VERSION 5.8 ;
BUSBITCHARS "[]" ;
DIVIDERCHAR "/" ;
UNITS
    DATABASE MICRONS 1000 ;
END UNITS

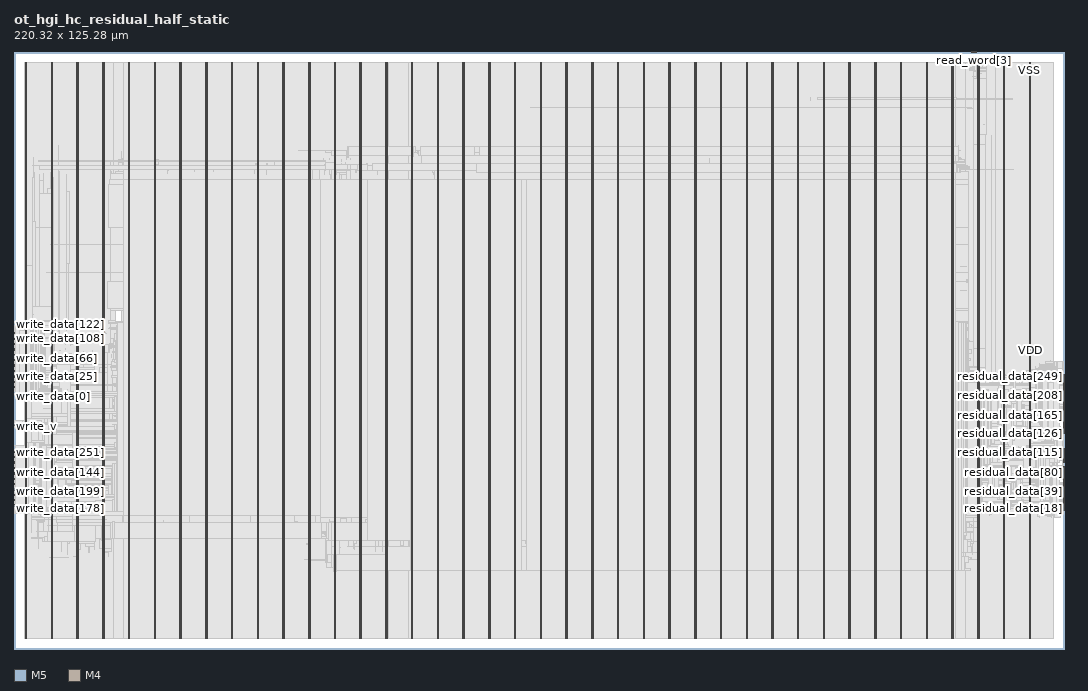
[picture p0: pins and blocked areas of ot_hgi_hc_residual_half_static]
MACRO ot_hgi_hc_residual_half_static
  FOREIGN ot_hgi_hc_residual_half_static 0 0 ;
  CLASS BLOCK ;
  SIZE 220.32 BY 125.28 ;
  PIN clk
    DIRECTION INPUT ;
    USE SIGNAL ;
    PORT
      LAYER M5 ;
        RECT  200.88 125.196 200.904 125.28 ;
    END
  END clk
  PIN fault
    DIRECTION OUTPUT ;
    USE SIGNAL ;
    PORT
      LAYER M4 ;
        RECT  220.236 29.136 220.32 29.16 ;
    END
  END fault
  PIN read_v
    DIRECTION INPUT ;
    USE SIGNAL ;
    PORT
      LAYER M5 ;
        RECT  200.976 125.196 201 125.28 ;
    END
  END read_v
  PIN read_valid
    DIRECTION OUTPUT ;
    USE SIGNAL ;
    PORT
      LAYER M4 ;
        RECT  220.236 29.232 220.32 29.256 ;
    END
  END read_valid
  PIN read_word[0]
    DIRECTION INPUT ;
    USE SIGNAL ;
    PORT
      LAYER M5 ;
        RECT  201.072 125.196 201.096 125.28 ;
    END
  END read_word[0]
  PIN read_word[1]
    DIRECTION INPUT ;
    USE SIGNAL ;
    PORT
      LAYER M5 ;
        RECT  201.168 125.196 201.192 125.28 ;
    END
  END read_word[1]
  PIN read_word[2]
    DIRECTION INPUT ;
    USE SIGNAL ;
    PORT
      LAYER M5 ;
        RECT  201.264 125.196 201.288 125.28 ;
    END
  END read_word[2]
  PIN read_word[3]
    DIRECTION INPUT ;
    USE SIGNAL ;
    PORT
      LAYER M5 ;
        RECT  201.36 125.196 201.384 125.28 ;
    END
  END read_word[3]
  PIN read_word[4]
    DIRECTION INPUT ;
    USE SIGNAL ;
    PORT
      LAYER M5 ;
        RECT  201.456 125.196 201.48 125.28 ;
    END
  END read_word[4]
  PIN read_word[5]
    DIRECTION INPUT ;
    USE SIGNAL ;
    PORT
      LAYER M5 ;
        RECT  201.552 125.196 201.576 125.28 ;
    END
  END read_word[5]
  PIN read_word[6]
    DIRECTION INPUT ;
    USE SIGNAL ;
    PORT
      LAYER M5 ;
        RECT  201.648 125.196 201.672 125.28 ;
    END
  END read_word[6]
  PIN read_word[7]
    DIRECTION INPUT ;
    USE SIGNAL ;
    PORT
      LAYER M5 ;
        RECT  201.744 125.196 201.768 125.28 ;
    END
  END read_word[7]
  PIN read_word[8]
    DIRECTION INPUT ;
    USE SIGNAL ;
    PORT
      LAYER M5 ;
        RECT  201.84 125.196 201.864 125.28 ;
    END
  END read_word[8]
  PIN read_word[9]
    DIRECTION INPUT ;
    USE SIGNAL ;
    PORT
      LAYER M5 ;
        RECT  201.936 125.196 201.96 125.28 ;
    END
  END read_word[9]
  PIN residual_data[0]
    DIRECTION OUTPUT ;
    USE SIGNAL ;
    PORT
      LAYER M4 ;
        RECT  220.236 29.328 220.32 29.352 ;
    END
  END residual_data[0]
  PIN residual_data[100]
    DIRECTION OUTPUT ;
    USE SIGNAL ;
    PORT
      LAYER M4 ;
        RECT  220.236 39.696 220.32 39.72 ;
    END
  END residual_data[100]
  PIN residual_data[101]
    DIRECTION OUTPUT ;
    USE SIGNAL ;
    PORT
      LAYER M4 ;
        RECT  220.236 39.792 220.32 39.816 ;
    END
  END residual_data[101]
  PIN residual_data[102]
    DIRECTION OUTPUT ;
    USE SIGNAL ;
    PORT
      LAYER M4 ;
        RECT  220.236 39.888 220.32 39.912 ;
    END
  END residual_data[102]
  PIN residual_data[103]
    DIRECTION OUTPUT ;
    USE SIGNAL ;
    PORT
      LAYER M4 ;
        RECT  220.236 39.984 220.32 40.008 ;
    END
  END residual_data[103]
  PIN residual_data[104]
    DIRECTION OUTPUT ;
    USE SIGNAL ;
    PORT
      LAYER M4 ;
        RECT  220.236 40.08 220.32 40.104 ;
    END
  END residual_data[104]
  PIN residual_data[105]
    DIRECTION OUTPUT ;
    USE SIGNAL ;
    PORT
      LAYER M4 ;
        RECT  220.236 40.176 220.32 40.2 ;
    END
  END residual_data[105]
  PIN residual_data[106]
    DIRECTION OUTPUT ;
    USE SIGNAL ;
    PORT
      LAYER M4 ;
        RECT  220.236 40.272 220.32 40.296 ;
    END
  END residual_data[106]
  PIN residual_data[107]
    DIRECTION OUTPUT ;
    USE SIGNAL ;
    PORT
      LAYER M4 ;
        RECT  220.236 40.368 220.32 40.392 ;
    END
  END residual_data[107]
  PIN residual_data[108]
    DIRECTION OUTPUT ;
    USE SIGNAL ;
    PORT
      LAYER M4 ;
        RECT  220.236 40.464 220.32 40.488 ;
    END
  END residual_data[108]
  PIN residual_data[109]
    DIRECTION OUTPUT ;
    USE SIGNAL ;
    PORT
      LAYER M4 ;
        RECT  220.236 40.56 220.32 40.584 ;
    END
  END residual_data[109]
  PIN residual_data[10]
    DIRECTION OUTPUT ;
    USE SIGNAL ;
    PORT
      LAYER M4 ;
        RECT  220.236 30.288 220.32 30.312 ;
    END
  END residual_data[10]
  PIN residual_data[110]
    DIRECTION OUTPUT ;
    USE SIGNAL ;
    PORT
      LAYER M4 ;
        RECT  220.236 40.656 220.32 40.68 ;
    END
  END residual_data[110]
  PIN residual_data[111]
    DIRECTION OUTPUT ;
    USE SIGNAL ;
    PORT
      LAYER M4 ;
        RECT  220.236 40.752 220.32 40.776 ;
    END
  END residual_data[111]
  PIN residual_data[112]
    DIRECTION OUTPUT ;
    USE SIGNAL ;
    PORT
      LAYER M4 ;
        RECT  220.236 40.848 220.32 40.872 ;
    END
  END residual_data[112]
  PIN residual_data[113]
    DIRECTION OUTPUT ;
    USE SIGNAL ;
    PORT
      LAYER M4 ;
        RECT  220.236 40.944 220.32 40.968 ;
    END
  END residual_data[113]
  PIN residual_data[114]
    DIRECTION OUTPUT ;
    USE SIGNAL ;
    PORT
      LAYER M4 ;
        RECT  220.236 41.04 220.32 41.064 ;
    END
  END residual_data[114]
  PIN residual_data[115]
    DIRECTION OUTPUT ;
    USE SIGNAL ;
    PORT
      LAYER M4 ;
        RECT  220.236 41.136 220.32 41.16 ;
    END
  END residual_data[115]
  PIN residual_data[116]
    DIRECTION OUTPUT ;
    USE SIGNAL ;
    PORT
      LAYER M4 ;
        RECT  220.236 41.232 220.32 41.256 ;
    END
  END residual_data[116]
  PIN residual_data[117]
    DIRECTION OUTPUT ;
    USE SIGNAL ;
    PORT
      LAYER M4 ;
        RECT  220.236 41.328 220.32 41.352 ;
    END
  END residual_data[117]
  PIN residual_data[118]
    DIRECTION OUTPUT ;
    USE SIGNAL ;
    PORT
      LAYER M4 ;
        RECT  220.236 41.424 220.32 41.448 ;
    END
  END residual_data[118]
  PIN residual_data[119]
    DIRECTION OUTPUT ;
    USE SIGNAL ;
    PORT
      LAYER M4 ;
        RECT  220.236 41.52 220.32 41.544 ;
    END
  END residual_data[119]
  PIN residual_data[11]
    DIRECTION OUTPUT ;
    USE SIGNAL ;
    PORT
      LAYER M4 ;
        RECT  220.236 30.384 220.32 30.408 ;
    END
  END residual_data[11]
  PIN residual_data[120]
    DIRECTION OUTPUT ;
    USE SIGNAL ;
    PORT
      LAYER M4 ;
        RECT  220.236 41.616 220.32 41.64 ;
    END
  END residual_data[120]
  PIN residual_data[121]
    DIRECTION OUTPUT ;
    USE SIGNAL ;
    PORT
      LAYER M4 ;
        RECT  220.236 41.712 220.32 41.736 ;
    END
  END residual_data[121]
  PIN residual_data[122]
    DIRECTION OUTPUT ;
    USE SIGNAL ;
    PORT
      LAYER M4 ;
        RECT  220.236 41.808 220.32 41.832 ;
    END
  END residual_data[122]
  PIN residual_data[123]
    DIRECTION OUTPUT ;
    USE SIGNAL ;
    PORT
      LAYER M4 ;
        RECT  220.236 41.904 220.32 41.928 ;
    END
  END residual_data[123]
  PIN residual_data[124]
    DIRECTION OUTPUT ;
    USE SIGNAL ;
    PORT
      LAYER M4 ;
        RECT  220.236 42 220.32 42.024 ;
    END
  END residual_data[124]
  PIN residual_data[125]
    DIRECTION OUTPUT ;
    USE SIGNAL ;
    PORT
      LAYER M4 ;
        RECT  220.236 42.096 220.32 42.12 ;
    END
  END residual_data[125]
  PIN residual_data[126]
    DIRECTION OUTPUT ;
    USE SIGNAL ;
    PORT
      LAYER M4 ;
        RECT  220.236 45.264 220.32 45.288 ;
    END
  END residual_data[126]
  PIN residual_data[127]
    DIRECTION OUTPUT ;
    USE SIGNAL ;
    PORT
      LAYER M4 ;
        RECT  220.236 45.36 220.32 45.384 ;
    END
  END residual_data[127]
  PIN residual_data[128]
    DIRECTION OUTPUT ;
    USE SIGNAL ;
    PORT
      LAYER M4 ;
        RECT  220.236 45.456 220.32 45.48 ;
    END
  END residual_data[128]
  PIN residual_data[129]
    DIRECTION OUTPUT ;
    USE SIGNAL ;
    PORT
      LAYER M4 ;
        RECT  220.236 45.552 220.32 45.576 ;
    END
  END residual_data[129]
  PIN residual_data[12]
    DIRECTION OUTPUT ;
    USE SIGNAL ;
    PORT
      LAYER M4 ;
        RECT  220.236 30.48 220.32 30.504 ;
    END
  END residual_data[12]
  PIN residual_data[130]
    DIRECTION OUTPUT ;
    USE SIGNAL ;
    PORT
      LAYER M4 ;
        RECT  220.236 45.648 220.32 45.672 ;
    END
  END residual_data[130]
  PIN residual_data[131]
    DIRECTION OUTPUT ;
    USE SIGNAL ;
    PORT
      LAYER M4 ;
        RECT  220.236 45.744 220.32 45.768 ;
    END
  END residual_data[131]
  PIN residual_data[132]
    DIRECTION OUTPUT ;
    USE SIGNAL ;
    PORT
      LAYER M4 ;
        RECT  220.236 45.84 220.32 45.864 ;
    END
  END residual_data[132]
  PIN residual_data[133]
    DIRECTION OUTPUT ;
    USE SIGNAL ;
    PORT
      LAYER M4 ;
        RECT  220.236 45.936 220.32 45.96 ;
    END
  END residual_data[133]
  PIN residual_data[134]
    DIRECTION OUTPUT ;
    USE SIGNAL ;
    PORT
      LAYER M4 ;
        RECT  220.236 46.032 220.32 46.056 ;
    END
  END residual_data[134]
  PIN residual_data[135]
    DIRECTION OUTPUT ;
    USE SIGNAL ;
    PORT
      LAYER M4 ;
        RECT  220.236 46.128 220.32 46.152 ;
    END
  END residual_data[135]
  PIN residual_data[136]
    DIRECTION OUTPUT ;
    USE SIGNAL ;
    PORT
      LAYER M4 ;
        RECT  220.236 46.224 220.32 46.248 ;
    END
  END residual_data[136]
  PIN residual_data[137]
    DIRECTION OUTPUT ;
    USE SIGNAL ;
    PORT
      LAYER M4 ;
        RECT  220.236 46.32 220.32 46.344 ;
    END
  END residual_data[137]
  PIN residual_data[138]
    DIRECTION OUTPUT ;
    USE SIGNAL ;
    PORT
      LAYER M4 ;
        RECT  220.236 46.416 220.32 46.44 ;
    END
  END residual_data[138]
  PIN residual_data[139]
    DIRECTION OUTPUT ;
    USE SIGNAL ;
    PORT
      LAYER M4 ;
        RECT  220.236 46.512 220.32 46.536 ;
    END
  END residual_data[139]
  PIN residual_data[13]
    DIRECTION OUTPUT ;
    USE SIGNAL ;
    PORT
      LAYER M4 ;
        RECT  220.236 30.576 220.32 30.6 ;
    END
  END residual_data[13]
  PIN residual_data[140]
    DIRECTION OUTPUT ;
    USE SIGNAL ;
    PORT
      LAYER M4 ;
        RECT  220.236 46.608 220.32 46.632 ;
    END
  END residual_data[140]
  PIN residual_data[141]
    DIRECTION OUTPUT ;
    USE SIGNAL ;
    PORT
      LAYER M4 ;
        RECT  220.236 46.704 220.32 46.728 ;
    END
  END residual_data[141]
  PIN residual_data[142]
    DIRECTION OUTPUT ;
    USE SIGNAL ;
    PORT
      LAYER M4 ;
        RECT  220.236 46.8 220.32 46.824 ;
    END
  END residual_data[142]
  PIN residual_data[143]
    DIRECTION OUTPUT ;
    USE SIGNAL ;
    PORT
      LAYER M4 ;
        RECT  220.236 46.896 220.32 46.92 ;
    END
  END residual_data[143]
  PIN residual_data[144]
    DIRECTION OUTPUT ;
    USE SIGNAL ;
    PORT
      LAYER M4 ;
        RECT  220.236 46.992 220.32 47.016 ;
    END
  END residual_data[144]
  PIN residual_data[145]
    DIRECTION OUTPUT ;
    USE SIGNAL ;
    PORT
      LAYER M4 ;
        RECT  220.236 47.088 220.32 47.112 ;
    END
  END residual_data[145]
  PIN residual_data[146]
    DIRECTION OUTPUT ;
    USE SIGNAL ;
    PORT
      LAYER M4 ;
        RECT  220.236 47.184 220.32 47.208 ;
    END
  END residual_data[146]
  PIN residual_data[147]
    DIRECTION OUTPUT ;
    USE SIGNAL ;
    PORT
      LAYER M4 ;
        RECT  220.236 47.28 220.32 47.304 ;
    END
  END residual_data[147]
  PIN residual_data[148]
    DIRECTION OUTPUT ;
    USE SIGNAL ;
    PORT
      LAYER M4 ;
        RECT  220.236 47.376 220.32 47.4 ;
    END
  END residual_data[148]
  PIN residual_data[149]
    DIRECTION OUTPUT ;
    USE SIGNAL ;
    PORT
      LAYER M4 ;
        RECT  220.236 47.472 220.32 47.496 ;
    END
  END residual_data[149]
  PIN residual_data[14]
    DIRECTION OUTPUT ;
    USE SIGNAL ;
    PORT
      LAYER M4 ;
        RECT  220.236 30.672 220.32 30.696 ;
    END
  END residual_data[14]
  PIN residual_data[150]
    DIRECTION OUTPUT ;
    USE SIGNAL ;
    PORT
      LAYER M4 ;
        RECT  220.236 47.568 220.32 47.592 ;
    END
  END residual_data[150]
  PIN residual_data[151]
    DIRECTION OUTPUT ;
    USE SIGNAL ;
    PORT
      LAYER M4 ;
        RECT  220.236 47.664 220.32 47.688 ;
    END
  END residual_data[151]
  PIN residual_data[152]
    DIRECTION OUTPUT ;
    USE SIGNAL ;
    PORT
      LAYER M4 ;
        RECT  220.236 47.76 220.32 47.784 ;
    END
  END residual_data[152]
  PIN residual_data[153]
    DIRECTION OUTPUT ;
    USE SIGNAL ;
    PORT
      LAYER M4 ;
        RECT  220.236 47.856 220.32 47.88 ;
    END
  END residual_data[153]
  PIN residual_data[154]
    DIRECTION OUTPUT ;
    USE SIGNAL ;
    PORT
      LAYER M4 ;
        RECT  220.236 47.952 220.32 47.976 ;
    END
  END residual_data[154]
  PIN residual_data[155]
    DIRECTION OUTPUT ;
    USE SIGNAL ;
    PORT
      LAYER M4 ;
        RECT  220.236 48.048 220.32 48.072 ;
    END
  END residual_data[155]
  PIN residual_data[156]
    DIRECTION OUTPUT ;
    USE SIGNAL ;
    PORT
      LAYER M4 ;
        RECT  220.236 48.144 220.32 48.168 ;
    END
  END residual_data[156]
  PIN residual_data[157]
    DIRECTION OUTPUT ;
    USE SIGNAL ;
    PORT
      LAYER M4 ;
        RECT  220.236 48.24 220.32 48.264 ;
    END
  END residual_data[157]
  PIN residual_data[158]
    DIRECTION OUTPUT ;
    USE SIGNAL ;
    PORT
      LAYER M4 ;
        RECT  220.236 48.336 220.32 48.36 ;
    END
  END residual_data[158]
  PIN residual_data[159]
    DIRECTION OUTPUT ;
    USE SIGNAL ;
    PORT
      LAYER M4 ;
        RECT  220.236 48.432 220.32 48.456 ;
    END
  END residual_data[159]
  PIN residual_data[15]
    DIRECTION OUTPUT ;
    USE SIGNAL ;
    PORT
      LAYER M4 ;
        RECT  220.236 30.768 220.32 30.792 ;
    END
  END residual_data[15]
  PIN residual_data[160]
    DIRECTION OUTPUT ;
    USE SIGNAL ;
    PORT
      LAYER M4 ;
        RECT  220.236 48.528 220.32 48.552 ;
    END
  END residual_data[160]
  PIN residual_data[161]
    DIRECTION OUTPUT ;
    USE SIGNAL ;
    PORT
      LAYER M4 ;
        RECT  220.236 48.624 220.32 48.648 ;
    END
  END residual_data[161]
  PIN residual_data[162]
    DIRECTION OUTPUT ;
    USE SIGNAL ;
    PORT
      LAYER M4 ;
        RECT  220.236 48.72 220.32 48.744 ;
    END
  END residual_data[162]
  PIN residual_data[163]
    DIRECTION OUTPUT ;
    USE SIGNAL ;
    PORT
      LAYER M4 ;
        RECT  220.236 48.816 220.32 48.84 ;
    END
  END residual_data[163]
  PIN residual_data[164]
    DIRECTION OUTPUT ;
    USE SIGNAL ;
    PORT
      LAYER M4 ;
        RECT  220.236 48.912 220.32 48.936 ;
    END
  END residual_data[164]
  PIN residual_data[165]
    DIRECTION OUTPUT ;
    USE SIGNAL ;
    PORT
      LAYER M4 ;
        RECT  220.236 49.008 220.32 49.032 ;
    END
  END residual_data[165]
  PIN residual_data[166]
    DIRECTION OUTPUT ;
    USE SIGNAL ;
    PORT
      LAYER M4 ;
        RECT  220.236 49.104 220.32 49.128 ;
    END
  END residual_data[166]
  PIN residual_data[167]
    DIRECTION OUTPUT ;
    USE SIGNAL ;
    PORT
      LAYER M4 ;
        RECT  220.236 49.2 220.32 49.224 ;
    END
  END residual_data[167]
  PIN residual_data[168]
    DIRECTION OUTPUT ;
    USE SIGNAL ;
    PORT
      LAYER M4 ;
        RECT  220.236 49.296 220.32 49.32 ;
    END
  END residual_data[168]
  PIN residual_data[169]
    DIRECTION OUTPUT ;
    USE SIGNAL ;
    PORT
      LAYER M4 ;
        RECT  220.236 49.392 220.32 49.416 ;
    END
  END residual_data[169]
  PIN residual_data[16]
    DIRECTION OUTPUT ;
    USE SIGNAL ;
    PORT
      LAYER M4 ;
        RECT  220.236 30.864 220.32 30.888 ;
    END
  END residual_data[16]
  PIN residual_data[170]
    DIRECTION OUTPUT ;
    USE SIGNAL ;
    PORT
      LAYER M4 ;
        RECT  220.236 49.488 220.32 49.512 ;
    END
  END residual_data[170]
  PIN residual_data[171]
    DIRECTION OUTPUT ;
    USE SIGNAL ;
    PORT
      LAYER M4 ;
        RECT  220.236 49.584 220.32 49.608 ;
    END
  END residual_data[171]
  PIN residual_data[172]
    DIRECTION OUTPUT ;
    USE SIGNAL ;
    PORT
      LAYER M4 ;
        RECT  220.236 49.68 220.32 49.704 ;
    END
  END residual_data[172]
  PIN residual_data[173]
    DIRECTION OUTPUT ;
    USE SIGNAL ;
    PORT
      LAYER M4 ;
        RECT  220.236 49.776 220.32 49.8 ;
    END
  END residual_data[173]
  PIN residual_data[174]
    DIRECTION OUTPUT ;
    USE SIGNAL ;
    PORT
      LAYER M4 ;
        RECT  220.236 49.872 220.32 49.896 ;
    END
  END residual_data[174]
  PIN residual_data[175]
    DIRECTION OUTPUT ;
    USE SIGNAL ;
    PORT
      LAYER M4 ;
        RECT  220.236 49.968 220.32 49.992 ;
    END
  END residual_data[175]
  PIN residual_data[176]
    DIRECTION OUTPUT ;
    USE SIGNAL ;
    PORT
      LAYER M4 ;
        RECT  220.236 50.064 220.32 50.088 ;
    END
  END residual_data[176]
  PIN residual_data[177]
    DIRECTION OUTPUT ;
    USE SIGNAL ;
    PORT
      LAYER M4 ;
        RECT  220.236 50.16 220.32 50.184 ;
    END
  END residual_data[177]
  PIN residual_data[178]
    DIRECTION OUTPUT ;
    USE SIGNAL ;
    PORT
      LAYER M4 ;
        RECT  220.236 50.256 220.32 50.28 ;
    END
  END residual_data[178]
  PIN residual_data[179]
    DIRECTION OUTPUT ;
    USE SIGNAL ;
    PORT
      LAYER M4 ;
        RECT  220.236 50.352 220.32 50.376 ;
    END
  END residual_data[179]
  PIN residual_data[17]
    DIRECTION OUTPUT ;
    USE SIGNAL ;
    PORT
      LAYER M4 ;
        RECT  220.236 30.96 220.32 30.984 ;
    END
  END residual_data[17]
  PIN residual_data[180]
    DIRECTION OUTPUT ;
    USE SIGNAL ;
    PORT
      LAYER M4 ;
        RECT  220.236 50.448 220.32 50.472 ;
    END
  END residual_data[180]
  PIN residual_data[181]
    DIRECTION OUTPUT ;
    USE SIGNAL ;
    PORT
      LAYER M4 ;
        RECT  220.236 50.544 220.32 50.568 ;
    END
  END residual_data[181]
  PIN residual_data[182]
    DIRECTION OUTPUT ;
    USE SIGNAL ;
    PORT
      LAYER M4 ;
        RECT  220.236 50.64 220.32 50.664 ;
    END
  END residual_data[182]
  PIN residual_data[183]
    DIRECTION OUTPUT ;
    USE SIGNAL ;
    PORT
      LAYER M4 ;
        RECT  220.236 50.736 220.32 50.76 ;
    END
  END residual_data[183]
  PIN residual_data[184]
    DIRECTION OUTPUT ;
    USE SIGNAL ;
    PORT
      LAYER M4 ;
        RECT  220.236 50.832 220.32 50.856 ;
    END
  END residual_data[184]
  PIN residual_data[185]
    DIRECTION OUTPUT ;
    USE SIGNAL ;
    PORT
      LAYER M4 ;
        RECT  220.236 50.928 220.32 50.952 ;
    END
  END residual_data[185]
  PIN residual_data[186]
    DIRECTION OUTPUT ;
    USE SIGNAL ;
    PORT
      LAYER M4 ;
        RECT  220.236 51.024 220.32 51.048 ;
    END
  END residual_data[186]
  PIN residual_data[187]
    DIRECTION OUTPUT ;
    USE SIGNAL ;
    PORT
      LAYER M4 ;
        RECT  220.236 51.12 220.32 51.144 ;
    END
  END residual_data[187]
  PIN residual_data[188]
    DIRECTION OUTPUT ;
    USE SIGNAL ;
    PORT
      LAYER M4 ;
        RECT  220.236 51.216 220.32 51.24 ;
    END
  END residual_data[188]
  PIN residual_data[189]
    DIRECTION OUTPUT ;
    USE SIGNAL ;
    PORT
      LAYER M4 ;
        RECT  220.236 51.312 220.32 51.336 ;
    END
  END residual_data[189]
  PIN residual_data[18]
    DIRECTION OUTPUT ;
    USE SIGNAL ;
    PORT
      LAYER M4 ;
        RECT  220.236 31.056 220.32 31.08 ;
    END
  END residual_data[18]
  PIN residual_data[190]
    DIRECTION OUTPUT ;
    USE SIGNAL ;
    PORT
      LAYER M4 ;
        RECT  220.236 51.408 220.32 51.432 ;
    END
  END residual_data[190]
  PIN residual_data[191]
    DIRECTION OUTPUT ;
    USE SIGNAL ;
    PORT
      LAYER M4 ;
        RECT  220.236 51.504 220.32 51.528 ;
    END
  END residual_data[191]
  PIN residual_data[192]
    DIRECTION OUTPUT ;
    USE SIGNAL ;
    PORT
      LAYER M4 ;
        RECT  220.236 51.6 220.32 51.624 ;
    END
  END residual_data[192]
  PIN residual_data[193]
    DIRECTION OUTPUT ;
    USE SIGNAL ;
    PORT
      LAYER M4 ;
        RECT  220.236 51.696 220.32 51.72 ;
    END
  END residual_data[193]
  PIN residual_data[194]
    DIRECTION OUTPUT ;
    USE SIGNAL ;
    PORT
      LAYER M4 ;
        RECT  220.236 51.792 220.32 51.816 ;
    END
  END residual_data[194]
  PIN residual_data[195]
    DIRECTION OUTPUT ;
    USE SIGNAL ;
    PORT
      LAYER M4 ;
        RECT  220.236 51.888 220.32 51.912 ;
    END
  END residual_data[195]
  PIN residual_data[196]
    DIRECTION OUTPUT ;
    USE SIGNAL ;
    PORT
      LAYER M4 ;
        RECT  220.236 51.984 220.32 52.008 ;
    END
  END residual_data[196]
  PIN residual_data[197]
    DIRECTION OUTPUT ;
    USE SIGNAL ;
    PORT
      LAYER M4 ;
        RECT  220.236 52.08 220.32 52.104 ;
    END
  END residual_data[197]
  PIN residual_data[198]
    DIRECTION OUTPUT ;
    USE SIGNAL ;
    PORT
      LAYER M4 ;
        RECT  220.236 52.176 220.32 52.2 ;
    END
  END residual_data[198]
  PIN residual_data[199]
    DIRECTION OUTPUT ;
    USE SIGNAL ;
    PORT
      LAYER M4 ;
        RECT  220.236 52.272 220.32 52.296 ;
    END
  END residual_data[199]
  PIN residual_data[19]
    DIRECTION OUTPUT ;
    USE SIGNAL ;
    PORT
      LAYER M4 ;
        RECT  220.236 31.152 220.32 31.176 ;
    END
  END residual_data[19]
  PIN residual_data[1]
    DIRECTION OUTPUT ;
    USE SIGNAL ;
    PORT
      LAYER M4 ;
        RECT  220.236 29.424 220.32 29.448 ;
    END
  END residual_data[1]
  PIN residual_data[200]
    DIRECTION OUTPUT ;
    USE SIGNAL ;
    PORT
      LAYER M4 ;
        RECT  220.236 52.368 220.32 52.392 ;
    END
  END residual_data[200]
  PIN residual_data[201]
    DIRECTION OUTPUT ;
    USE SIGNAL ;
    PORT
      LAYER M4 ;
        RECT  220.236 52.464 220.32 52.488 ;
    END
  END residual_data[201]
  PIN residual_data[202]
    DIRECTION OUTPUT ;
    USE SIGNAL ;
    PORT
      LAYER M4 ;
        RECT  220.236 52.56 220.32 52.584 ;
    END
  END residual_data[202]
  PIN residual_data[203]
    DIRECTION OUTPUT ;
    USE SIGNAL ;
    PORT
      LAYER M4 ;
        RECT  220.236 52.656 220.32 52.68 ;
    END
  END residual_data[203]
  PIN residual_data[204]
    DIRECTION OUTPUT ;
    USE SIGNAL ;
    PORT
      LAYER M4 ;
        RECT  220.236 52.752 220.32 52.776 ;
    END
  END residual_data[204]
  PIN residual_data[205]
    DIRECTION OUTPUT ;
    USE SIGNAL ;
    PORT
      LAYER M4 ;
        RECT  220.236 52.848 220.32 52.872 ;
    END
  END residual_data[205]
  PIN residual_data[206]
    DIRECTION OUTPUT ;
    USE SIGNAL ;
    PORT
      LAYER M4 ;
        RECT  220.236 52.944 220.32 52.968 ;
    END
  END residual_data[206]
  PIN residual_data[207]
    DIRECTION OUTPUT ;
    USE SIGNAL ;
    PORT
      LAYER M4 ;
        RECT  220.236 53.04 220.32 53.064 ;
    END
  END residual_data[207]
  PIN residual_data[208]
    DIRECTION OUTPUT ;
    USE SIGNAL ;
    PORT
      LAYER M4 ;
        RECT  220.236 53.136 220.32 53.16 ;
    END
  END residual_data[208]
  PIN residual_data[209]
    DIRECTION OUTPUT ;
    USE SIGNAL ;
    PORT
      LAYER M4 ;
        RECT  220.236 53.232 220.32 53.256 ;
    END
  END residual_data[209]
  PIN residual_data[20]
    DIRECTION OUTPUT ;
    USE SIGNAL ;
    PORT
      LAYER M4 ;
        RECT  220.236 31.248 220.32 31.272 ;
    END
  END residual_data[20]
  PIN residual_data[210]
    DIRECTION OUTPUT ;
    USE SIGNAL ;
    PORT
      LAYER M4 ;
        RECT  220.236 53.328 220.32 53.352 ;
    END
  END residual_data[210]
  PIN residual_data[211]
    DIRECTION OUTPUT ;
    USE SIGNAL ;
    PORT
      LAYER M4 ;
        RECT  220.236 53.424 220.32 53.448 ;
    END
  END residual_data[211]
  PIN residual_data[212]
    DIRECTION OUTPUT ;
    USE SIGNAL ;
    PORT
      LAYER M4 ;
        RECT  220.236 53.52 220.32 53.544 ;
    END
  END residual_data[212]
  PIN residual_data[213]
    DIRECTION OUTPUT ;
    USE SIGNAL ;
    PORT
      LAYER M4 ;
        RECT  220.236 53.616 220.32 53.64 ;
    END
  END residual_data[213]
  PIN residual_data[214]
    DIRECTION OUTPUT ;
    USE SIGNAL ;
    PORT
      LAYER M4 ;
        RECT  220.236 53.712 220.32 53.736 ;
    END
  END residual_data[214]
  PIN residual_data[215]
    DIRECTION OUTPUT ;
    USE SIGNAL ;
    PORT
      LAYER M4 ;
        RECT  220.236 53.808 220.32 53.832 ;
    END
  END residual_data[215]
  PIN residual_data[216]
    DIRECTION OUTPUT ;
    USE SIGNAL ;
    PORT
      LAYER M4 ;
        RECT  220.236 53.904 220.32 53.928 ;
    END
  END residual_data[216]
  PIN residual_data[217]
    DIRECTION OUTPUT ;
    USE SIGNAL ;
    PORT
      LAYER M4 ;
        RECT  220.236 54 220.32 54.024 ;
    END
  END residual_data[217]
  PIN residual_data[218]
    DIRECTION OUTPUT ;
    USE SIGNAL ;
    PORT
      LAYER M4 ;
        RECT  220.236 54.096 220.32 54.12 ;
    END
  END residual_data[218]
  PIN residual_data[219]
    DIRECTION OUTPUT ;
    USE SIGNAL ;
    PORT
      LAYER M4 ;
        RECT  220.236 54.192 220.32 54.216 ;
    END
  END residual_data[219]
  PIN residual_data[21]
    DIRECTION OUTPUT ;
    USE SIGNAL ;
    PORT
      LAYER M4 ;
        RECT  220.236 31.344 220.32 31.368 ;
    END
  END residual_data[21]
  PIN residual_data[220]
    DIRECTION OUTPUT ;
    USE SIGNAL ;
    PORT
      LAYER M4 ;
        RECT  220.236 54.288 220.32 54.312 ;
    END
  END residual_data[220]
  PIN residual_data[221]
    DIRECTION OUTPUT ;
    USE SIGNAL ;
    PORT
      LAYER M4 ;
        RECT  220.236 54.384 220.32 54.408 ;
    END
  END residual_data[221]
  PIN residual_data[222]
    DIRECTION OUTPUT ;
    USE SIGNAL ;
    PORT
      LAYER M4 ;
        RECT  220.236 54.48 220.32 54.504 ;
    END
  END residual_data[222]
  PIN residual_data[223]
    DIRECTION OUTPUT ;
    USE SIGNAL ;
    PORT
      LAYER M4 ;
        RECT  220.236 54.576 220.32 54.6 ;
    END
  END residual_data[223]
  PIN residual_data[224]
    DIRECTION OUTPUT ;
    USE SIGNAL ;
    PORT
      LAYER M4 ;
        RECT  220.236 54.672 220.32 54.696 ;
    END
  END residual_data[224]
  PIN residual_data[225]
    DIRECTION OUTPUT ;
    USE SIGNAL ;
    PORT
      LAYER M4 ;
        RECT  220.236 54.768 220.32 54.792 ;
    END
  END residual_data[225]
  PIN residual_data[226]
    DIRECTION OUTPUT ;
    USE SIGNAL ;
    PORT
      LAYER M4 ;
        RECT  220.236 54.864 220.32 54.888 ;
    END
  END residual_data[226]
  PIN residual_data[227]
    DIRECTION OUTPUT ;
    USE SIGNAL ;
    PORT
      LAYER M4 ;
        RECT  220.236 54.96 220.32 54.984 ;
    END
  END residual_data[227]
  PIN residual_data[228]
    DIRECTION OUTPUT ;
    USE SIGNAL ;
    PORT
      LAYER M4 ;
        RECT  220.236 55.056 220.32 55.08 ;
    END
  END residual_data[228]
  PIN residual_data[229]
    DIRECTION OUTPUT ;
    USE SIGNAL ;
    PORT
      LAYER M4 ;
        RECT  220.236 55.152 220.32 55.176 ;
    END
  END residual_data[229]
  PIN residual_data[22]
    DIRECTION OUTPUT ;
    USE SIGNAL ;
    PORT
      LAYER M4 ;
        RECT  220.236 31.44 220.32 31.464 ;
    END
  END residual_data[22]
  PIN residual_data[230]
    DIRECTION OUTPUT ;
    USE SIGNAL ;
    PORT
      LAYER M4 ;
        RECT  220.236 55.248 220.32 55.272 ;
    END
  END residual_data[230]
  PIN residual_data[231]
    DIRECTION OUTPUT ;
    USE SIGNAL ;
    PORT
      LAYER M4 ;
        RECT  220.236 55.344 220.32 55.368 ;
    END
  END residual_data[231]
  PIN residual_data[232]
    DIRECTION OUTPUT ;
    USE SIGNAL ;
    PORT
      LAYER M4 ;
        RECT  220.236 55.44 220.32 55.464 ;
    END
  END residual_data[232]
  PIN residual_data[233]
    DIRECTION OUTPUT ;
    USE SIGNAL ;
    PORT
      LAYER M4 ;
        RECT  220.236 55.536 220.32 55.56 ;
    END
  END residual_data[233]
  PIN residual_data[234]
    DIRECTION OUTPUT ;
    USE SIGNAL ;
    PORT
      LAYER M4 ;
        RECT  220.236 55.632 220.32 55.656 ;
    END
  END residual_data[234]
  PIN residual_data[235]
    DIRECTION OUTPUT ;
    USE SIGNAL ;
    PORT
      LAYER M4 ;
        RECT  220.236 55.728 220.32 55.752 ;
    END
  END residual_data[235]
  PIN residual_data[236]
    DIRECTION OUTPUT ;
    USE SIGNAL ;
    PORT
      LAYER M4 ;
        RECT  220.236 55.824 220.32 55.848 ;
    END
  END residual_data[236]
  PIN residual_data[237]
    DIRECTION OUTPUT ;
    USE SIGNAL ;
    PORT
      LAYER M4 ;
        RECT  220.236 55.92 220.32 55.944 ;
    END
  END residual_data[237]
  PIN residual_data[238]
    DIRECTION OUTPUT ;
    USE SIGNAL ;
    PORT
      LAYER M4 ;
        RECT  220.236 56.016 220.32 56.04 ;
    END
  END residual_data[238]
  PIN residual_data[239]
    DIRECTION OUTPUT ;
    USE SIGNAL ;
    PORT
      LAYER M4 ;
        RECT  220.236 56.112 220.32 56.136 ;
    END
  END residual_data[239]
  PIN residual_data[23]
    DIRECTION OUTPUT ;
    USE SIGNAL ;
    PORT
      LAYER M4 ;
        RECT  220.236 31.536 220.32 31.56 ;
    END
  END residual_data[23]
  PIN residual_data[240]
    DIRECTION OUTPUT ;
    USE SIGNAL ;
    PORT
      LAYER M4 ;
        RECT  220.236 56.208 220.32 56.232 ;
    END
  END residual_data[240]
  PIN residual_data[241]
    DIRECTION OUTPUT ;
    USE SIGNAL ;
    PORT
      LAYER M4 ;
        RECT  220.236 56.304 220.32 56.328 ;
    END
  END residual_data[241]
  PIN residual_data[242]
    DIRECTION OUTPUT ;
    USE SIGNAL ;
    PORT
      LAYER M4 ;
        RECT  220.236 56.4 220.32 56.424 ;
    END
  END residual_data[242]
  PIN residual_data[243]
    DIRECTION OUTPUT ;
    USE SIGNAL ;
    PORT
      LAYER M4 ;
        RECT  220.236 56.496 220.32 56.52 ;
    END
  END residual_data[243]
  PIN residual_data[244]
    DIRECTION OUTPUT ;
    USE SIGNAL ;
    PORT
      LAYER M4 ;
        RECT  220.236 56.592 220.32 56.616 ;
    END
  END residual_data[244]
  PIN residual_data[245]
    DIRECTION OUTPUT ;
    USE SIGNAL ;
    PORT
      LAYER M4 ;
        RECT  220.236 56.688 220.32 56.712 ;
    END
  END residual_data[245]
  PIN residual_data[246]
    DIRECTION OUTPUT ;
    USE SIGNAL ;
    PORT
      LAYER M4 ;
        RECT  220.236 56.784 220.32 56.808 ;
    END
  END residual_data[246]
  PIN residual_data[247]
    DIRECTION OUTPUT ;
    USE SIGNAL ;
    PORT
      LAYER M4 ;
        RECT  220.236 56.88 220.32 56.904 ;
    END
  END residual_data[247]
  PIN residual_data[248]
    DIRECTION OUTPUT ;
    USE SIGNAL ;
    PORT
      LAYER M4 ;
        RECT  220.236 56.976 220.32 57 ;
    END
  END residual_data[248]
  PIN residual_data[249]
    DIRECTION OUTPUT ;
    USE SIGNAL ;
    PORT
      LAYER M4 ;
        RECT  220.236 57.072 220.32 57.096 ;
    END
  END residual_data[249]
  PIN residual_data[24]
    DIRECTION OUTPUT ;
    USE SIGNAL ;
    PORT
      LAYER M4 ;
        RECT  220.236 31.632 220.32 31.656 ;
    END
  END residual_data[24]
  PIN residual_data[250]
    DIRECTION OUTPUT ;
    USE SIGNAL ;
    PORT
      LAYER M4 ;
        RECT  220.236 57.168 220.32 57.192 ;
    END
  END residual_data[250]
  PIN residual_data[251]
    DIRECTION OUTPUT ;
    USE SIGNAL ;
    PORT
      LAYER M4 ;
        RECT  220.236 57.264 220.32 57.288 ;
    END
  END residual_data[251]
  PIN residual_data[252]
    DIRECTION OUTPUT ;
    USE SIGNAL ;
    PORT
      LAYER M4 ;
        RECT  220.236 57.36 220.32 57.384 ;
    END
  END residual_data[252]
  PIN residual_data[253]
    DIRECTION OUTPUT ;
    USE SIGNAL ;
    PORT
      LAYER M4 ;
        RECT  220.236 57.456 220.32 57.48 ;
    END
  END residual_data[253]
  PIN residual_data[254]
    DIRECTION OUTPUT ;
    USE SIGNAL ;
    PORT
      LAYER M4 ;
        RECT  220.236 57.552 220.32 57.576 ;
    END
  END residual_data[254]
  PIN residual_data[255]
    DIRECTION OUTPUT ;
    USE SIGNAL ;
    PORT
      LAYER M4 ;
        RECT  220.236 57.648 220.32 57.672 ;
    END
  END residual_data[255]
  PIN residual_data[25]
    DIRECTION OUTPUT ;
    USE SIGNAL ;
    PORT
      LAYER M4 ;
        RECT  220.236 31.728 220.32 31.752 ;
    END
  END residual_data[25]
  PIN residual_data[26]
    DIRECTION OUTPUT ;
    USE SIGNAL ;
    PORT
      LAYER M4 ;
        RECT  220.236 31.824 220.32 31.848 ;
    END
  END residual_data[26]
  PIN residual_data[27]
    DIRECTION OUTPUT ;
    USE SIGNAL ;
    PORT
      LAYER M4 ;
        RECT  220.236 31.92 220.32 31.944 ;
    END
  END residual_data[27]
  PIN residual_data[28]
    DIRECTION OUTPUT ;
    USE SIGNAL ;
    PORT
      LAYER M4 ;
        RECT  220.236 32.016 220.32 32.04 ;
    END
  END residual_data[28]
  PIN residual_data[29]
    DIRECTION OUTPUT ;
    USE SIGNAL ;
    PORT
      LAYER M4 ;
        RECT  220.236 32.112 220.32 32.136 ;
    END
  END residual_data[29]
  PIN residual_data[2]
    DIRECTION OUTPUT ;
    USE SIGNAL ;
    PORT
      LAYER M4 ;
        RECT  220.236 29.52 220.32 29.544 ;
    END
  END residual_data[2]
  PIN residual_data[30]
    DIRECTION OUTPUT ;
    USE SIGNAL ;
    PORT
      LAYER M4 ;
        RECT  220.236 32.208 220.32 32.232 ;
    END
  END residual_data[30]
  PIN residual_data[31]
    DIRECTION OUTPUT ;
    USE SIGNAL ;
    PORT
      LAYER M4 ;
        RECT  220.236 32.304 220.32 32.328 ;
    END
  END residual_data[31]
  PIN residual_data[32]
    DIRECTION OUTPUT ;
    USE SIGNAL ;
    PORT
      LAYER M4 ;
        RECT  220.236 32.4 220.32 32.424 ;
    END
  END residual_data[32]
  PIN residual_data[33]
    DIRECTION OUTPUT ;
    USE SIGNAL ;
    PORT
      LAYER M4 ;
        RECT  220.236 32.496 220.32 32.52 ;
    END
  END residual_data[33]
  PIN residual_data[34]
    DIRECTION OUTPUT ;
    USE SIGNAL ;
    PORT
      LAYER M4 ;
        RECT  220.236 32.592 220.32 32.616 ;
    END
  END residual_data[34]
  PIN residual_data[35]
    DIRECTION OUTPUT ;
    USE SIGNAL ;
    PORT
      LAYER M4 ;
        RECT  220.236 32.688 220.32 32.712 ;
    END
  END residual_data[35]
  PIN residual_data[36]
    DIRECTION OUTPUT ;
    USE SIGNAL ;
    PORT
      LAYER M4 ;
        RECT  220.236 32.784 220.32 32.808 ;
    END
  END residual_data[36]
  PIN residual_data[37]
    DIRECTION OUTPUT ;
    USE SIGNAL ;
    PORT
      LAYER M4 ;
        RECT  220.236 32.88 220.32 32.904 ;
    END
  END residual_data[37]
  PIN residual_data[38]
    DIRECTION OUTPUT ;
    USE SIGNAL ;
    PORT
      LAYER M4 ;
        RECT  220.236 32.976 220.32 33 ;
    END
  END residual_data[38]
  PIN residual_data[39]
    DIRECTION OUTPUT ;
    USE SIGNAL ;
    PORT
      LAYER M4 ;
        RECT  220.236 33.072 220.32 33.096 ;
    END
  END residual_data[39]
  PIN residual_data[3]
    DIRECTION OUTPUT ;
    USE SIGNAL ;
    PORT
      LAYER M4 ;
        RECT  220.236 29.616 220.32 29.64 ;
    END
  END residual_data[3]
  PIN residual_data[40]
    DIRECTION OUTPUT ;
    USE SIGNAL ;
    PORT
      LAYER M4 ;
        RECT  220.236 33.168 220.32 33.192 ;
    END
  END residual_data[40]
  PIN residual_data[41]
    DIRECTION OUTPUT ;
    USE SIGNAL ;
    PORT
      LAYER M4 ;
        RECT  220.236 33.264 220.32 33.288 ;
    END
  END residual_data[41]
  PIN residual_data[42]
    DIRECTION OUTPUT ;
    USE SIGNAL ;
    PORT
      LAYER M4 ;
        RECT  220.236 33.36 220.32 33.384 ;
    END
  END residual_data[42]
  PIN residual_data[43]
    DIRECTION OUTPUT ;
    USE SIGNAL ;
    PORT
      LAYER M4 ;
        RECT  220.236 33.456 220.32 33.48 ;
    END
  END residual_data[43]
  PIN residual_data[44]
    DIRECTION OUTPUT ;
    USE SIGNAL ;
    PORT
      LAYER M4 ;
        RECT  220.236 33.552 220.32 33.576 ;
    END
  END residual_data[44]
  PIN residual_data[45]
    DIRECTION OUTPUT ;
    USE SIGNAL ;
    PORT
      LAYER M4 ;
        RECT  220.236 33.648 220.32 33.672 ;
    END
  END residual_data[45]
  PIN residual_data[46]
    DIRECTION OUTPUT ;
    USE SIGNAL ;
    PORT
      LAYER M4 ;
        RECT  220.236 33.744 220.32 33.768 ;
    END
  END residual_data[46]
  PIN residual_data[47]
    DIRECTION OUTPUT ;
    USE SIGNAL ;
    PORT
      LAYER M4 ;
        RECT  220.236 33.84 220.32 33.864 ;
    END
  END residual_data[47]
  PIN residual_data[48]
    DIRECTION OUTPUT ;
    USE SIGNAL ;
    PORT
      LAYER M4 ;
        RECT  220.236 33.936 220.32 33.96 ;
    END
  END residual_data[48]
  PIN residual_data[49]
    DIRECTION OUTPUT ;
    USE SIGNAL ;
    PORT
      LAYER M4 ;
        RECT  220.236 34.032 220.32 34.056 ;
    END
  END residual_data[49]
  PIN residual_data[4]
    DIRECTION OUTPUT ;
    USE SIGNAL ;
    PORT
      LAYER M4 ;
        RECT  220.236 29.712 220.32 29.736 ;
    END
  END residual_data[4]
  PIN residual_data[50]
    DIRECTION OUTPUT ;
    USE SIGNAL ;
    PORT
      LAYER M4 ;
        RECT  220.236 34.128 220.32 34.152 ;
    END
  END residual_data[50]
  PIN residual_data[51]
    DIRECTION OUTPUT ;
    USE SIGNAL ;
    PORT
      LAYER M4 ;
        RECT  220.236 34.224 220.32 34.248 ;
    END
  END residual_data[51]
  PIN residual_data[52]
    DIRECTION OUTPUT ;
    USE SIGNAL ;
    PORT
      LAYER M4 ;
        RECT  220.236 34.32 220.32 34.344 ;
    END
  END residual_data[52]
  PIN residual_data[53]
    DIRECTION OUTPUT ;
    USE SIGNAL ;
    PORT
      LAYER M4 ;
        RECT  220.236 34.416 220.32 34.44 ;
    END
  END residual_data[53]
  PIN residual_data[54]
    DIRECTION OUTPUT ;
    USE SIGNAL ;
    PORT
      LAYER M4 ;
        RECT  220.236 34.512 220.32 34.536 ;
    END
  END residual_data[54]
  PIN residual_data[55]
    DIRECTION OUTPUT ;
    USE SIGNAL ;
    PORT
      LAYER M4 ;
        RECT  220.236 34.608 220.32 34.632 ;
    END
  END residual_data[55]
  PIN residual_data[56]
    DIRECTION OUTPUT ;
    USE SIGNAL ;
    PORT
      LAYER M4 ;
        RECT  220.236 34.704 220.32 34.728 ;
    END
  END residual_data[56]
  PIN residual_data[57]
    DIRECTION OUTPUT ;
    USE SIGNAL ;
    PORT
      LAYER M4 ;
        RECT  220.236 34.8 220.32 34.824 ;
    END
  END residual_data[57]
  PIN residual_data[58]
    DIRECTION OUTPUT ;
    USE SIGNAL ;
    PORT
      LAYER M4 ;
        RECT  220.236 34.896 220.32 34.92 ;
    END
  END residual_data[58]
  PIN residual_data[59]
    DIRECTION OUTPUT ;
    USE SIGNAL ;
    PORT
      LAYER M4 ;
        RECT  220.236 34.992 220.32 35.016 ;
    END
  END residual_data[59]
  PIN residual_data[5]
    DIRECTION OUTPUT ;
    USE SIGNAL ;
    PORT
      LAYER M4 ;
        RECT  220.236 29.808 220.32 29.832 ;
    END
  END residual_data[5]
  PIN residual_data[60]
    DIRECTION OUTPUT ;
    USE SIGNAL ;
    PORT
      LAYER M4 ;
        RECT  220.236 35.088 220.32 35.112 ;
    END
  END residual_data[60]
  PIN residual_data[61]
    DIRECTION OUTPUT ;
    USE SIGNAL ;
    PORT
      LAYER M4 ;
        RECT  220.236 35.184 220.32 35.208 ;
    END
  END residual_data[61]
  PIN residual_data[62]
    DIRECTION OUTPUT ;
    USE SIGNAL ;
    PORT
      LAYER M4 ;
        RECT  220.236 35.28 220.32 35.304 ;
    END
  END residual_data[62]
  PIN residual_data[63]
    DIRECTION OUTPUT ;
    USE SIGNAL ;
    PORT
      LAYER M4 ;
        RECT  220.236 35.376 220.32 35.4 ;
    END
  END residual_data[63]
  PIN residual_data[64]
    DIRECTION OUTPUT ;
    USE SIGNAL ;
    PORT
      LAYER M4 ;
        RECT  220.236 35.472 220.32 35.496 ;
    END
  END residual_data[64]
  PIN residual_data[65]
    DIRECTION OUTPUT ;
    USE SIGNAL ;
    PORT
      LAYER M4 ;
        RECT  220.236 35.568 220.32 35.592 ;
    END
  END residual_data[65]
  PIN residual_data[66]
    DIRECTION OUTPUT ;
    USE SIGNAL ;
    PORT
      LAYER M4 ;
        RECT  220.236 35.664 220.32 35.688 ;
    END
  END residual_data[66]
  PIN residual_data[67]
    DIRECTION OUTPUT ;
    USE SIGNAL ;
    PORT
      LAYER M4 ;
        RECT  220.236 35.76 220.32 35.784 ;
    END
  END residual_data[67]
  PIN residual_data[68]
    DIRECTION OUTPUT ;
    USE SIGNAL ;
    PORT
      LAYER M4 ;
        RECT  220.236 35.856 220.32 35.88 ;
    END
  END residual_data[68]
  PIN residual_data[69]
    DIRECTION OUTPUT ;
    USE SIGNAL ;
    PORT
      LAYER M4 ;
        RECT  220.236 35.952 220.32 35.976 ;
    END
  END residual_data[69]
  PIN residual_data[6]
    DIRECTION OUTPUT ;
    USE SIGNAL ;
    PORT
      LAYER M4 ;
        RECT  220.236 29.904 220.32 29.928 ;
    END
  END residual_data[6]
  PIN residual_data[70]
    DIRECTION OUTPUT ;
    USE SIGNAL ;
    PORT
      LAYER M4 ;
        RECT  220.236 36.048 220.32 36.072 ;
    END
  END residual_data[70]
  PIN residual_data[71]
    DIRECTION OUTPUT ;
    USE SIGNAL ;
    PORT
      LAYER M4 ;
        RECT  220.236 36.144 220.32 36.168 ;
    END
  END residual_data[71]
  PIN residual_data[72]
    DIRECTION OUTPUT ;
    USE SIGNAL ;
    PORT
      LAYER M4 ;
        RECT  220.236 36.24 220.32 36.264 ;
    END
  END residual_data[72]
  PIN residual_data[73]
    DIRECTION OUTPUT ;
    USE SIGNAL ;
    PORT
      LAYER M4 ;
        RECT  220.236 36.336 220.32 36.36 ;
    END
  END residual_data[73]
  PIN residual_data[74]
    DIRECTION OUTPUT ;
    USE SIGNAL ;
    PORT
      LAYER M4 ;
        RECT  220.236 36.432 220.32 36.456 ;
    END
  END residual_data[74]
  PIN residual_data[75]
    DIRECTION OUTPUT ;
    USE SIGNAL ;
    PORT
      LAYER M4 ;
        RECT  220.236 36.528 220.32 36.552 ;
    END
  END residual_data[75]
  PIN residual_data[76]
    DIRECTION OUTPUT ;
    USE SIGNAL ;
    PORT
      LAYER M4 ;
        RECT  220.236 36.624 220.32 36.648 ;
    END
  END residual_data[76]
  PIN residual_data[77]
    DIRECTION OUTPUT ;
    USE SIGNAL ;
    PORT
      LAYER M4 ;
        RECT  220.236 36.72 220.32 36.744 ;
    END
  END residual_data[77]
  PIN residual_data[78]
    DIRECTION OUTPUT ;
    USE SIGNAL ;
    PORT
      LAYER M4 ;
        RECT  220.236 36.816 220.32 36.84 ;
    END
  END residual_data[78]
  PIN residual_data[79]
    DIRECTION OUTPUT ;
    USE SIGNAL ;
    PORT
      LAYER M4 ;
        RECT  220.236 36.912 220.32 36.936 ;
    END
  END residual_data[79]
  PIN residual_data[7]
    DIRECTION OUTPUT ;
    USE SIGNAL ;
    PORT
      LAYER M4 ;
        RECT  220.236 30 220.32 30.024 ;
    END
  END residual_data[7]
  PIN residual_data[80]
    DIRECTION OUTPUT ;
    USE SIGNAL ;
    PORT
      LAYER M4 ;
        RECT  220.236 37.008 220.32 37.032 ;
    END
  END residual_data[80]
  PIN residual_data[81]
    DIRECTION OUTPUT ;
    USE SIGNAL ;
    PORT
      LAYER M4 ;
        RECT  220.236 37.104 220.32 37.128 ;
    END
  END residual_data[81]
  PIN residual_data[82]
    DIRECTION OUTPUT ;
    USE SIGNAL ;
    PORT
      LAYER M4 ;
        RECT  220.236 37.2 220.32 37.224 ;
    END
  END residual_data[82]
  PIN residual_data[83]
    DIRECTION OUTPUT ;
    USE SIGNAL ;
    PORT
      LAYER M4 ;
        RECT  220.236 37.296 220.32 37.32 ;
    END
  END residual_data[83]
  PIN residual_data[84]
    DIRECTION OUTPUT ;
    USE SIGNAL ;
    PORT
      LAYER M4 ;
        RECT  220.236 37.392 220.32 37.416 ;
    END
  END residual_data[84]
  PIN residual_data[85]
    DIRECTION OUTPUT ;
    USE SIGNAL ;
    PORT
      LAYER M4 ;
        RECT  220.236 37.488 220.32 37.512 ;
    END
  END residual_data[85]
  PIN residual_data[86]
    DIRECTION OUTPUT ;
    USE SIGNAL ;
    PORT
      LAYER M4 ;
        RECT  220.236 37.584 220.32 37.608 ;
    END
  END residual_data[86]
  PIN residual_data[87]
    DIRECTION OUTPUT ;
    USE SIGNAL ;
    PORT
      LAYER M4 ;
        RECT  220.236 37.68 220.32 37.704 ;
    END
  END residual_data[87]
  PIN residual_data[88]
    DIRECTION OUTPUT ;
    USE SIGNAL ;
    PORT
      LAYER M4 ;
        RECT  220.236 37.776 220.32 37.8 ;
    END
  END residual_data[88]
  PIN residual_data[89]
    DIRECTION OUTPUT ;
    USE SIGNAL ;
    PORT
      LAYER M4 ;
        RECT  220.236 37.872 220.32 37.896 ;
    END
  END residual_data[89]
  PIN residual_data[8]
    DIRECTION OUTPUT ;
    USE SIGNAL ;
    PORT
      LAYER M4 ;
        RECT  220.236 30.096 220.32 30.12 ;
    END
  END residual_data[8]
  PIN residual_data[90]
    DIRECTION OUTPUT ;
    USE SIGNAL ;
    PORT
      LAYER M4 ;
        RECT  220.236 37.968 220.32 37.992 ;
    END
  END residual_data[90]
  PIN residual_data[91]
    DIRECTION OUTPUT ;
    USE SIGNAL ;
    PORT
      LAYER M4 ;
        RECT  220.236 38.064 220.32 38.088 ;
    END
  END residual_data[91]
  PIN residual_data[92]
    DIRECTION OUTPUT ;
    USE SIGNAL ;
    PORT
      LAYER M4 ;
        RECT  220.236 38.16 220.32 38.184 ;
    END
  END residual_data[92]
  PIN residual_data[93]
    DIRECTION OUTPUT ;
    USE SIGNAL ;
    PORT
      LAYER M4 ;
        RECT  220.236 38.256 220.32 38.28 ;
    END
  END residual_data[93]
  PIN residual_data[94]
    DIRECTION OUTPUT ;
    USE SIGNAL ;
    PORT
      LAYER M4 ;
        RECT  220.236 39.12 220.32 39.144 ;
    END
  END residual_data[94]
  PIN residual_data[95]
    DIRECTION OUTPUT ;
    USE SIGNAL ;
    PORT
      LAYER M4 ;
        RECT  220.236 39.216 220.32 39.24 ;
    END
  END residual_data[95]
  PIN residual_data[96]
    DIRECTION OUTPUT ;
    USE SIGNAL ;
    PORT
      LAYER M4 ;
        RECT  220.236 39.312 220.32 39.336 ;
    END
  END residual_data[96]
  PIN residual_data[97]
    DIRECTION OUTPUT ;
    USE SIGNAL ;
    PORT
      LAYER M4 ;
        RECT  220.236 39.408 220.32 39.432 ;
    END
  END residual_data[97]
  PIN residual_data[98]
    DIRECTION OUTPUT ;
    USE SIGNAL ;
    PORT
      LAYER M4 ;
        RECT  220.236 39.504 220.32 39.528 ;
    END
  END residual_data[98]
  PIN residual_data[99]
    DIRECTION OUTPUT ;
    USE SIGNAL ;
    PORT
      LAYER M4 ;
        RECT  220.236 39.6 220.32 39.624 ;
    END
  END residual_data[99]
  PIN residual_data[9]
    DIRECTION OUTPUT ;
    USE SIGNAL ;
    PORT
      LAYER M4 ;
        RECT  220.236 30.192 220.32 30.216 ;
    END
  END residual_data[9]
  PIN rst_n
    DIRECTION INPUT ;
    USE SIGNAL ;
    PORT
      LAYER M5 ;
        RECT  202.032 125.196 202.056 125.28 ;
    END
  END rst_n
  PIN write_data[0]
    DIRECTION INPUT ;
    USE SIGNAL ;
    PORT
      LAYER M4 ;
        RECT  0 54.672 0.084 54.696 ;
    END
  END write_data[0]
  PIN write_data[100]
    DIRECTION INPUT ;
    USE SIGNAL ;
    PORT
      LAYER M4 ;
        RECT  0 64.272 0.084 64.296 ;
    END
  END write_data[100]
  PIN write_data[101]
    DIRECTION INPUT ;
    USE SIGNAL ;
    PORT
      LAYER M4 ;
        RECT  0 64.368 0.084 64.392 ;
    END
  END write_data[101]
  PIN write_data[102]
    DIRECTION INPUT ;
    USE SIGNAL ;
    PORT
      LAYER M4 ;
        RECT  0 64.464 0.084 64.488 ;
    END
  END write_data[102]
  PIN write_data[103]
    DIRECTION INPUT ;
    USE SIGNAL ;
    PORT
      LAYER M4 ;
        RECT  0 64.56 0.084 64.584 ;
    END
  END write_data[103]
  PIN write_data[104]
    DIRECTION INPUT ;
    USE SIGNAL ;
    PORT
      LAYER M4 ;
        RECT  0 64.656 0.084 64.68 ;
    END
  END write_data[104]
  PIN write_data[105]
    DIRECTION INPUT ;
    USE SIGNAL ;
    PORT
      LAYER M4 ;
        RECT  0 64.752 0.084 64.776 ;
    END
  END write_data[105]
  PIN write_data[106]
    DIRECTION INPUT ;
    USE SIGNAL ;
    PORT
      LAYER M4 ;
        RECT  0 64.848 0.084 64.872 ;
    END
  END write_data[106]
  PIN write_data[107]
    DIRECTION INPUT ;
    USE SIGNAL ;
    PORT
      LAYER M4 ;
        RECT  0 64.944 0.084 64.968 ;
    END
  END write_data[107]
  PIN write_data[108]
    DIRECTION INPUT ;
    USE SIGNAL ;
    PORT
      LAYER M4 ;
        RECT  0 65.04 0.084 65.064 ;
    END
  END write_data[108]
  PIN write_data[109]
    DIRECTION INPUT ;
    USE SIGNAL ;
    PORT
      LAYER M4 ;
        RECT  0 65.136 0.084 65.16 ;
    END
  END write_data[109]
  PIN write_data[10]
    DIRECTION INPUT ;
    USE SIGNAL ;
    PORT
      LAYER M4 ;
        RECT  0 55.632 0.084 55.656 ;
    END
  END write_data[10]
  PIN write_data[110]
    DIRECTION INPUT ;
    USE SIGNAL ;
    PORT
      LAYER M4 ;
        RECT  0 65.232 0.084 65.256 ;
    END
  END write_data[110]
  PIN write_data[111]
    DIRECTION INPUT ;
    USE SIGNAL ;
    PORT
      LAYER M4 ;
        RECT  0 65.328 0.084 65.352 ;
    END
  END write_data[111]
  PIN write_data[112]
    DIRECTION INPUT ;
    USE SIGNAL ;
    PORT
      LAYER M4 ;
        RECT  0 65.424 0.084 65.448 ;
    END
  END write_data[112]
  PIN write_data[113]
    DIRECTION INPUT ;
    USE SIGNAL ;
    PORT
      LAYER M4 ;
        RECT  0 65.52 0.084 65.544 ;
    END
  END write_data[113]
  PIN write_data[114]
    DIRECTION INPUT ;
    USE SIGNAL ;
    PORT
      LAYER M4 ;
        RECT  0 65.616 0.084 65.64 ;
    END
  END write_data[114]
  PIN write_data[115]
    DIRECTION INPUT ;
    USE SIGNAL ;
    PORT
      LAYER M4 ;
        RECT  0 65.712 0.084 65.736 ;
    END
  END write_data[115]
  PIN write_data[116]
    DIRECTION INPUT ;
    USE SIGNAL ;
    PORT
      LAYER M4 ;
        RECT  0 65.808 0.084 65.832 ;
    END
  END write_data[116]
  PIN write_data[117]
    DIRECTION INPUT ;
    USE SIGNAL ;
    PORT
      LAYER M4 ;
        RECT  0 65.904 0.084 65.928 ;
    END
  END write_data[117]
  PIN write_data[118]
    DIRECTION INPUT ;
    USE SIGNAL ;
    PORT
      LAYER M4 ;
        RECT  0 66 0.084 66.024 ;
    END
  END write_data[118]
  PIN write_data[119]
    DIRECTION INPUT ;
    USE SIGNAL ;
    PORT
      LAYER M4 ;
        RECT  0 66.096 0.084 66.12 ;
    END
  END write_data[119]
  PIN write_data[11]
    DIRECTION INPUT ;
    USE SIGNAL ;
    PORT
      LAYER M4 ;
        RECT  0 55.728 0.084 55.752 ;
    END
  END write_data[11]
  PIN write_data[120]
    DIRECTION INPUT ;
    USE SIGNAL ;
    PORT
      LAYER M4 ;
        RECT  0 66.192 0.084 66.216 ;
    END
  END write_data[120]
  PIN write_data[121]
    DIRECTION INPUT ;
    USE SIGNAL ;
    PORT
      LAYER M4 ;
        RECT  0 66.288 0.084 66.312 ;
    END
  END write_data[121]
  PIN write_data[122]
    DIRECTION INPUT ;
    USE SIGNAL ;
    PORT
      LAYER M4 ;
        RECT  0 66.384 0.084 66.408 ;
    END
  END write_data[122]
  PIN write_data[123]
    DIRECTION INPUT ;
    USE SIGNAL ;
    PORT
      LAYER M4 ;
        RECT  0 66.48 0.084 66.504 ;
    END
  END write_data[123]
  PIN write_data[124]
    DIRECTION INPUT ;
    USE SIGNAL ;
    PORT
      LAYER M4 ;
        RECT  0 66.576 0.084 66.6 ;
    END
  END write_data[124]
  PIN write_data[125]
    DIRECTION INPUT ;
    USE SIGNAL ;
    PORT
      LAYER M4 ;
        RECT  0 66.672 0.084 66.696 ;
    END
  END write_data[125]
  PIN write_data[126]
    DIRECTION INPUT ;
    USE SIGNAL ;
    PORT
      LAYER M4 ;
        RECT  0 66.768 0.084 66.792 ;
    END
  END write_data[126]
  PIN write_data[127]
    DIRECTION INPUT ;
    USE SIGNAL ;
    PORT
      LAYER M4 ;
        RECT  0 66.864 0.084 66.888 ;
    END
  END write_data[127]
  PIN write_data[128]
    DIRECTION INPUT ;
    USE SIGNAL ;
    PORT
      LAYER M4 ;
        RECT  0 35.472 0.084 35.496 ;
    END
  END write_data[128]
  PIN write_data[129]
    DIRECTION INPUT ;
    USE SIGNAL ;
    PORT
      LAYER M4 ;
        RECT  0 35.568 0.084 35.592 ;
    END
  END write_data[129]
  PIN write_data[12]
    DIRECTION INPUT ;
    USE SIGNAL ;
    PORT
      LAYER M4 ;
        RECT  0 55.824 0.084 55.848 ;
    END
  END write_data[12]
  PIN write_data[130]
    DIRECTION INPUT ;
    USE SIGNAL ;
    PORT
      LAYER M4 ;
        RECT  0 35.664 0.084 35.688 ;
    END
  END write_data[130]
  PIN write_data[131]
    DIRECTION INPUT ;
    USE SIGNAL ;
    PORT
      LAYER M4 ;
        RECT  0 35.76 0.084 35.784 ;
    END
  END write_data[131]
  PIN write_data[132]
    DIRECTION INPUT ;
    USE SIGNAL ;
    PORT
      LAYER M4 ;
        RECT  0 35.856 0.084 35.88 ;
    END
  END write_data[132]
  PIN write_data[133]
    DIRECTION INPUT ;
    USE SIGNAL ;
    PORT
      LAYER M4 ;
        RECT  0 35.952 0.084 35.976 ;
    END
  END write_data[133]
  PIN write_data[134]
    DIRECTION INPUT ;
    USE SIGNAL ;
    PORT
      LAYER M4 ;
        RECT  0 36.048 0.084 36.072 ;
    END
  END write_data[134]
  PIN write_data[135]
    DIRECTION INPUT ;
    USE SIGNAL ;
    PORT
      LAYER M4 ;
        RECT  0 36.144 0.084 36.168 ;
    END
  END write_data[135]
  PIN write_data[136]
    DIRECTION INPUT ;
    USE SIGNAL ;
    PORT
      LAYER M4 ;
        RECT  0 36.24 0.084 36.264 ;
    END
  END write_data[136]
  PIN write_data[137]
    DIRECTION INPUT ;
    USE SIGNAL ;
    PORT
      LAYER M4 ;
        RECT  0 36.336 0.084 36.36 ;
    END
  END write_data[137]
  PIN write_data[138]
    DIRECTION INPUT ;
    USE SIGNAL ;
    PORT
      LAYER M4 ;
        RECT  0 36.432 0.084 36.456 ;
    END
  END write_data[138]
  PIN write_data[139]
    DIRECTION INPUT ;
    USE SIGNAL ;
    PORT
      LAYER M4 ;
        RECT  0 36.528 0.084 36.552 ;
    END
  END write_data[139]
  PIN write_data[13]
    DIRECTION INPUT ;
    USE SIGNAL ;
    PORT
      LAYER M4 ;
        RECT  0 55.92 0.084 55.944 ;
    END
  END write_data[13]
  PIN write_data[140]
    DIRECTION INPUT ;
    USE SIGNAL ;
    PORT
      LAYER M4 ;
        RECT  0 36.624 0.084 36.648 ;
    END
  END write_data[140]
  PIN write_data[141]
    DIRECTION INPUT ;
    USE SIGNAL ;
    PORT
      LAYER M4 ;
        RECT  0 36.72 0.084 36.744 ;
    END
  END write_data[141]
  PIN write_data[142]
    DIRECTION INPUT ;
    USE SIGNAL ;
    PORT
      LAYER M4 ;
        RECT  0 36.816 0.084 36.84 ;
    END
  END write_data[142]
  PIN write_data[143]
    DIRECTION INPUT ;
    USE SIGNAL ;
    PORT
      LAYER M4 ;
        RECT  0 36.912 0.084 36.936 ;
    END
  END write_data[143]
  PIN write_data[144]
    DIRECTION INPUT ;
    USE SIGNAL ;
    PORT
      LAYER M4 ;
        RECT  0 37.008 0.084 37.032 ;
    END
  END write_data[144]
  PIN write_data[145]
    DIRECTION INPUT ;
    USE SIGNAL ;
    PORT
      LAYER M4 ;
        RECT  0 37.104 0.084 37.128 ;
    END
  END write_data[145]
  PIN write_data[146]
    DIRECTION INPUT ;
    USE SIGNAL ;
    PORT
      LAYER M4 ;
        RECT  0 37.2 0.084 37.224 ;
    END
  END write_data[146]
  PIN write_data[147]
    DIRECTION INPUT ;
    USE SIGNAL ;
    PORT
      LAYER M4 ;
        RECT  0 37.296 0.084 37.32 ;
    END
  END write_data[147]
  PIN write_data[148]
    DIRECTION INPUT ;
    USE SIGNAL ;
    PORT
      LAYER M4 ;
        RECT  0 37.392 0.084 37.416 ;
    END
  END write_data[148]
  PIN write_data[149]
    DIRECTION INPUT ;
    USE SIGNAL ;
    PORT
      LAYER M4 ;
        RECT  0 37.488 0.084 37.512 ;
    END
  END write_data[149]
  PIN write_data[14]
    DIRECTION INPUT ;
    USE SIGNAL ;
    PORT
      LAYER M4 ;
        RECT  0 56.016 0.084 56.04 ;
    END
  END write_data[14]
  PIN write_data[150]
    DIRECTION INPUT ;
    USE SIGNAL ;
    PORT
      LAYER M4 ;
        RECT  0 37.584 0.084 37.608 ;
    END
  END write_data[150]
  PIN write_data[151]
    DIRECTION INPUT ;
    USE SIGNAL ;
    PORT
      LAYER M4 ;
        RECT  0 37.68 0.084 37.704 ;
    END
  END write_data[151]
  PIN write_data[152]
    DIRECTION INPUT ;
    USE SIGNAL ;
    PORT
      LAYER M4 ;
        RECT  0 37.776 0.084 37.8 ;
    END
  END write_data[152]
  PIN write_data[153]
    DIRECTION INPUT ;
    USE SIGNAL ;
    PORT
      LAYER M4 ;
        RECT  0 37.872 0.084 37.896 ;
    END
  END write_data[153]
  PIN write_data[154]
    DIRECTION INPUT ;
    USE SIGNAL ;
    PORT
      LAYER M4 ;
        RECT  0 37.968 0.084 37.992 ;
    END
  END write_data[154]
  PIN write_data[155]
    DIRECTION INPUT ;
    USE SIGNAL ;
    PORT
      LAYER M4 ;
        RECT  0 38.064 0.084 38.088 ;
    END
  END write_data[155]
  PIN write_data[156]
    DIRECTION INPUT ;
    USE SIGNAL ;
    PORT
      LAYER M4 ;
        RECT  0 38.16 0.084 38.184 ;
    END
  END write_data[156]
  PIN write_data[157]
    DIRECTION INPUT ;
    USE SIGNAL ;
    PORT
      LAYER M4 ;
        RECT  0 38.256 0.084 38.28 ;
    END
  END write_data[157]
  PIN write_data[158]
    DIRECTION INPUT ;
    USE SIGNAL ;
    PORT
      LAYER M4 ;
        RECT  0 38.352 0.084 38.376 ;
    END
  END write_data[158]
  PIN write_data[159]
    DIRECTION INPUT ;
    USE SIGNAL ;
    PORT
      LAYER M4 ;
        RECT  0 38.448 0.084 38.472 ;
    END
  END write_data[159]
  PIN write_data[15]
    DIRECTION INPUT ;
    USE SIGNAL ;
    PORT
      LAYER M4 ;
        RECT  0 56.112 0.084 56.136 ;
    END
  END write_data[15]
  PIN write_data[160]
    DIRECTION INPUT ;
    USE SIGNAL ;
    PORT
      LAYER M4 ;
        RECT  0 29.328 0.084 29.352 ;
    END
  END write_data[160]
  PIN write_data[161]
    DIRECTION INPUT ;
    USE SIGNAL ;
    PORT
      LAYER M4 ;
        RECT  0 29.424 0.084 29.448 ;
    END
  END write_data[161]
  PIN write_data[162]
    DIRECTION INPUT ;
    USE SIGNAL ;
    PORT
      LAYER M4 ;
        RECT  0 29.52 0.084 29.544 ;
    END
  END write_data[162]
  PIN write_data[163]
    DIRECTION INPUT ;
    USE SIGNAL ;
    PORT
      LAYER M4 ;
        RECT  0 29.616 0.084 29.64 ;
    END
  END write_data[163]
  PIN write_data[164]
    DIRECTION INPUT ;
    USE SIGNAL ;
    PORT
      LAYER M4 ;
        RECT  0 29.712 0.084 29.736 ;
    END
  END write_data[164]
  PIN write_data[165]
    DIRECTION INPUT ;
    USE SIGNAL ;
    PORT
      LAYER M4 ;
        RECT  0 29.808 0.084 29.832 ;
    END
  END write_data[165]
  PIN write_data[166]
    DIRECTION INPUT ;
    USE SIGNAL ;
    PORT
      LAYER M4 ;
        RECT  0 29.904 0.084 29.928 ;
    END
  END write_data[166]
  PIN write_data[167]
    DIRECTION INPUT ;
    USE SIGNAL ;
    PORT
      LAYER M4 ;
        RECT  0 30 0.084 30.024 ;
    END
  END write_data[167]
  PIN write_data[168]
    DIRECTION INPUT ;
    USE SIGNAL ;
    PORT
      LAYER M4 ;
        RECT  0 30.096 0.084 30.12 ;
    END
  END write_data[168]
  PIN write_data[169]
    DIRECTION INPUT ;
    USE SIGNAL ;
    PORT
      LAYER M4 ;
        RECT  0 30.192 0.084 30.216 ;
    END
  END write_data[169]
  PIN write_data[16]
    DIRECTION INPUT ;
    USE SIGNAL ;
    PORT
      LAYER M4 ;
        RECT  0 56.208 0.084 56.232 ;
    END
  END write_data[16]
  PIN write_data[170]
    DIRECTION INPUT ;
    USE SIGNAL ;
    PORT
      LAYER M4 ;
        RECT  0 30.288 0.084 30.312 ;
    END
  END write_data[170]
  PIN write_data[171]
    DIRECTION INPUT ;
    USE SIGNAL ;
    PORT
      LAYER M4 ;
        RECT  0 30.384 0.084 30.408 ;
    END
  END write_data[171]
  PIN write_data[172]
    DIRECTION INPUT ;
    USE SIGNAL ;
    PORT
      LAYER M4 ;
        RECT  0 30.48 0.084 30.504 ;
    END
  END write_data[172]
  PIN write_data[173]
    DIRECTION INPUT ;
    USE SIGNAL ;
    PORT
      LAYER M4 ;
        RECT  0 30.576 0.084 30.6 ;
    END
  END write_data[173]
  PIN write_data[174]
    DIRECTION INPUT ;
    USE SIGNAL ;
    PORT
      LAYER M4 ;
        RECT  0 30.672 0.084 30.696 ;
    END
  END write_data[174]
  PIN write_data[175]
    DIRECTION INPUT ;
    USE SIGNAL ;
    PORT
      LAYER M4 ;
        RECT  0 30.768 0.084 30.792 ;
    END
  END write_data[175]
  PIN write_data[176]
    DIRECTION INPUT ;
    USE SIGNAL ;
    PORT
      LAYER M4 ;
        RECT  0 30.864 0.084 30.888 ;
    END
  END write_data[176]
  PIN write_data[177]
    DIRECTION INPUT ;
    USE SIGNAL ;
    PORT
      LAYER M4 ;
        RECT  0 30.96 0.084 30.984 ;
    END
  END write_data[177]
  PIN write_data[178]
    DIRECTION INPUT ;
    USE SIGNAL ;
    PORT
      LAYER M4 ;
        RECT  0 31.056 0.084 31.08 ;
    END
  END write_data[178]
  PIN write_data[179]
    DIRECTION INPUT ;
    USE SIGNAL ;
    PORT
      LAYER M4 ;
        RECT  0 31.152 0.084 31.176 ;
    END
  END write_data[179]
  PIN write_data[17]
    DIRECTION INPUT ;
    USE SIGNAL ;
    PORT
      LAYER M4 ;
        RECT  0 56.304 0.084 56.328 ;
    END
  END write_data[17]
  PIN write_data[180]
    DIRECTION INPUT ;
    USE SIGNAL ;
    PORT
      LAYER M4 ;
        RECT  0 31.248 0.084 31.272 ;
    END
  END write_data[180]
  PIN write_data[181]
    DIRECTION INPUT ;
    USE SIGNAL ;
    PORT
      LAYER M4 ;
        RECT  0 31.344 0.084 31.368 ;
    END
  END write_data[181]
  PIN write_data[182]
    DIRECTION INPUT ;
    USE SIGNAL ;
    PORT
      LAYER M4 ;
        RECT  0 31.44 0.084 31.464 ;
    END
  END write_data[182]
  PIN write_data[183]
    DIRECTION INPUT ;
    USE SIGNAL ;
    PORT
      LAYER M4 ;
        RECT  0 31.536 0.084 31.56 ;
    END
  END write_data[183]
  PIN write_data[184]
    DIRECTION INPUT ;
    USE SIGNAL ;
    PORT
      LAYER M4 ;
        RECT  0 31.632 0.084 31.656 ;
    END
  END write_data[184]
  PIN write_data[185]
    DIRECTION INPUT ;
    USE SIGNAL ;
    PORT
      LAYER M4 ;
        RECT  0 31.728 0.084 31.752 ;
    END
  END write_data[185]
  PIN write_data[186]
    DIRECTION INPUT ;
    USE SIGNAL ;
    PORT
      LAYER M4 ;
        RECT  0 31.824 0.084 31.848 ;
    END
  END write_data[186]
  PIN write_data[187]
    DIRECTION INPUT ;
    USE SIGNAL ;
    PORT
      LAYER M4 ;
        RECT  0 31.92 0.084 31.944 ;
    END
  END write_data[187]
  PIN write_data[188]
    DIRECTION INPUT ;
    USE SIGNAL ;
    PORT
      LAYER M4 ;
        RECT  0 32.016 0.084 32.04 ;
    END
  END write_data[188]
  PIN write_data[189]
    DIRECTION INPUT ;
    USE SIGNAL ;
    PORT
      LAYER M4 ;
        RECT  0 32.112 0.084 32.136 ;
    END
  END write_data[189]
  PIN write_data[18]
    DIRECTION INPUT ;
    USE SIGNAL ;
    PORT
      LAYER M4 ;
        RECT  0 56.4 0.084 56.424 ;
    END
  END write_data[18]
  PIN write_data[190]
    DIRECTION INPUT ;
    USE SIGNAL ;
    PORT
      LAYER M4 ;
        RECT  0 32.208 0.084 32.232 ;
    END
  END write_data[190]
  PIN write_data[191]
    DIRECTION INPUT ;
    USE SIGNAL ;
    PORT
      LAYER M4 ;
        RECT  0 32.304 0.084 32.328 ;
    END
  END write_data[191]
  PIN write_data[192]
    DIRECTION INPUT ;
    USE SIGNAL ;
    PORT
      LAYER M4 ;
        RECT  0 32.4 0.084 32.424 ;
    END
  END write_data[192]
  PIN write_data[193]
    DIRECTION INPUT ;
    USE SIGNAL ;
    PORT
      LAYER M4 ;
        RECT  0 32.496 0.084 32.52 ;
    END
  END write_data[193]
  PIN write_data[194]
    DIRECTION INPUT ;
    USE SIGNAL ;
    PORT
      LAYER M4 ;
        RECT  0 32.592 0.084 32.616 ;
    END
  END write_data[194]
  PIN write_data[195]
    DIRECTION INPUT ;
    USE SIGNAL ;
    PORT
      LAYER M4 ;
        RECT  0 32.688 0.084 32.712 ;
    END
  END write_data[195]
  PIN write_data[196]
    DIRECTION INPUT ;
    USE SIGNAL ;
    PORT
      LAYER M4 ;
        RECT  0 32.784 0.084 32.808 ;
    END
  END write_data[196]
  PIN write_data[197]
    DIRECTION INPUT ;
    USE SIGNAL ;
    PORT
      LAYER M4 ;
        RECT  0 32.88 0.084 32.904 ;
    END
  END write_data[197]
  PIN write_data[198]
    DIRECTION INPUT ;
    USE SIGNAL ;
    PORT
      LAYER M4 ;
        RECT  0 32.976 0.084 33 ;
    END
  END write_data[198]
  PIN write_data[199]
    DIRECTION INPUT ;
    USE SIGNAL ;
    PORT
      LAYER M4 ;
        RECT  0 33.072 0.084 33.096 ;
    END
  END write_data[199]
  PIN write_data[19]
    DIRECTION INPUT ;
    USE SIGNAL ;
    PORT
      LAYER M4 ;
        RECT  0 56.496 0.084 56.52 ;
    END
  END write_data[19]
  PIN write_data[1]
    DIRECTION INPUT ;
    USE SIGNAL ;
    PORT
      LAYER M4 ;
        RECT  0 54.768 0.084 54.792 ;
    END
  END write_data[1]
  PIN write_data[200]
    DIRECTION INPUT ;
    USE SIGNAL ;
    PORT
      LAYER M4 ;
        RECT  0 33.168 0.084 33.192 ;
    END
  END write_data[200]
  PIN write_data[201]
    DIRECTION INPUT ;
    USE SIGNAL ;
    PORT
      LAYER M4 ;
        RECT  0 33.264 0.084 33.288 ;
    END
  END write_data[201]
  PIN write_data[202]
    DIRECTION INPUT ;
    USE SIGNAL ;
    PORT
      LAYER M4 ;
        RECT  0 33.36 0.084 33.384 ;
    END
  END write_data[202]
  PIN write_data[203]
    DIRECTION INPUT ;
    USE SIGNAL ;
    PORT
      LAYER M4 ;
        RECT  0 33.456 0.084 33.48 ;
    END
  END write_data[203]
  PIN write_data[204]
    DIRECTION INPUT ;
    USE SIGNAL ;
    PORT
      LAYER M4 ;
        RECT  0 33.552 0.084 33.576 ;
    END
  END write_data[204]
  PIN write_data[205]
    DIRECTION INPUT ;
    USE SIGNAL ;
    PORT
      LAYER M4 ;
        RECT  0 33.648 0.084 33.672 ;
    END
  END write_data[205]
  PIN write_data[206]
    DIRECTION INPUT ;
    USE SIGNAL ;
    PORT
      LAYER M4 ;
        RECT  0 33.744 0.084 33.768 ;
    END
  END write_data[206]
  PIN write_data[207]
    DIRECTION INPUT ;
    USE SIGNAL ;
    PORT
      LAYER M4 ;
        RECT  0 33.84 0.084 33.864 ;
    END
  END write_data[207]
  PIN write_data[208]
    DIRECTION INPUT ;
    USE SIGNAL ;
    PORT
      LAYER M4 ;
        RECT  0 33.936 0.084 33.96 ;
    END
  END write_data[208]
  PIN write_data[209]
    DIRECTION INPUT ;
    USE SIGNAL ;
    PORT
      LAYER M4 ;
        RECT  0 34.032 0.084 34.056 ;
    END
  END write_data[209]
  PIN write_data[20]
    DIRECTION INPUT ;
    USE SIGNAL ;
    PORT
      LAYER M4 ;
        RECT  0 56.592 0.084 56.616 ;
    END
  END write_data[20]
  PIN write_data[210]
    DIRECTION INPUT ;
    USE SIGNAL ;
    PORT
      LAYER M4 ;
        RECT  0 34.128 0.084 34.152 ;
    END
  END write_data[210]
  PIN write_data[211]
    DIRECTION INPUT ;
    USE SIGNAL ;
    PORT
      LAYER M4 ;
        RECT  0 34.224 0.084 34.248 ;
    END
  END write_data[211]
  PIN write_data[212]
    DIRECTION INPUT ;
    USE SIGNAL ;
    PORT
      LAYER M4 ;
        RECT  0 34.32 0.084 34.344 ;
    END
  END write_data[212]
  PIN write_data[213]
    DIRECTION INPUT ;
    USE SIGNAL ;
    PORT
      LAYER M4 ;
        RECT  0 34.416 0.084 34.44 ;
    END
  END write_data[213]
  PIN write_data[214]
    DIRECTION INPUT ;
    USE SIGNAL ;
    PORT
      LAYER M4 ;
        RECT  0 34.512 0.084 34.536 ;
    END
  END write_data[214]
  PIN write_data[215]
    DIRECTION INPUT ;
    USE SIGNAL ;
    PORT
      LAYER M4 ;
        RECT  0 34.608 0.084 34.632 ;
    END
  END write_data[215]
  PIN write_data[216]
    DIRECTION INPUT ;
    USE SIGNAL ;
    PORT
      LAYER M4 ;
        RECT  0 34.704 0.084 34.728 ;
    END
  END write_data[216]
  PIN write_data[217]
    DIRECTION INPUT ;
    USE SIGNAL ;
    PORT
      LAYER M4 ;
        RECT  0 34.8 0.084 34.824 ;
    END
  END write_data[217]
  PIN write_data[218]
    DIRECTION INPUT ;
    USE SIGNAL ;
    PORT
      LAYER M4 ;
        RECT  0 34.896 0.084 34.92 ;
    END
  END write_data[218]
  PIN write_data[219]
    DIRECTION INPUT ;
    USE SIGNAL ;
    PORT
      LAYER M4 ;
        RECT  0 34.992 0.084 35.016 ;
    END
  END write_data[219]
  PIN write_data[21]
    DIRECTION INPUT ;
    USE SIGNAL ;
    PORT
      LAYER M4 ;
        RECT  0 56.688 0.084 56.712 ;
    END
  END write_data[21]
  PIN write_data[220]
    DIRECTION INPUT ;
    USE SIGNAL ;
    PORT
      LAYER M4 ;
        RECT  0 35.088 0.084 35.112 ;
    END
  END write_data[220]
  PIN write_data[221]
    DIRECTION INPUT ;
    USE SIGNAL ;
    PORT
      LAYER M4 ;
        RECT  0 35.184 0.084 35.208 ;
    END
  END write_data[221]
  PIN write_data[222]
    DIRECTION INPUT ;
    USE SIGNAL ;
    PORT
      LAYER M4 ;
        RECT  0 35.28 0.084 35.304 ;
    END
  END write_data[222]
  PIN write_data[223]
    DIRECTION INPUT ;
    USE SIGNAL ;
    PORT
      LAYER M4 ;
        RECT  0 35.376 0.084 35.4 ;
    END
  END write_data[223]
  PIN write_data[224]
    DIRECTION INPUT ;
    USE SIGNAL ;
    PORT
      LAYER M4 ;
        RECT  0 38.544 0.084 38.568 ;
    END
  END write_data[224]
  PIN write_data[225]
    DIRECTION INPUT ;
    USE SIGNAL ;
    PORT
      LAYER M4 ;
        RECT  0 38.64 0.084 38.664 ;
    END
  END write_data[225]
  PIN write_data[226]
    DIRECTION INPUT ;
    USE SIGNAL ;
    PORT
      LAYER M4 ;
        RECT  0 38.736 0.084 38.76 ;
    END
  END write_data[226]
  PIN write_data[227]
    DIRECTION INPUT ;
    USE SIGNAL ;
    PORT
      LAYER M4 ;
        RECT  0 38.832 0.084 38.856 ;
    END
  END write_data[227]
  PIN write_data[228]
    DIRECTION INPUT ;
    USE SIGNAL ;
    PORT
      LAYER M4 ;
        RECT  0 38.928 0.084 38.952 ;
    END
  END write_data[228]
  PIN write_data[229]
    DIRECTION INPUT ;
    USE SIGNAL ;
    PORT
      LAYER M4 ;
        RECT  0 39.024 0.084 39.048 ;
    END
  END write_data[229]
  PIN write_data[22]
    DIRECTION INPUT ;
    USE SIGNAL ;
    PORT
      LAYER M4 ;
        RECT  0 56.784 0.084 56.808 ;
    END
  END write_data[22]
  PIN write_data[230]
    DIRECTION INPUT ;
    USE SIGNAL ;
    PORT
      LAYER M4 ;
        RECT  0 39.12 0.084 39.144 ;
    END
  END write_data[230]
  PIN write_data[231]
    DIRECTION INPUT ;
    USE SIGNAL ;
    PORT
      LAYER M4 ;
        RECT  0 39.216 0.084 39.24 ;
    END
  END write_data[231]
  PIN write_data[232]
    DIRECTION INPUT ;
    USE SIGNAL ;
    PORT
      LAYER M4 ;
        RECT  0 39.312 0.084 39.336 ;
    END
  END write_data[232]
  PIN write_data[233]
    DIRECTION INPUT ;
    USE SIGNAL ;
    PORT
      LAYER M4 ;
        RECT  0 39.408 0.084 39.432 ;
    END
  END write_data[233]
  PIN write_data[234]
    DIRECTION INPUT ;
    USE SIGNAL ;
    PORT
      LAYER M4 ;
        RECT  0 39.504 0.084 39.528 ;
    END
  END write_data[234]
  PIN write_data[235]
    DIRECTION INPUT ;
    USE SIGNAL ;
    PORT
      LAYER M4 ;
        RECT  0 39.6 0.084 39.624 ;
    END
  END write_data[235]
  PIN write_data[236]
    DIRECTION INPUT ;
    USE SIGNAL ;
    PORT
      LAYER M4 ;
        RECT  0 39.696 0.084 39.72 ;
    END
  END write_data[236]
  PIN write_data[237]
    DIRECTION INPUT ;
    USE SIGNAL ;
    PORT
      LAYER M4 ;
        RECT  0 39.792 0.084 39.816 ;
    END
  END write_data[237]
  PIN write_data[238]
    DIRECTION INPUT ;
    USE SIGNAL ;
    PORT
      LAYER M4 ;
        RECT  0 39.888 0.084 39.912 ;
    END
  END write_data[238]
  PIN write_data[239]
    DIRECTION INPUT ;
    USE SIGNAL ;
    PORT
      LAYER M4 ;
        RECT  0 39.984 0.084 40.008 ;
    END
  END write_data[239]
  PIN write_data[23]
    DIRECTION INPUT ;
    USE SIGNAL ;
    PORT
      LAYER M4 ;
        RECT  0 56.88 0.084 56.904 ;
    END
  END write_data[23]
  PIN write_data[240]
    DIRECTION INPUT ;
    USE SIGNAL ;
    PORT
      LAYER M4 ;
        RECT  0 40.08 0.084 40.104 ;
    END
  END write_data[240]
  PIN write_data[241]
    DIRECTION INPUT ;
    USE SIGNAL ;
    PORT
      LAYER M4 ;
        RECT  0 40.176 0.084 40.2 ;
    END
  END write_data[241]
  PIN write_data[242]
    DIRECTION INPUT ;
    USE SIGNAL ;
    PORT
      LAYER M4 ;
        RECT  0 40.272 0.084 40.296 ;
    END
  END write_data[242]
  PIN write_data[243]
    DIRECTION INPUT ;
    USE SIGNAL ;
    PORT
      LAYER M4 ;
        RECT  0 40.368 0.084 40.392 ;
    END
  END write_data[243]
  PIN write_data[244]
    DIRECTION INPUT ;
    USE SIGNAL ;
    PORT
      LAYER M4 ;
        RECT  0 40.464 0.084 40.488 ;
    END
  END write_data[244]
  PIN write_data[245]
    DIRECTION INPUT ;
    USE SIGNAL ;
    PORT
      LAYER M4 ;
        RECT  0 40.56 0.084 40.584 ;
    END
  END write_data[245]
  PIN write_data[246]
    DIRECTION INPUT ;
    USE SIGNAL ;
    PORT
      LAYER M4 ;
        RECT  0 40.656 0.084 40.68 ;
    END
  END write_data[246]
  PIN write_data[247]
    DIRECTION INPUT ;
    USE SIGNAL ;
    PORT
      LAYER M4 ;
        RECT  0 40.752 0.084 40.776 ;
    END
  END write_data[247]
  PIN write_data[248]
    DIRECTION INPUT ;
    USE SIGNAL ;
    PORT
      LAYER M4 ;
        RECT  0 40.848 0.084 40.872 ;
    END
  END write_data[248]
  PIN write_data[249]
    DIRECTION INPUT ;
    USE SIGNAL ;
    PORT
      LAYER M4 ;
        RECT  0 40.944 0.084 40.968 ;
    END
  END write_data[249]
  PIN write_data[24]
    DIRECTION INPUT ;
    USE SIGNAL ;
    PORT
      LAYER M4 ;
        RECT  0 56.976 0.084 57 ;
    END
  END write_data[24]
  PIN write_data[250]
    DIRECTION INPUT ;
    USE SIGNAL ;
    PORT
      LAYER M4 ;
        RECT  0 41.04 0.084 41.064 ;
    END
  END write_data[250]
  PIN write_data[251]
    DIRECTION INPUT ;
    USE SIGNAL ;
    PORT
      LAYER M4 ;
        RECT  0 41.136 0.084 41.16 ;
    END
  END write_data[251]
  PIN write_data[252]
    DIRECTION INPUT ;
    USE SIGNAL ;
    PORT
      LAYER M4 ;
        RECT  0 41.232 0.084 41.256 ;
    END
  END write_data[252]
  PIN write_data[253]
    DIRECTION INPUT ;
    USE SIGNAL ;
    PORT
      LAYER M4 ;
        RECT  0 41.328 0.084 41.352 ;
    END
  END write_data[253]
  PIN write_data[254]
    DIRECTION INPUT ;
    USE SIGNAL ;
    PORT
      LAYER M4 ;
        RECT  0 41.424 0.084 41.448 ;
    END
  END write_data[254]
  PIN write_data[255]
    DIRECTION INPUT ;
    USE SIGNAL ;
    PORT
      LAYER M4 ;
        RECT  0 41.52 0.084 41.544 ;
    END
  END write_data[255]
  PIN write_data[25]
    DIRECTION INPUT ;
    USE SIGNAL ;
    PORT
      LAYER M4 ;
        RECT  0 57.072 0.084 57.096 ;
    END
  END write_data[25]
  PIN write_data[26]
    DIRECTION INPUT ;
    USE SIGNAL ;
    PORT
      LAYER M4 ;
        RECT  0 57.168 0.084 57.192 ;
    END
  END write_data[26]
  PIN write_data[27]
    DIRECTION INPUT ;
    USE SIGNAL ;
    PORT
      LAYER M4 ;
        RECT  0 57.264 0.084 57.288 ;
    END
  END write_data[27]
  PIN write_data[28]
    DIRECTION INPUT ;
    USE SIGNAL ;
    PORT
      LAYER M4 ;
        RECT  0 57.36 0.084 57.384 ;
    END
  END write_data[28]
  PIN write_data[29]
    DIRECTION INPUT ;
    USE SIGNAL ;
    PORT
      LAYER M4 ;
        RECT  0 57.456 0.084 57.48 ;
    END
  END write_data[29]
  PIN write_data[2]
    DIRECTION INPUT ;
    USE SIGNAL ;
    PORT
      LAYER M4 ;
        RECT  0 54.864 0.084 54.888 ;
    END
  END write_data[2]
  PIN write_data[30]
    DIRECTION INPUT ;
    USE SIGNAL ;
    PORT
      LAYER M4 ;
        RECT  0 57.552 0.084 57.576 ;
    END
  END write_data[30]
  PIN write_data[31]
    DIRECTION INPUT ;
    USE SIGNAL ;
    PORT
      LAYER M4 ;
        RECT  0 57.648 0.084 57.672 ;
    END
  END write_data[31]
  PIN write_data[32]
    DIRECTION INPUT ;
    USE SIGNAL ;
    PORT
      LAYER M4 ;
        RECT  0 57.744 0.084 57.768 ;
    END
  END write_data[32]
  PIN write_data[33]
    DIRECTION INPUT ;
    USE SIGNAL ;
    PORT
      LAYER M4 ;
        RECT  0 57.84 0.084 57.864 ;
    END
  END write_data[33]
  PIN write_data[34]
    DIRECTION INPUT ;
    USE SIGNAL ;
    PORT
      LAYER M4 ;
        RECT  0 57.936 0.084 57.96 ;
    END
  END write_data[34]
  PIN write_data[35]
    DIRECTION INPUT ;
    USE SIGNAL ;
    PORT
      LAYER M4 ;
        RECT  0 58.032 0.084 58.056 ;
    END
  END write_data[35]
  PIN write_data[36]
    DIRECTION INPUT ;
    USE SIGNAL ;
    PORT
      LAYER M4 ;
        RECT  0 58.128 0.084 58.152 ;
    END
  END write_data[36]
  PIN write_data[37]
    DIRECTION INPUT ;
    USE SIGNAL ;
    PORT
      LAYER M4 ;
        RECT  0 58.224 0.084 58.248 ;
    END
  END write_data[37]
  PIN write_data[38]
    DIRECTION INPUT ;
    USE SIGNAL ;
    PORT
      LAYER M4 ;
        RECT  0 58.32 0.084 58.344 ;
    END
  END write_data[38]
  PIN write_data[39]
    DIRECTION INPUT ;
    USE SIGNAL ;
    PORT
      LAYER M4 ;
        RECT  0 58.416 0.084 58.44 ;
    END
  END write_data[39]
  PIN write_data[3]
    DIRECTION INPUT ;
    USE SIGNAL ;
    PORT
      LAYER M4 ;
        RECT  0 54.96 0.084 54.984 ;
    END
  END write_data[3]
  PIN write_data[40]
    DIRECTION INPUT ;
    USE SIGNAL ;
    PORT
      LAYER M4 ;
        RECT  0 58.512 0.084 58.536 ;
    END
  END write_data[40]
  PIN write_data[41]
    DIRECTION INPUT ;
    USE SIGNAL ;
    PORT
      LAYER M4 ;
        RECT  0 58.608 0.084 58.632 ;
    END
  END write_data[41]
  PIN write_data[42]
    DIRECTION INPUT ;
    USE SIGNAL ;
    PORT
      LAYER M4 ;
        RECT  0 58.704 0.084 58.728 ;
    END
  END write_data[42]
  PIN write_data[43]
    DIRECTION INPUT ;
    USE SIGNAL ;
    PORT
      LAYER M4 ;
        RECT  0 58.8 0.084 58.824 ;
    END
  END write_data[43]
  PIN write_data[44]
    DIRECTION INPUT ;
    USE SIGNAL ;
    PORT
      LAYER M4 ;
        RECT  0 58.896 0.084 58.92 ;
    END
  END write_data[44]
  PIN write_data[45]
    DIRECTION INPUT ;
    USE SIGNAL ;
    PORT
      LAYER M4 ;
        RECT  0 58.992 0.084 59.016 ;
    END
  END write_data[45]
  PIN write_data[46]
    DIRECTION INPUT ;
    USE SIGNAL ;
    PORT
      LAYER M4 ;
        RECT  0 59.088 0.084 59.112 ;
    END
  END write_data[46]
  PIN write_data[47]
    DIRECTION INPUT ;
    USE SIGNAL ;
    PORT
      LAYER M4 ;
        RECT  0 59.184 0.084 59.208 ;
    END
  END write_data[47]
  PIN write_data[48]
    DIRECTION INPUT ;
    USE SIGNAL ;
    PORT
      LAYER M4 ;
        RECT  0 59.28 0.084 59.304 ;
    END
  END write_data[48]
  PIN write_data[49]
    DIRECTION INPUT ;
    USE SIGNAL ;
    PORT
      LAYER M4 ;
        RECT  0 59.376 0.084 59.4 ;
    END
  END write_data[49]
  PIN write_data[4]
    DIRECTION INPUT ;
    USE SIGNAL ;
    PORT
      LAYER M4 ;
        RECT  0 55.056 0.084 55.08 ;
    END
  END write_data[4]
  PIN write_data[50]
    DIRECTION INPUT ;
    USE SIGNAL ;
    PORT
      LAYER M4 ;
        RECT  0 59.472 0.084 59.496 ;
    END
  END write_data[50]
  PIN write_data[51]
    DIRECTION INPUT ;
    USE SIGNAL ;
    PORT
      LAYER M4 ;
        RECT  0 59.568 0.084 59.592 ;
    END
  END write_data[51]
  PIN write_data[52]
    DIRECTION INPUT ;
    USE SIGNAL ;
    PORT
      LAYER M4 ;
        RECT  0 59.664 0.084 59.688 ;
    END
  END write_data[52]
  PIN write_data[53]
    DIRECTION INPUT ;
    USE SIGNAL ;
    PORT
      LAYER M4 ;
        RECT  0 59.76 0.084 59.784 ;
    END
  END write_data[53]
  PIN write_data[54]
    DIRECTION INPUT ;
    USE SIGNAL ;
    PORT
      LAYER M4 ;
        RECT  0 59.856 0.084 59.88 ;
    END
  END write_data[54]
  PIN write_data[55]
    DIRECTION INPUT ;
    USE SIGNAL ;
    PORT
      LAYER M4 ;
        RECT  0 59.952 0.084 59.976 ;
    END
  END write_data[55]
  PIN write_data[56]
    DIRECTION INPUT ;
    USE SIGNAL ;
    PORT
      LAYER M4 ;
        RECT  0 60.048 0.084 60.072 ;
    END
  END write_data[56]
  PIN write_data[57]
    DIRECTION INPUT ;
    USE SIGNAL ;
    PORT
      LAYER M4 ;
        RECT  0 60.144 0.084 60.168 ;
    END
  END write_data[57]
  PIN write_data[58]
    DIRECTION INPUT ;
    USE SIGNAL ;
    PORT
      LAYER M4 ;
        RECT  0 60.24 0.084 60.264 ;
    END
  END write_data[58]
  PIN write_data[59]
    DIRECTION INPUT ;
    USE SIGNAL ;
    PORT
      LAYER M4 ;
        RECT  0 60.336 0.084 60.36 ;
    END
  END write_data[59]
  PIN write_data[5]
    DIRECTION INPUT ;
    USE SIGNAL ;
    PORT
      LAYER M4 ;
        RECT  0 55.152 0.084 55.176 ;
    END
  END write_data[5]
  PIN write_data[60]
    DIRECTION INPUT ;
    USE SIGNAL ;
    PORT
      LAYER M4 ;
        RECT  0 60.432 0.084 60.456 ;
    END
  END write_data[60]
  PIN write_data[61]
    DIRECTION INPUT ;
    USE SIGNAL ;
    PORT
      LAYER M4 ;
        RECT  0 60.528 0.084 60.552 ;
    END
  END write_data[61]
  PIN write_data[62]
    DIRECTION INPUT ;
    USE SIGNAL ;
    PORT
      LAYER M4 ;
        RECT  0 60.624 0.084 60.648 ;
    END
  END write_data[62]
  PIN write_data[63]
    DIRECTION INPUT ;
    USE SIGNAL ;
    PORT
      LAYER M4 ;
        RECT  0 60.72 0.084 60.744 ;
    END
  END write_data[63]
  PIN write_data[64]
    DIRECTION INPUT ;
    USE SIGNAL ;
    PORT
      LAYER M4 ;
        RECT  0 60.816 0.084 60.84 ;
    END
  END write_data[64]
  PIN write_data[65]
    DIRECTION INPUT ;
    USE SIGNAL ;
    PORT
      LAYER M4 ;
        RECT  0 60.912 0.084 60.936 ;
    END
  END write_data[65]
  PIN write_data[66]
    DIRECTION INPUT ;
    USE SIGNAL ;
    PORT
      LAYER M4 ;
        RECT  0 61.008 0.084 61.032 ;
    END
  END write_data[66]
  PIN write_data[67]
    DIRECTION INPUT ;
    USE SIGNAL ;
    PORT
      LAYER M4 ;
        RECT  0 61.104 0.084 61.128 ;
    END
  END write_data[67]
  PIN write_data[68]
    DIRECTION INPUT ;
    USE SIGNAL ;
    PORT
      LAYER M4 ;
        RECT  0 61.2 0.084 61.224 ;
    END
  END write_data[68]
  PIN write_data[69]
    DIRECTION INPUT ;
    USE SIGNAL ;
    PORT
      LAYER M4 ;
        RECT  0 61.296 0.084 61.32 ;
    END
  END write_data[69]
  PIN write_data[6]
    DIRECTION INPUT ;
    USE SIGNAL ;
    PORT
      LAYER M4 ;
        RECT  0 55.248 0.084 55.272 ;
    END
  END write_data[6]
  PIN write_data[70]
    DIRECTION INPUT ;
    USE SIGNAL ;
    PORT
      LAYER M4 ;
        RECT  0 61.392 0.084 61.416 ;
    END
  END write_data[70]
  PIN write_data[71]
    DIRECTION INPUT ;
    USE SIGNAL ;
    PORT
      LAYER M4 ;
        RECT  0 61.488 0.084 61.512 ;
    END
  END write_data[71]
  PIN write_data[72]
    DIRECTION INPUT ;
    USE SIGNAL ;
    PORT
      LAYER M4 ;
        RECT  0 61.584 0.084 61.608 ;
    END
  END write_data[72]
  PIN write_data[73]
    DIRECTION INPUT ;
    USE SIGNAL ;
    PORT
      LAYER M4 ;
        RECT  0 61.68 0.084 61.704 ;
    END
  END write_data[73]
  PIN write_data[74]
    DIRECTION INPUT ;
    USE SIGNAL ;
    PORT
      LAYER M4 ;
        RECT  0 61.776 0.084 61.8 ;
    END
  END write_data[74]
  PIN write_data[75]
    DIRECTION INPUT ;
    USE SIGNAL ;
    PORT
      LAYER M4 ;
        RECT  0 61.872 0.084 61.896 ;
    END
  END write_data[75]
  PIN write_data[76]
    DIRECTION INPUT ;
    USE SIGNAL ;
    PORT
      LAYER M4 ;
        RECT  0 61.968 0.084 61.992 ;
    END
  END write_data[76]
  PIN write_data[77]
    DIRECTION INPUT ;
    USE SIGNAL ;
    PORT
      LAYER M4 ;
        RECT  0 62.064 0.084 62.088 ;
    END
  END write_data[77]
  PIN write_data[78]
    DIRECTION INPUT ;
    USE SIGNAL ;
    PORT
      LAYER M4 ;
        RECT  0 62.16 0.084 62.184 ;
    END
  END write_data[78]
  PIN write_data[79]
    DIRECTION INPUT ;
    USE SIGNAL ;
    PORT
      LAYER M4 ;
        RECT  0 62.256 0.084 62.28 ;
    END
  END write_data[79]
  PIN write_data[7]
    DIRECTION INPUT ;
    USE SIGNAL ;
    PORT
      LAYER M4 ;
        RECT  0 55.344 0.084 55.368 ;
    END
  END write_data[7]
  PIN write_data[80]
    DIRECTION INPUT ;
    USE SIGNAL ;
    PORT
      LAYER M4 ;
        RECT  0 62.352 0.084 62.376 ;
    END
  END write_data[80]
  PIN write_data[81]
    DIRECTION INPUT ;
    USE SIGNAL ;
    PORT
      LAYER M4 ;
        RECT  0 62.448 0.084 62.472 ;
    END
  END write_data[81]
  PIN write_data[82]
    DIRECTION INPUT ;
    USE SIGNAL ;
    PORT
      LAYER M4 ;
        RECT  0 62.544 0.084 62.568 ;
    END
  END write_data[82]
  PIN write_data[83]
    DIRECTION INPUT ;
    USE SIGNAL ;
    PORT
      LAYER M4 ;
        RECT  0 62.64 0.084 62.664 ;
    END
  END write_data[83]
  PIN write_data[84]
    DIRECTION INPUT ;
    USE SIGNAL ;
    PORT
      LAYER M4 ;
        RECT  0 62.736 0.084 62.76 ;
    END
  END write_data[84]
  PIN write_data[85]
    DIRECTION INPUT ;
    USE SIGNAL ;
    PORT
      LAYER M4 ;
        RECT  0 62.832 0.084 62.856 ;
    END
  END write_data[85]
  PIN write_data[86]
    DIRECTION INPUT ;
    USE SIGNAL ;
    PORT
      LAYER M4 ;
        RECT  0 62.928 0.084 62.952 ;
    END
  END write_data[86]
  PIN write_data[87]
    DIRECTION INPUT ;
    USE SIGNAL ;
    PORT
      LAYER M4 ;
        RECT  0 63.024 0.084 63.048 ;
    END
  END write_data[87]
  PIN write_data[88]
    DIRECTION INPUT ;
    USE SIGNAL ;
    PORT
      LAYER M4 ;
        RECT  0 63.12 0.084 63.144 ;
    END
  END write_data[88]
  PIN write_data[89]
    DIRECTION INPUT ;
    USE SIGNAL ;
    PORT
      LAYER M4 ;
        RECT  0 63.216 0.084 63.24 ;
    END
  END write_data[89]
  PIN write_data[8]
    DIRECTION INPUT ;
    USE SIGNAL ;
    PORT
      LAYER M4 ;
        RECT  0 55.44 0.084 55.464 ;
    END
  END write_data[8]
  PIN write_data[90]
    DIRECTION INPUT ;
    USE SIGNAL ;
    PORT
      LAYER M4 ;
        RECT  0 63.312 0.084 63.336 ;
    END
  END write_data[90]
  PIN write_data[91]
    DIRECTION INPUT ;
    USE SIGNAL ;
    PORT
      LAYER M4 ;
        RECT  0 63.408 0.084 63.432 ;
    END
  END write_data[91]
  PIN write_data[92]
    DIRECTION INPUT ;
    USE SIGNAL ;
    PORT
      LAYER M4 ;
        RECT  0 63.504 0.084 63.528 ;
    END
  END write_data[92]
  PIN write_data[93]
    DIRECTION INPUT ;
    USE SIGNAL ;
    PORT
      LAYER M4 ;
        RECT  0 63.6 0.084 63.624 ;
    END
  END write_data[93]
  PIN write_data[94]
    DIRECTION INPUT ;
    USE SIGNAL ;
    PORT
      LAYER M4 ;
        RECT  0 63.696 0.084 63.72 ;
    END
  END write_data[94]
  PIN write_data[95]
    DIRECTION INPUT ;
    USE SIGNAL ;
    PORT
      LAYER M4 ;
        RECT  0 63.792 0.084 63.816 ;
    END
  END write_data[95]
  PIN write_data[96]
    DIRECTION INPUT ;
    USE SIGNAL ;
    PORT
      LAYER M4 ;
        RECT  0 63.888 0.084 63.912 ;
    END
  END write_data[96]
  PIN write_data[97]
    DIRECTION INPUT ;
    USE SIGNAL ;
    PORT
      LAYER M4 ;
        RECT  0 63.984 0.084 64.008 ;
    END
  END write_data[97]
  PIN write_data[98]
    DIRECTION INPUT ;
    USE SIGNAL ;
    PORT
      LAYER M4 ;
        RECT  0 64.08 0.084 64.104 ;
    END
  END write_data[98]
  PIN write_data[99]
    DIRECTION INPUT ;
    USE SIGNAL ;
    PORT
      LAYER M4 ;
        RECT  0 64.176 0.084 64.2 ;
    END
  END write_data[99]
  PIN write_data[9]
    DIRECTION INPUT ;
    USE SIGNAL ;
    PORT
      LAYER M4 ;
        RECT  0 55.536 0.084 55.56 ;
    END
  END write_data[9]
  PIN write_v
    DIRECTION INPUT ;
    USE SIGNAL ;
    PORT
      LAYER M4 ;
        RECT  0 46.704 0.084 46.728 ;
    END
  END write_v
  PIN write_word[0]
    DIRECTION INPUT ;
    USE SIGNAL ;
    PORT
      LAYER M4 ;
        RECT  0 46.8 0.084 46.824 ;
    END
  END write_word[0]
  PIN write_word[1]
    DIRECTION INPUT ;
    USE SIGNAL ;
    PORT
      LAYER M4 ;
        RECT  0 46.896 0.084 46.92 ;
    END
  END write_word[1]
  PIN write_word[2]
    DIRECTION INPUT ;
    USE SIGNAL ;
    PORT
      LAYER M4 ;
        RECT  0 46.992 0.084 47.016 ;
    END
  END write_word[2]
  PIN write_word[3]
    DIRECTION INPUT ;
    USE SIGNAL ;
    PORT
      LAYER M4 ;
        RECT  0 47.088 0.084 47.112 ;
    END
  END write_word[3]
  PIN write_word[4]
    DIRECTION INPUT ;
    USE SIGNAL ;
    PORT
      LAYER M4 ;
        RECT  0 47.184 0.084 47.208 ;
    END
  END write_word[4]
  PIN write_word[5]
    DIRECTION INPUT ;
    USE SIGNAL ;
    PORT
      LAYER M4 ;
        RECT  0 47.28 0.084 47.304 ;
    END
  END write_word[5]
  PIN write_word[6]
    DIRECTION INPUT ;
    USE SIGNAL ;
    PORT
      LAYER M4 ;
        RECT  0 47.376 0.084 47.4 ;
    END
  END write_word[6]
  PIN write_word[7]
    DIRECTION INPUT ;
    USE SIGNAL ;
    PORT
      LAYER M4 ;
        RECT  0 47.472 0.084 47.496 ;
    END
  END write_word[7]
  PIN write_word[8]
    DIRECTION INPUT ;
    USE SIGNAL ;
    PORT
      LAYER M4 ;
        RECT  0 47.568 0.084 47.592 ;
    END
  END write_word[8]
  PIN write_word[9]
    DIRECTION INPUT ;
    USE SIGNAL ;
    PORT
      LAYER M4 ;
        RECT  0 47.664 0.084 47.688 ;
    END
  END write_word[9]
  PIN VDD
    DIRECTION INOUT ;
    USE POWER ;
    PORT
      LAYER M5 ;
        RECT  213.192 2.151 213.312 123.129 ;
        RECT  207.792 2.151 207.912 123.129 ;
        RECT  202.392 2.151 202.512 123.129 ;
        RECT  196.992 2.151 197.112 123.129 ;
        RECT  191.592 2.151 191.712 123.129 ;
        RECT  186.192 2.151 186.312 123.129 ;
        RECT  180.792 2.151 180.912 123.129 ;
        RECT  175.392 2.151 175.512 123.129 ;
        RECT  169.992 2.151 170.112 123.129 ;
        RECT  164.592 2.151 164.712 123.129 ;
        RECT  159.192 2.151 159.312 123.129 ;
        RECT  153.792 2.151 153.912 123.129 ;
        RECT  148.392 2.151 148.512 123.129 ;
        RECT  142.992 2.151 143.112 123.129 ;
        RECT  137.592 2.151 137.712 123.129 ;
        RECT  132.192 2.151 132.312 123.129 ;
        RECT  126.792 2.151 126.912 123.129 ;
        RECT  121.392 2.151 121.512 123.129 ;
        RECT  115.992 2.151 116.112 123.129 ;
        RECT  110.592 2.151 110.712 123.129 ;
        RECT  105.192 2.151 105.312 123.129 ;
        RECT  99.792 2.151 99.912 123.129 ;
        RECT  94.392 2.151 94.512 123.129 ;
        RECT  88.992 2.151 89.112 123.129 ;
        RECT  83.592 2.151 83.712 123.129 ;
        RECT  78.192 2.151 78.312 123.129 ;
        RECT  72.792 2.151 72.912 123.129 ;
        RECT  67.392 2.151 67.512 123.129 ;
        RECT  61.992 2.151 62.112 123.129 ;
        RECT  56.592 2.151 56.712 123.129 ;
        RECT  51.192 2.151 51.312 123.129 ;
        RECT  45.792 2.151 45.912 123.129 ;
        RECT  40.392 2.151 40.512 123.129 ;
        RECT  34.992 2.151 35.112 123.129 ;
        RECT  29.592 2.151 29.712 123.129 ;
        RECT  24.192 2.151 24.312 123.129 ;
        RECT  18.792 2.151 18.912 123.129 ;
        RECT  13.392 2.151 13.512 123.129 ;
        RECT  7.992 2.151 8.112 123.129 ;
        RECT  2.592 2.151 2.712 123.129 ;
    END
  END VDD
  PIN VSS
    DIRECTION INOUT ;
    USE GROUND ;
    PORT
      LAYER M5 ;
        RECT  213 2.137 213.12 123.143 ;
        RECT  207.6 2.137 207.72 123.143 ;
        RECT  202.2 2.137 202.32 123.143 ;
        RECT  196.8 2.137 196.92 123.143 ;
        RECT  191.4 2.137 191.52 123.143 ;
        RECT  186 2.137 186.12 123.143 ;
        RECT  180.6 2.137 180.72 123.143 ;
        RECT  175.2 2.137 175.32 123.143 ;
        RECT  169.8 2.137 169.92 123.143 ;
        RECT  164.4 2.137 164.52 123.143 ;
        RECT  159 2.137 159.12 123.143 ;
        RECT  153.6 2.137 153.72 123.143 ;
        RECT  148.2 2.137 148.32 123.143 ;
        RECT  142.8 2.137 142.92 123.143 ;
        RECT  137.4 2.137 137.52 123.143 ;
        RECT  132 2.137 132.12 123.143 ;
        RECT  126.6 2.137 126.72 123.143 ;
        RECT  121.2 2.137 121.32 123.143 ;
        RECT  115.8 2.137 115.92 123.143 ;
        RECT  110.4 2.137 110.52 123.143 ;
        RECT  105 2.137 105.12 123.143 ;
        RECT  99.6 2.137 99.72 123.143 ;
        RECT  94.2 2.137 94.32 123.143 ;
        RECT  88.8 2.137 88.92 123.143 ;
        RECT  83.4 2.137 83.52 123.143 ;
        RECT  78 2.137 78.12 123.143 ;
        RECT  72.6 2.137 72.72 123.143 ;
        RECT  67.2 2.137 67.32 123.143 ;
        RECT  61.8 2.137 61.92 123.143 ;
        RECT  56.4 2.137 56.52 123.143 ;
        RECT  51 2.137 51.12 123.143 ;
        RECT  45.6 2.137 45.72 123.143 ;
        RECT  40.2 2.137 40.32 123.143 ;
        RECT  34.8 2.137 34.92 123.143 ;
        RECT  29.4 2.137 29.52 123.143 ;
        RECT  24 2.137 24.12 123.143 ;
        RECT  18.6 2.137 18.72 123.143 ;
        RECT  13.2 2.137 13.32 123.143 ;
        RECT  7.8 2.137 7.92 123.143 ;
        RECT  2.4 2.137 2.52 123.143 ;
    END
  END VSS
  # OT_OBS_CLOSED layer=M5 d_um=1.536 added=83
  OBS
    LAYER RVTN ;
     RECT  2.16 2.16 218.16 2.295 ;
     RECT  2.16 2.565 218.16 2.835 ;
     RECT  2.16 3.105 218.16 3.375 ;
     RECT  2.16 3.645 218.16 3.915 ;
     RECT  2.16 4.185 218.16 4.455 ;
     RECT  2.16 4.725 218.16 4.995 ;
     RECT  2.16 5.265 218.16 5.535 ;
     RECT  2.16 5.805 218.16 6.075 ;
     RECT  2.16 6.345 218.16 6.615 ;
     RECT  2.16 6.885 218.16 7.155 ;
     RECT  2.16 7.425 218.16 7.695 ;
     RECT  2.16 7.965 218.16 8.235 ;
     RECT  2.16 8.505 218.16 8.775 ;
     RECT  2.16 9.045 218.16 9.315 ;
     RECT  2.16 9.585 218.16 9.855 ;
     RECT  2.16 10.125 218.16 10.395 ;
     RECT  2.16 10.665 218.16 10.935 ;
     RECT  2.16 11.205 218.16 11.475 ;
     RECT  2.16 11.745 218.16 12.015 ;
     RECT  2.16 12.285 218.16 12.555 ;
     RECT  2.16 12.825 218.16 13.095 ;
     RECT  2.16 13.365 218.16 13.635 ;
     RECT  2.16 13.905 218.16 14.175 ;
     RECT  2.16 14.445 218.16 14.715 ;
     RECT  2.16 14.985 218.16 15.255 ;
     RECT  2.16 15.525 218.16 15.795 ;
     RECT  2.16 16.065 218.16 16.335 ;
     RECT  2.16 16.605 218.16 16.875 ;
     RECT  2.16 17.145 218.16 17.415 ;
     RECT  2.16 17.685 218.16 17.955 ;
     RECT  2.16 18.225 218.16 18.495 ;
     RECT  2.16 18.765 218.16 19.035 ;
     RECT  2.16 19.305 218.16 19.575 ;
     RECT  2.16 19.845 218.16 20.115 ;
     RECT  2.16 20.385 218.16 20.655 ;
     RECT  2.16 20.925 218.16 21.195 ;
     RECT  2.16 21.465 218.16 21.735 ;
     RECT  2.16 22.005 218.16 22.275 ;
     RECT  2.16 22.545 218.16 22.815 ;
     RECT  2.16 23.085 218.16 23.355 ;
     RECT  2.16 23.625 218.16 23.895 ;
     RECT  2.16 24.165 218.16 24.435 ;
     RECT  2.16 24.705 218.16 24.975 ;
     RECT  2.16 25.245 218.16 25.515 ;
     RECT  2.16 25.785 218.16 25.92 ;
     RECT  2.16 25.92 20.844 26.055 ;
     RECT  199.692 25.92 218.16 26.055 ;
     RECT  2.16 26.325 20.844 26.595 ;
     RECT  199.692 26.325 218.16 26.595 ;
     RECT  2.16 26.865 20.844 27.135 ;
     RECT  199.692 26.865 218.16 27.135 ;
     RECT  2.16 27.405 20.844 27.675 ;
     RECT  199.692 27.405 218.16 27.675 ;
     RECT  2.16 27.945 20.844 28.215 ;
     RECT  199.692 27.945 218.16 28.215 ;
     RECT  2.16 28.485 20.844 28.755 ;
     RECT  199.692 28.485 218.16 28.755 ;
     RECT  2.16 29.025 20.844 29.295 ;
     RECT  199.692 29.025 218.16 29.295 ;
     RECT  2.16 29.565 20.844 29.835 ;
     RECT  199.692 29.565 218.16 29.835 ;
     RECT  2.16 30.105 20.844 30.375 ;
     RECT  199.692 30.105 218.16 30.375 ;
     RECT  2.16 30.645 20.844 30.915 ;
     RECT  199.692 30.645 218.16 30.915 ;
     RECT  2.16 31.185 20.844 31.455 ;
     RECT  199.692 31.185 218.16 31.455 ;
     RECT  2.16 31.725 20.844 31.995 ;
     RECT  199.692 31.725 218.16 31.995 ;
     RECT  2.16 32.265 20.844 32.535 ;
     RECT  199.692 32.265 218.16 32.535 ;
     RECT  2.16 32.805 20.844 33.075 ;
     RECT  199.692 32.805 218.16 33.075 ;
     RECT  2.16 33.345 20.844 33.615 ;
     RECT  199.692 33.345 218.16 33.615 ;
     RECT  2.16 33.885 20.844 34.155 ;
     RECT  199.692 33.885 218.16 34.155 ;
     RECT  2.16 34.425 20.844 34.695 ;
     RECT  199.692 34.425 218.16 34.695 ;
     RECT  2.16 34.965 20.844 35.235 ;
     RECT  199.692 34.965 218.16 35.235 ;
     RECT  2.16 35.505 20.844 35.775 ;
     RECT  199.692 35.505 218.16 35.775 ;
     RECT  2.16 36.045 20.844 36.315 ;
     RECT  199.692 36.045 218.16 36.315 ;
     RECT  2.16 36.585 20.844 36.855 ;
     RECT  199.692 36.585 218.16 36.855 ;
     RECT  2.16 37.125 20.844 37.395 ;
     RECT  199.692 37.125 218.16 37.395 ;
     RECT  2.16 37.665 20.844 37.935 ;
     RECT  199.692 37.665 218.16 37.935 ;
     RECT  2.16 38.205 20.844 38.475 ;
     RECT  199.692 38.205 218.16 38.475 ;
     RECT  2.16 38.745 20.844 39.015 ;
     RECT  199.692 38.745 218.16 39.015 ;
     RECT  2.16 39.285 20.844 39.555 ;
     RECT  199.692 39.285 218.16 39.555 ;
     RECT  2.16 39.825 20.844 40.095 ;
     RECT  199.692 39.825 218.16 40.095 ;
     RECT  2.16 40.365 20.844 40.635 ;
     RECT  199.692 40.365 218.16 40.635 ;
     RECT  2.16 40.905 20.844 41.175 ;
     RECT  199.692 40.905 218.16 41.175 ;
     RECT  2.16 41.445 20.844 41.715 ;
     RECT  199.692 41.445 218.16 41.715 ;
     RECT  2.16 41.985 20.844 42.255 ;
     RECT  199.692 41.985 218.16 42.255 ;
     RECT  2.16 42.525 20.844 42.795 ;
     RECT  199.692 42.525 218.16 42.795 ;
     RECT  2.16 43.065 20.844 43.335 ;
     RECT  199.692 43.065 218.16 43.335 ;
     RECT  2.16 43.605 20.844 43.875 ;
     RECT  199.692 43.605 218.16 43.875 ;
     RECT  2.16 44.145 20.844 44.415 ;
     RECT  199.692 44.145 218.16 44.415 ;
     RECT  2.16 44.685 20.844 44.955 ;
     RECT  199.692 44.685 218.16 44.955 ;
     RECT  2.16 45.225 20.844 45.495 ;
     RECT  199.692 45.225 218.16 45.495 ;
     RECT  2.16 45.765 20.844 46.035 ;
     RECT  199.692 45.765 218.16 46.035 ;
     RECT  2.16 46.305 20.844 46.575 ;
     RECT  199.692 46.305 218.16 46.575 ;
     RECT  2.16 46.845 20.844 47.115 ;
     RECT  199.692 46.845 218.16 47.115 ;
     RECT  2.16 47.385 20.844 47.655 ;
     RECT  199.692 47.385 218.16 47.655 ;
     RECT  2.16 47.925 20.844 48.195 ;
     RECT  199.692 47.925 218.16 48.195 ;
     RECT  2.16 48.465 20.844 48.735 ;
     RECT  199.692 48.465 218.16 48.735 ;
     RECT  2.16 49.005 20.844 49.275 ;
     RECT  199.692 49.005 218.16 49.275 ;
     RECT  2.16 49.545 20.844 49.815 ;
     RECT  199.692 49.545 218.16 49.815 ;
     RECT  2.16 50.085 20.844 50.355 ;
     RECT  199.692 50.085 218.16 50.355 ;
     RECT  2.16 50.625 20.844 50.895 ;
     RECT  199.692 50.625 218.16 50.895 ;
     RECT  2.16 51.165 20.844 51.435 ;
     RECT  199.692 51.165 218.16 51.435 ;
     RECT  2.16 51.705 20.844 51.975 ;
     RECT  199.692 51.705 218.16 51.975 ;
     RECT  2.16 52.245 20.844 52.515 ;
     RECT  199.692 52.245 218.16 52.515 ;
     RECT  2.16 52.785 20.844 53.055 ;
     RECT  199.692 52.785 218.16 53.055 ;
     RECT  2.16 53.325 20.844 53.595 ;
     RECT  199.692 53.325 218.16 53.595 ;
     RECT  2.16 53.865 20.844 54.135 ;
     RECT  199.692 53.865 218.16 54.135 ;
     RECT  2.16 54.405 20.844 54.675 ;
     RECT  199.692 54.405 218.16 54.675 ;
     RECT  2.16 54.945 20.844 55.215 ;
     RECT  199.692 54.945 218.16 55.215 ;
     RECT  2.16 55.485 20.844 55.755 ;
     RECT  199.692 55.485 218.16 55.755 ;
     RECT  2.16 56.025 20.844 56.295 ;
     RECT  199.692 56.025 218.16 56.295 ;
     RECT  2.16 56.565 20.844 56.835 ;
     RECT  199.692 56.565 218.16 56.835 ;
     RECT  2.16 57.105 20.844 57.375 ;
     RECT  199.692 57.105 218.16 57.375 ;
     RECT  2.16 57.645 20.844 57.915 ;
     RECT  199.692 57.645 218.16 57.915 ;
     RECT  2.16 58.185 20.844 58.455 ;
     RECT  199.692 58.185 218.16 58.455 ;
     RECT  2.16 58.725 20.844 58.995 ;
     RECT  199.692 58.725 218.16 58.995 ;
     RECT  2.16 59.265 20.844 59.535 ;
     RECT  199.692 59.265 218.16 59.535 ;
     RECT  2.16 59.805 20.844 60.075 ;
     RECT  199.692 59.805 218.16 60.075 ;
     RECT  2.16 60.345 20.844 60.615 ;
     RECT  199.692 60.345 218.16 60.615 ;
     RECT  2.16 60.885 20.844 61.155 ;
     RECT  199.692 60.885 218.16 61.155 ;
     RECT  2.16 61.425 20.844 61.695 ;
     RECT  199.692 61.425 218.16 61.695 ;
     RECT  2.16 61.965 20.844 62.235 ;
     RECT  199.692 61.965 218.16 62.235 ;
     RECT  2.16 62.505 20.844 62.775 ;
     RECT  199.692 62.505 218.16 62.775 ;
     RECT  2.16 63.045 20.844 63.315 ;
     RECT  199.692 63.045 218.16 63.315 ;
     RECT  2.16 63.585 20.844 63.855 ;
     RECT  199.692 63.585 218.16 63.855 ;
     RECT  2.16 64.125 20.844 64.395 ;
     RECT  199.692 64.125 218.16 64.395 ;
     RECT  2.16 64.665 20.844 64.935 ;
     RECT  199.692 64.665 218.16 64.935 ;
     RECT  2.16 65.205 20.844 65.475 ;
     RECT  199.692 65.205 218.16 65.475 ;
     RECT  2.16 65.745 20.844 66.015 ;
     RECT  199.692 65.745 218.16 66.015 ;
     RECT  2.16 66.285 20.844 66.555 ;
     RECT  199.692 66.285 218.16 66.555 ;
     RECT  2.16 66.825 20.844 67.095 ;
     RECT  199.692 66.825 218.16 67.095 ;
     RECT  2.16 67.365 20.844 67.635 ;
     RECT  199.692 67.365 218.16 67.635 ;
     RECT  2.16 67.905 20.844 68.175 ;
     RECT  199.692 67.905 218.16 68.175 ;
     RECT  2.16 68.445 20.844 68.715 ;
     RECT  199.692 68.445 218.16 68.715 ;
     RECT  2.16 68.985 20.844 69.255 ;
     RECT  199.692 68.985 218.16 69.255 ;
     RECT  2.16 69.525 20.844 69.795 ;
     RECT  199.692 69.525 218.16 69.795 ;
     RECT  2.16 70.065 20.844 70.335 ;
     RECT  199.692 70.065 218.16 70.335 ;
     RECT  2.16 70.605 20.844 70.875 ;
     RECT  199.692 70.605 218.16 70.875 ;
     RECT  2.16 71.145 20.844 71.415 ;
     RECT  199.692 71.145 218.16 71.415 ;
     RECT  2.16 71.685 20.844 71.955 ;
     RECT  199.692 71.685 218.16 71.955 ;
     RECT  2.16 72.225 20.844 72.495 ;
     RECT  199.692 72.225 218.16 72.495 ;
     RECT  2.16 72.765 20.844 73.035 ;
     RECT  199.692 72.765 218.16 73.035 ;
     RECT  2.16 73.305 20.844 73.575 ;
     RECT  199.692 73.305 218.16 73.575 ;
     RECT  2.16 73.845 20.844 74.115 ;
     RECT  199.692 73.845 218.16 74.115 ;
     RECT  2.16 74.385 20.844 74.655 ;
     RECT  199.692 74.385 218.16 74.655 ;
     RECT  2.16 74.925 20.844 75.195 ;
     RECT  199.692 74.925 218.16 75.195 ;
     RECT  2.16 75.465 20.844 75.735 ;
     RECT  199.692 75.465 218.16 75.735 ;
     RECT  2.16 76.005 20.844 76.275 ;
     RECT  199.692 76.005 218.16 76.275 ;
     RECT  2.16 76.545 20.844 76.815 ;
     RECT  199.692 76.545 218.16 76.815 ;
     RECT  2.16 77.085 20.844 77.355 ;
     RECT  199.692 77.085 218.16 77.355 ;
     RECT  2.16 77.625 20.844 77.895 ;
     RECT  199.692 77.625 218.16 77.895 ;
     RECT  2.16 78.165 20.844 78.435 ;
     RECT  199.692 78.165 218.16 78.435 ;
     RECT  2.16 78.705 20.844 78.975 ;
     RECT  199.692 78.705 218.16 78.975 ;
     RECT  2.16 79.245 20.844 79.515 ;
     RECT  199.692 79.245 218.16 79.515 ;
     RECT  2.16 79.785 20.844 80.055 ;
     RECT  199.692 79.785 218.16 80.055 ;
     RECT  2.16 80.325 20.844 80.595 ;
     RECT  199.692 80.325 218.16 80.595 ;
     RECT  2.16 80.865 20.844 81.135 ;
     RECT  199.692 80.865 218.16 81.135 ;
     RECT  2.16 81.405 20.844 81.675 ;
     RECT  199.692 81.405 218.16 81.675 ;
     RECT  2.16 81.945 20.844 82.215 ;
     RECT  199.692 81.945 218.16 82.215 ;
     RECT  2.16 82.485 20.844 82.755 ;
     RECT  199.692 82.485 218.16 82.755 ;
     RECT  2.16 83.025 20.844 83.295 ;
     RECT  199.692 83.025 218.16 83.295 ;
     RECT  2.16 83.565 20.844 83.835 ;
     RECT  199.692 83.565 218.16 83.835 ;
     RECT  2.16 84.105 20.844 84.375 ;
     RECT  199.692 84.105 218.16 84.375 ;
     RECT  2.16 84.645 20.844 84.915 ;
     RECT  199.692 84.645 218.16 84.915 ;
     RECT  2.16 85.185 20.844 85.455 ;
     RECT  199.692 85.185 218.16 85.455 ;
     RECT  2.16 85.725 20.844 85.995 ;
     RECT  199.692 85.725 218.16 85.995 ;
     RECT  2.16 86.265 20.844 86.535 ;
     RECT  199.692 86.265 218.16 86.535 ;
     RECT  2.16 86.805 20.844 87.075 ;
     RECT  199.692 86.805 218.16 87.075 ;
     RECT  2.16 87.345 20.844 87.615 ;
     RECT  199.692 87.345 218.16 87.615 ;
     RECT  2.16 87.885 20.844 88.155 ;
     RECT  199.692 87.885 218.16 88.155 ;
     RECT  2.16 88.425 20.844 88.695 ;
     RECT  199.692 88.425 218.16 88.695 ;
     RECT  2.16 88.965 20.844 89.235 ;
     RECT  199.692 88.965 218.16 89.235 ;
     RECT  2.16 89.505 20.844 89.775 ;
     RECT  199.692 89.505 218.16 89.775 ;
     RECT  2.16 90.045 20.844 90.315 ;
     RECT  199.692 90.045 218.16 90.315 ;
     RECT  2.16 90.585 20.844 90.855 ;
     RECT  199.692 90.585 218.16 90.855 ;
     RECT  2.16 91.125 20.844 91.395 ;
     RECT  199.692 91.125 218.16 91.395 ;
     RECT  2.16 91.665 20.844 91.935 ;
     RECT  199.692 91.665 218.16 91.935 ;
     RECT  2.16 92.205 20.844 92.475 ;
     RECT  199.692 92.205 218.16 92.475 ;
     RECT  2.16 92.745 20.844 93.015 ;
     RECT  199.692 92.745 218.16 93.015 ;
     RECT  2.16 93.285 20.844 93.555 ;
     RECT  199.692 93.285 218.16 93.555 ;
     RECT  2.16 93.825 20.844 94.095 ;
     RECT  199.692 93.825 218.16 94.095 ;
     RECT  2.16 94.365 20.844 94.635 ;
     RECT  199.692 94.365 218.16 94.635 ;
     RECT  2.16 94.905 20.844 95.175 ;
     RECT  199.692 94.905 218.16 95.175 ;
     RECT  2.16 95.445 20.844 95.715 ;
     RECT  199.692 95.445 218.16 95.715 ;
     RECT  2.16 95.985 20.844 96.255 ;
     RECT  199.692 95.985 218.16 96.255 ;
     RECT  2.16 96.525 20.844 96.795 ;
     RECT  199.692 96.525 218.16 96.795 ;
     RECT  2.16 97.065 20.844 97.335 ;
     RECT  199.692 97.065 218.16 97.335 ;
     RECT  2.16 97.605 20.844 97.875 ;
     RECT  199.692 97.605 218.16 97.875 ;
     RECT  2.16 98.145 20.844 98.415 ;
     RECT  199.692 98.145 218.16 98.415 ;
     RECT  2.16 98.685 20.844 98.955 ;
     RECT  199.692 98.685 218.16 98.955 ;
     RECT  2.16 99.225 20.844 99.495 ;
     RECT  199.692 99.225 218.16 99.495 ;
     RECT  2.16 99.765 20.844 100.035 ;
     RECT  199.692 99.765 218.16 100.035 ;
     RECT  2.16 100.305 20.844 100.575 ;
     RECT  199.692 100.305 218.16 100.575 ;
     RECT  2.16 100.845 218.16 101.115 ;
     RECT  2.16 101.385 218.16 101.655 ;
     RECT  2.16 101.925 218.16 102.195 ;
     RECT  2.16 102.465 218.16 102.735 ;
     RECT  2.16 103.005 218.16 103.275 ;
     RECT  2.16 103.545 218.16 103.815 ;
     RECT  2.16 104.085 218.16 104.355 ;
     RECT  2.16 104.625 218.16 104.895 ;
     RECT  2.16 105.165 218.16 105.435 ;
     RECT  2.16 105.705 218.16 105.975 ;
     RECT  2.16 106.245 218.16 106.515 ;
     RECT  2.16 106.785 218.16 107.055 ;
     RECT  2.16 107.325 218.16 107.595 ;
     RECT  2.16 107.865 218.16 108.135 ;
     RECT  2.16 108.405 218.16 108.675 ;
     RECT  2.16 108.945 218.16 109.215 ;
     RECT  2.16 109.485 218.16 109.755 ;
     RECT  2.16 110.025 218.16 110.295 ;
     RECT  2.16 110.565 218.16 110.835 ;
     RECT  2.16 111.105 218.16 111.375 ;
     RECT  2.16 111.645 218.16 111.915 ;
     RECT  2.16 112.185 218.16 112.455 ;
     RECT  2.16 112.725 218.16 112.995 ;
     RECT  2.16 113.265 218.16 113.535 ;
     RECT  2.16 113.805 218.16 114.075 ;
     RECT  2.16 114.345 218.16 114.615 ;
     RECT  2.16 114.885 218.16 115.155 ;
     RECT  2.16 115.425 218.16 115.695 ;
     RECT  2.16 115.965 218.16 116.235 ;
     RECT  2.16 116.505 218.16 116.775 ;
     RECT  2.16 117.045 218.16 117.315 ;
     RECT  2.16 117.585 218.16 117.855 ;
     RECT  2.16 118.125 218.16 118.395 ;
     RECT  2.16 118.665 218.16 118.935 ;
     RECT  2.16 119.205 218.16 119.475 ;
     RECT  2.16 119.745 218.16 120.015 ;
     RECT  2.16 120.285 218.16 120.555 ;
     RECT  2.16 120.825 218.16 121.095 ;
     RECT  2.16 121.365 218.16 121.635 ;
     RECT  2.16 121.905 218.16 122.175 ;
     RECT  2.16 122.445 218.16 122.715 ;
     RECT  2.16 122.985 218.16 123.12 ;
    LAYER RVTP ;
     RECT  2.16 2.295 218.16 2.565 ;
     RECT  2.16 2.835 218.16 3.105 ;
     RECT  2.16 3.375 218.16 3.645 ;
     RECT  2.16 3.915 218.16 4.185 ;
     RECT  2.16 4.455 218.16 4.725 ;
     RECT  2.16 4.995 218.16 5.265 ;
     RECT  2.16 5.535 218.16 5.805 ;
     RECT  2.16 6.075 218.16 6.345 ;
     RECT  2.16 6.615 218.16 6.885 ;
     RECT  2.16 7.155 218.16 7.425 ;
     RECT  2.16 7.695 218.16 7.965 ;
     RECT  2.16 8.235 218.16 8.505 ;
     RECT  2.16 8.775 218.16 9.045 ;
     RECT  2.16 9.315 218.16 9.585 ;
     RECT  2.16 9.855 218.16 10.125 ;
     RECT  2.16 10.395 218.16 10.665 ;
     RECT  2.16 10.935 218.16 11.205 ;
     RECT  2.16 11.475 218.16 11.745 ;
     RECT  2.16 12.015 218.16 12.285 ;
     RECT  2.16 12.555 218.16 12.825 ;
     RECT  2.16 13.095 218.16 13.365 ;
     RECT  2.16 13.635 218.16 13.905 ;
     RECT  2.16 14.175 218.16 14.445 ;
     RECT  2.16 14.715 218.16 14.985 ;
     RECT  2.16 15.255 218.16 15.525 ;
     RECT  2.16 15.795 218.16 16.065 ;
     RECT  2.16 16.335 218.16 16.605 ;
     RECT  2.16 16.875 218.16 17.145 ;
     RECT  2.16 17.415 218.16 17.685 ;
     RECT  2.16 17.955 218.16 18.225 ;
     RECT  2.16 18.495 218.16 18.765 ;
     RECT  2.16 19.035 218.16 19.305 ;
     RECT  2.16 19.575 218.16 19.845 ;
     RECT  2.16 20.115 218.16 20.385 ;
     RECT  2.16 20.655 218.16 20.925 ;
     RECT  2.16 21.195 218.16 21.465 ;
     RECT  2.16 21.735 218.16 22.005 ;
     RECT  2.16 22.275 218.16 22.545 ;
     RECT  2.16 22.815 218.16 23.085 ;
     RECT  2.16 23.355 218.16 23.625 ;
     RECT  2.16 23.895 218.16 24.165 ;
     RECT  2.16 24.435 218.16 24.705 ;
     RECT  2.16 24.975 218.16 25.245 ;
     RECT  2.16 25.515 218.16 25.785 ;
     RECT  2.16 26.055 20.844 26.325 ;
     RECT  199.692 26.055 218.16 26.325 ;
     RECT  2.16 26.595 20.844 26.865 ;
     RECT  199.692 26.595 218.16 26.865 ;
     RECT  2.16 27.135 20.844 27.405 ;
     RECT  199.692 27.135 218.16 27.405 ;
     RECT  2.16 27.675 20.844 27.945 ;
     RECT  199.692 27.675 218.16 27.945 ;
     RECT  2.16 28.215 20.844 28.485 ;
     RECT  199.692 28.215 218.16 28.485 ;
     RECT  2.16 28.755 20.844 29.025 ;
     RECT  199.692 28.755 218.16 29.025 ;
     RECT  2.16 29.295 20.844 29.565 ;
     RECT  199.692 29.295 218.16 29.565 ;
     RECT  2.16 29.835 20.844 30.105 ;
     RECT  199.692 29.835 218.16 30.105 ;
     RECT  2.16 30.375 20.844 30.645 ;
     RECT  199.692 30.375 218.16 30.645 ;
     RECT  2.16 30.915 20.844 31.185 ;
     RECT  199.692 30.915 218.16 31.185 ;
     RECT  2.16 31.455 20.844 31.725 ;
     RECT  199.692 31.455 218.16 31.725 ;
     RECT  2.16 31.995 20.844 32.265 ;
     RECT  199.692 31.995 218.16 32.265 ;
     RECT  2.16 32.535 20.844 32.805 ;
     RECT  199.692 32.535 218.16 32.805 ;
     RECT  2.16 33.075 20.844 33.345 ;
     RECT  199.692 33.075 218.16 33.345 ;
     RECT  2.16 33.615 20.844 33.885 ;
     RECT  199.692 33.615 218.16 33.885 ;
     RECT  2.16 34.155 20.844 34.425 ;
     RECT  199.692 34.155 218.16 34.425 ;
     RECT  2.16 34.695 20.844 34.965 ;
     RECT  199.692 34.695 218.16 34.965 ;
     RECT  2.16 35.235 20.844 35.505 ;
     RECT  199.692 35.235 218.16 35.505 ;
     RECT  2.16 35.775 20.844 36.045 ;
     RECT  199.692 35.775 218.16 36.045 ;
     RECT  2.16 36.315 20.844 36.585 ;
     RECT  199.692 36.315 218.16 36.585 ;
     RECT  2.16 36.855 20.844 37.125 ;
     RECT  199.692 36.855 218.16 37.125 ;
     RECT  2.16 37.395 20.844 37.665 ;
     RECT  199.692 37.395 218.16 37.665 ;
     RECT  2.16 37.935 20.844 38.205 ;
     RECT  199.692 37.935 218.16 38.205 ;
     RECT  2.16 38.475 20.844 38.745 ;
     RECT  199.692 38.475 218.16 38.745 ;
     RECT  2.16 39.015 20.844 39.285 ;
     RECT  199.692 39.015 218.16 39.285 ;
     RECT  2.16 39.555 20.844 39.825 ;
     RECT  199.692 39.555 218.16 39.825 ;
     RECT  2.16 40.095 20.844 40.365 ;
     RECT  199.692 40.095 218.16 40.365 ;
     RECT  2.16 40.635 20.844 40.905 ;
     RECT  199.692 40.635 218.16 40.905 ;
     RECT  2.16 41.175 20.844 41.445 ;
     RECT  199.692 41.175 218.16 41.445 ;
     RECT  2.16 41.715 20.844 41.985 ;
     RECT  199.692 41.715 218.16 41.985 ;
     RECT  2.16 42.255 20.844 42.525 ;
     RECT  199.692 42.255 218.16 42.525 ;
     RECT  2.16 42.795 20.844 43.065 ;
     RECT  199.692 42.795 218.16 43.065 ;
     RECT  2.16 43.335 20.844 43.605 ;
     RECT  199.692 43.335 218.16 43.605 ;
     RECT  2.16 43.875 20.844 44.145 ;
     RECT  199.692 43.875 218.16 44.145 ;
     RECT  2.16 44.415 20.844 44.685 ;
     RECT  199.692 44.415 218.16 44.685 ;
     RECT  2.16 44.955 20.844 45.225 ;
     RECT  199.692 44.955 218.16 45.225 ;
     RECT  2.16 45.495 20.844 45.765 ;
     RECT  199.692 45.495 218.16 45.765 ;
     RECT  2.16 46.035 20.844 46.305 ;
     RECT  199.692 46.035 218.16 46.305 ;
     RECT  2.16 46.575 20.844 46.845 ;
     RECT  199.692 46.575 218.16 46.845 ;
     RECT  2.16 47.115 20.844 47.385 ;
     RECT  199.692 47.115 218.16 47.385 ;
     RECT  2.16 47.655 20.844 47.925 ;
     RECT  199.692 47.655 218.16 47.925 ;
     RECT  2.16 48.195 20.844 48.465 ;
     RECT  199.692 48.195 218.16 48.465 ;
     RECT  2.16 48.735 20.844 49.005 ;
     RECT  199.692 48.735 218.16 49.005 ;
     RECT  2.16 49.275 20.844 49.545 ;
     RECT  199.692 49.275 218.16 49.545 ;
     RECT  2.16 49.815 20.844 50.085 ;
     RECT  199.692 49.815 218.16 50.085 ;
     RECT  2.16 50.355 20.844 50.625 ;
     RECT  199.692 50.355 218.16 50.625 ;
     RECT  2.16 50.895 20.844 51.165 ;
     RECT  199.692 50.895 218.16 51.165 ;
     RECT  2.16 51.435 20.844 51.705 ;
     RECT  199.692 51.435 218.16 51.705 ;
     RECT  2.16 51.975 20.844 52.245 ;
     RECT  199.692 51.975 218.16 52.245 ;
     RECT  2.16 52.515 20.844 52.785 ;
     RECT  199.692 52.515 218.16 52.785 ;
     RECT  2.16 53.055 20.844 53.325 ;
     RECT  199.692 53.055 218.16 53.325 ;
     RECT  2.16 53.595 20.844 53.865 ;
     RECT  199.692 53.595 218.16 53.865 ;
     RECT  2.16 54.135 20.844 54.405 ;
     RECT  199.692 54.135 218.16 54.405 ;
     RECT  2.16 54.675 20.844 54.945 ;
     RECT  199.692 54.675 218.16 54.945 ;
     RECT  2.16 55.215 20.844 55.485 ;
     RECT  199.692 55.215 218.16 55.485 ;
     RECT  2.16 55.755 20.844 56.025 ;
     RECT  199.692 55.755 218.16 56.025 ;
     RECT  2.16 56.295 20.844 56.565 ;
     RECT  199.692 56.295 218.16 56.565 ;
     RECT  2.16 56.835 20.844 57.105 ;
     RECT  199.692 56.835 218.16 57.105 ;
     RECT  2.16 57.375 20.844 57.645 ;
     RECT  199.692 57.375 218.16 57.645 ;
     RECT  2.16 57.915 20.844 58.185 ;
     RECT  199.692 57.915 218.16 58.185 ;
     RECT  2.16 58.455 20.844 58.725 ;
     RECT  199.692 58.455 218.16 58.725 ;
     RECT  2.16 58.995 20.844 59.265 ;
     RECT  199.692 58.995 218.16 59.265 ;
     RECT  2.16 59.535 20.844 59.805 ;
     RECT  199.692 59.535 218.16 59.805 ;
     RECT  2.16 60.075 20.844 60.345 ;
     RECT  199.692 60.075 218.16 60.345 ;
     RECT  2.16 60.615 20.844 60.885 ;
     RECT  199.692 60.615 218.16 60.885 ;
     RECT  2.16 61.155 20.844 61.425 ;
     RECT  199.692 61.155 218.16 61.425 ;
     RECT  2.16 61.695 20.844 61.965 ;
     RECT  199.692 61.695 218.16 61.965 ;
     RECT  2.16 62.235 20.844 62.505 ;
     RECT  199.692 62.235 218.16 62.505 ;
     RECT  2.16 62.775 20.844 63.045 ;
     RECT  199.692 62.775 218.16 63.045 ;
     RECT  2.16 63.315 20.844 63.585 ;
     RECT  199.692 63.315 218.16 63.585 ;
     RECT  2.16 63.855 20.844 64.125 ;
     RECT  199.692 63.855 218.16 64.125 ;
     RECT  2.16 64.395 20.844 64.665 ;
     RECT  199.692 64.395 218.16 64.665 ;
     RECT  2.16 64.935 20.844 65.205 ;
     RECT  199.692 64.935 218.16 65.205 ;
     RECT  2.16 65.475 20.844 65.745 ;
     RECT  199.692 65.475 218.16 65.745 ;
     RECT  2.16 66.015 20.844 66.285 ;
     RECT  199.692 66.015 218.16 66.285 ;
     RECT  2.16 66.555 20.844 66.825 ;
     RECT  199.692 66.555 218.16 66.825 ;
     RECT  2.16 67.095 20.844 67.365 ;
     RECT  199.692 67.095 218.16 67.365 ;
     RECT  2.16 67.635 20.844 67.905 ;
     RECT  199.692 67.635 218.16 67.905 ;
     RECT  2.16 68.175 20.844 68.445 ;
     RECT  199.692 68.175 218.16 68.445 ;
     RECT  2.16 68.715 20.844 68.985 ;
     RECT  199.692 68.715 218.16 68.985 ;
     RECT  2.16 69.255 20.844 69.525 ;
     RECT  199.692 69.255 218.16 69.525 ;
     RECT  2.16 69.795 20.844 70.065 ;
     RECT  199.692 69.795 218.16 70.065 ;
     RECT  2.16 70.335 20.844 70.605 ;
     RECT  199.692 70.335 218.16 70.605 ;
     RECT  2.16 70.875 20.844 71.145 ;
     RECT  199.692 70.875 218.16 71.145 ;
     RECT  2.16 71.415 20.844 71.685 ;
     RECT  199.692 71.415 218.16 71.685 ;
     RECT  2.16 71.955 20.844 72.225 ;
     RECT  199.692 71.955 218.16 72.225 ;
     RECT  2.16 72.495 20.844 72.765 ;
     RECT  199.692 72.495 218.16 72.765 ;
     RECT  2.16 73.035 20.844 73.305 ;
     RECT  199.692 73.035 218.16 73.305 ;
     RECT  2.16 73.575 20.844 73.845 ;
     RECT  199.692 73.575 218.16 73.845 ;
     RECT  2.16 74.115 20.844 74.385 ;
     RECT  199.692 74.115 218.16 74.385 ;
     RECT  2.16 74.655 20.844 74.925 ;
     RECT  199.692 74.655 218.16 74.925 ;
     RECT  2.16 75.195 20.844 75.465 ;
     RECT  199.692 75.195 218.16 75.465 ;
     RECT  2.16 75.735 20.844 76.005 ;
     RECT  199.692 75.735 218.16 76.005 ;
     RECT  2.16 76.275 20.844 76.545 ;
     RECT  199.692 76.275 218.16 76.545 ;
     RECT  2.16 76.815 20.844 77.085 ;
     RECT  199.692 76.815 218.16 77.085 ;
     RECT  2.16 77.355 20.844 77.625 ;
     RECT  199.692 77.355 218.16 77.625 ;
     RECT  2.16 77.895 20.844 78.165 ;
     RECT  199.692 77.895 218.16 78.165 ;
     RECT  2.16 78.435 20.844 78.705 ;
     RECT  199.692 78.435 218.16 78.705 ;
     RECT  2.16 78.975 20.844 79.245 ;
     RECT  199.692 78.975 218.16 79.245 ;
     RECT  2.16 79.515 20.844 79.785 ;
     RECT  199.692 79.515 218.16 79.785 ;
     RECT  2.16 80.055 20.844 80.325 ;
     RECT  199.692 80.055 218.16 80.325 ;
     RECT  2.16 80.595 20.844 80.865 ;
     RECT  199.692 80.595 218.16 80.865 ;
     RECT  2.16 81.135 20.844 81.405 ;
     RECT  199.692 81.135 218.16 81.405 ;
     RECT  2.16 81.675 20.844 81.945 ;
     RECT  199.692 81.675 218.16 81.945 ;
     RECT  2.16 82.215 20.844 82.485 ;
     RECT  199.692 82.215 218.16 82.485 ;
     RECT  2.16 82.755 20.844 83.025 ;
     RECT  199.692 82.755 218.16 83.025 ;
     RECT  2.16 83.295 20.844 83.565 ;
     RECT  199.692 83.295 218.16 83.565 ;
     RECT  2.16 83.835 20.844 84.105 ;
     RECT  199.692 83.835 218.16 84.105 ;
     RECT  2.16 84.375 20.844 84.645 ;
     RECT  199.692 84.375 218.16 84.645 ;
     RECT  2.16 84.915 20.844 85.185 ;
     RECT  199.692 84.915 218.16 85.185 ;
     RECT  2.16 85.455 20.844 85.725 ;
     RECT  199.692 85.455 218.16 85.725 ;
     RECT  2.16 85.995 20.844 86.265 ;
     RECT  199.692 85.995 218.16 86.265 ;
     RECT  2.16 86.535 20.844 86.805 ;
     RECT  199.692 86.535 218.16 86.805 ;
     RECT  2.16 87.075 20.844 87.345 ;
     RECT  199.692 87.075 218.16 87.345 ;
     RECT  2.16 87.615 20.844 87.885 ;
     RECT  199.692 87.615 218.16 87.885 ;
     RECT  2.16 88.155 20.844 88.425 ;
     RECT  199.692 88.155 218.16 88.425 ;
     RECT  2.16 88.695 20.844 88.965 ;
     RECT  199.692 88.695 218.16 88.965 ;
     RECT  2.16 89.235 20.844 89.505 ;
     RECT  199.692 89.235 218.16 89.505 ;
     RECT  2.16 89.775 20.844 90.045 ;
     RECT  199.692 89.775 218.16 90.045 ;
     RECT  2.16 90.315 20.844 90.585 ;
     RECT  199.692 90.315 218.16 90.585 ;
     RECT  2.16 90.855 20.844 91.125 ;
     RECT  199.692 90.855 218.16 91.125 ;
     RECT  2.16 91.395 20.844 91.665 ;
     RECT  199.692 91.395 218.16 91.665 ;
     RECT  2.16 91.935 20.844 92.205 ;
     RECT  199.692 91.935 218.16 92.205 ;
     RECT  2.16 92.475 20.844 92.745 ;
     RECT  199.692 92.475 218.16 92.745 ;
     RECT  2.16 93.015 20.844 93.285 ;
     RECT  199.692 93.015 218.16 93.285 ;
     RECT  2.16 93.555 20.844 93.825 ;
     RECT  199.692 93.555 218.16 93.825 ;
     RECT  2.16 94.095 20.844 94.365 ;
     RECT  199.692 94.095 218.16 94.365 ;
     RECT  2.16 94.635 20.844 94.905 ;
     RECT  199.692 94.635 218.16 94.905 ;
     RECT  2.16 95.175 20.844 95.445 ;
     RECT  199.692 95.175 218.16 95.445 ;
     RECT  2.16 95.715 20.844 95.985 ;
     RECT  199.692 95.715 218.16 95.985 ;
     RECT  2.16 96.255 20.844 96.525 ;
     RECT  199.692 96.255 218.16 96.525 ;
     RECT  2.16 96.795 20.844 97.065 ;
     RECT  199.692 96.795 218.16 97.065 ;
     RECT  2.16 97.335 20.844 97.605 ;
     RECT  199.692 97.335 218.16 97.605 ;
     RECT  2.16 97.875 20.844 98.145 ;
     RECT  199.692 97.875 218.16 98.145 ;
     RECT  2.16 98.415 20.844 98.685 ;
     RECT  199.692 98.415 218.16 98.685 ;
     RECT  2.16 98.955 20.844 99.225 ;
     RECT  199.692 98.955 218.16 99.225 ;
     RECT  2.16 99.495 20.844 99.765 ;
     RECT  199.692 99.495 218.16 99.765 ;
     RECT  2.16 100.035 20.844 100.305 ;
     RECT  199.692 100.035 218.16 100.305 ;
     RECT  2.16 100.575 20.844 100.71 ;
     RECT  199.692 100.575 218.16 100.71 ;
     RECT  2.16 100.71 218.16 100.845 ;
     RECT  2.16 101.115 218.16 101.385 ;
     RECT  2.16 101.655 218.16 101.925 ;
     RECT  2.16 102.195 218.16 102.465 ;
     RECT  2.16 102.735 218.16 103.005 ;
     RECT  2.16 103.275 218.16 103.545 ;
     RECT  2.16 103.815 218.16 104.085 ;
     RECT  2.16 104.355 218.16 104.625 ;
     RECT  2.16 104.895 218.16 105.165 ;
     RECT  2.16 105.435 218.16 105.705 ;
     RECT  2.16 105.975 218.16 106.245 ;
     RECT  2.16 106.515 218.16 106.785 ;
     RECT  2.16 107.055 218.16 107.325 ;
     RECT  2.16 107.595 218.16 107.865 ;
     RECT  2.16 108.135 218.16 108.405 ;
     RECT  2.16 108.675 218.16 108.945 ;
     RECT  2.16 109.215 218.16 109.485 ;
     RECT  2.16 109.755 218.16 110.025 ;
     RECT  2.16 110.295 218.16 110.565 ;
     RECT  2.16 110.835 218.16 111.105 ;
     RECT  2.16 111.375 218.16 111.645 ;
     RECT  2.16 111.915 218.16 112.185 ;
     RECT  2.16 112.455 218.16 112.725 ;
     RECT  2.16 112.995 218.16 113.265 ;
     RECT  2.16 113.535 218.16 113.805 ;
     RECT  2.16 114.075 218.16 114.345 ;
     RECT  2.16 114.615 218.16 114.885 ;
     RECT  2.16 115.155 218.16 115.425 ;
     RECT  2.16 115.695 218.16 115.965 ;
     RECT  2.16 116.235 218.16 116.505 ;
     RECT  2.16 116.775 218.16 117.045 ;
     RECT  2.16 117.315 218.16 117.585 ;
     RECT  2.16 117.855 218.16 118.125 ;
     RECT  2.16 118.395 218.16 118.665 ;
     RECT  2.16 118.935 218.16 119.205 ;
     RECT  2.16 119.475 218.16 119.745 ;
     RECT  2.16 120.015 218.16 120.285 ;
     RECT  2.16 120.555 218.16 120.825 ;
     RECT  2.16 121.095 218.16 121.365 ;
     RECT  2.16 121.635 218.16 121.905 ;
     RECT  2.16 122.175 218.16 122.445 ;
     RECT  2.16 122.715 218.16 122.985 ;
    LAYER M1 ;
     RECT  2.16 2.151 218.16 25.929 ;
     RECT  22.896 28.08 197.64 98.55 ;
     RECT  2.16 25.929 20.844 100.701 ;
     RECT  199.692 25.929 218.16 100.701 ;
     RECT  2.16 100.701 218.16 123.129 ;
    LAYER M2 ;
     RECT  0.103 29.34 0.139 30.06 ;
     RECT  0.103 32.274 0.139 32.292 ;
     RECT  0.103 33.426 0.139 36.036 ;
     RECT  0.103 37.206 0.139 38.466 ;
     RECT  0.103 39.222 0.139 39.24 ;
     RECT  0.103 40.41 0.139 40.428 ;
     RECT  0.103 54.684 0.139 55.242 ;
     RECT  0.103 60.624 0.139 60.642 ;
     RECT  0.103 61.902 0.139 63.954 ;
     RECT  0.139 29.34 0.175 30.132 ;
     RECT  0.139 54.684 0.175 55.44 ;
     RECT  0.139 60.048 0.239 61.11 ;
     RECT  0.139 37.206 0.275 40.428 ;
     RECT  0.103 56.466 0.275 56.484 ;
     RECT  0.103 31.122 0.535 31.41 ;
     RECT  0.139 32.274 0.535 32.328 ;
     RECT  0.139 33.318 0.535 36.036 ;
     RECT  0.103 57.96 0.535 59.094 ;
     RECT  0.239 60.048 0.535 60.066 ;
     RECT  0.139 61.902 0.535 64.224 ;
     RECT  0.319 67.842 0.535 67.86 ;
     RECT  0.175 54.684 0.823 55.71 ;
     RECT  0.275 40.374 1.147 40.428 ;
     RECT  0.535 61.902 1.147 64.764 ;
     RECT  0.139 65.52 1.147 65.538 ;
     RECT  0.535 67.644 1.147 67.86 ;
     RECT  1.147 41.922 1.183 41.94 ;
     RECT  1.147 67.302 1.183 67.86 ;
     RECT  1.183 41.922 1.219 42.21 ;
     RECT  1.147 40.374 1.283 40.968 ;
     RECT  0.103 66.492 1.291 66.51 ;
     RECT  1.183 67.302 1.291 68.13 ;
     RECT  1.283 40.374 1.319 40.896 ;
     RECT  1.219 41.922 1.327 42.282 ;
     RECT  1.327 41.922 1.399 42.552 ;
     RECT  0.823 54.648 1.723 55.71 ;
     RECT  0.239 61.092 1.723 61.11 ;
     RECT  0.103 46.584 1.759 47.88 ;
     RECT  1.723 54.378 1.795 55.71 ;
     RECT  0.275 37.206 2.155 39.312 ;
     RECT  0.175 28.962 2.16 30.132 ;
     RECT  0.535 31.122 2.16 32.328 ;
     RECT  0.535 33.318 2.16 36.378 ;
     RECT  2.155 37.206 2.16 39.51 ;
     RECT  1.319 40.374 2.16 40.428 ;
     RECT  1.399 41.922 2.16 42.588 ;
     RECT  1.759 46.35 2.16 47.88 ;
     RECT  1.795 54.342 2.16 55.71 ;
     RECT  1.147 57.006 2.16 57.024 ;
     RECT  0.535 57.96 2.16 60.066 ;
     RECT  1.723 60.93 2.16 61.11 ;
     RECT  1.147 61.902 2.16 65.538 ;
     RECT  1.291 66.492 2.16 68.13 ;
     RECT  2.16 2.151 20.844 123.129 ;
     RECT  20.844 30.456 21.587 68.742 ;
     RECT  21.587 30.456 21.623 37.044 ;
     RECT  21.587 37.836 21.731 68.742 ;
     RECT  21.623 33.66 21.839 37.044 ;
     RECT  20.844 70.956 21.947 70.974 ;
     RECT  20.844 76.176 21.983 76.194 ;
     RECT  20.844 76.986 22.019 77.004 ;
     RECT  20.844 84.816 22.055 84.834 ;
     RECT  21.731 37.836 22.091 67.32 ;
     RECT  20.844 95.184 22.091 96.624 ;
     RECT  22.091 38.79 22.163 39.204 ;
     RECT  22.091 39.996 22.163 67.32 ;
     RECT  20.844 2.151 22.896 29.484 ;
     RECT  21.623 30.456 22.896 32.904 ;
     RECT  21.839 34.2 22.896 37.044 ;
     RECT  22.091 37.836 22.896 38.034 ;
     RECT  22.163 38.916 22.896 39.204 ;
     RECT  22.163 40.176 22.896 67.32 ;
     RECT  21.731 68.076 22.896 68.742 ;
     RECT  20.844 83.502 22.896 83.556 ;
     RECT  20.844 89.748 22.896 89.766 ;
     RECT  22.091 95.184 22.896 95.472 ;
     RECT  22.091 96.606 22.896 96.624 ;
     RECT  20.844 97.506 22.896 97.524 ;
     RECT  20.844 98.316 22.896 123.129 ;
     RECT  22.896 2.151 78.503 123.129 ;
     RECT  78.503 2.151 82.687 26.28 ;
     RECT  78.503 27.072 82.687 123.129 ;
     RECT  82.687 2.151 197.64 123.129 ;
     RECT  197.64 52.866 197.771 53.424 ;
     RECT  197.64 60.66 197.771 62.694 ;
     RECT  197.64 41.616 197.807 43.164 ;
     RECT  197.807 41.616 197.879 42.354 ;
     RECT  197.771 60.66 197.915 61.299 ;
     RECT  197.64 44.856 198.275 45.414 ;
     RECT  197.64 68.076 198.383 71.64 ;
     RECT  197.64 54.954 198.391 58.914 ;
     RECT  197.64 78.786 198.391 78.804 ;
     RECT  197.64 48.276 198.491 48.996 ;
     RECT  197.915 60.66 198.499 61.254 ;
     RECT  198.391 78.786 198.535 79.434 ;
     RECT  198.463 80.298 198.535 80.316 ;
     RECT  197.64 73.242 198.607 73.26 ;
     RECT  198.607 73.242 198.643 74.142 ;
     RECT  197.64 75.546 198.679 75.564 ;
     RECT  197.64 76.752 198.715 76.77 ;
     RECT  197.64 64.026 198.751 67.086 ;
     RECT  198.715 76.752 198.751 77.454 ;
     RECT  198.535 78.786 198.751 80.316 ;
     RECT  197.771 52.866 198.787 53.352 ;
     RECT  198.643 72.972 198.787 74.142 ;
     RECT  197.64 46.476 198.823 46.494 ;
     RECT  197.64 47.286 198.823 47.304 ;
     RECT  198.787 52.416 198.859 53.352 ;
     RECT  198.751 63.666 198.859 67.086 ;
     RECT  198.751 78.642 198.859 80.316 ;
     RECT  198.571 81.576 198.859 81.594 ;
     RECT  197.64 30.006 198.895 30.024 ;
     RECT  198.859 52.416 198.895 53.964 ;
     RECT  198.391 54.954 198.895 59.256 ;
     RECT  198.895 30.006 198.931 30.204 ;
     RECT  197.879 41.688 198.931 42.354 ;
     RECT  197.807 43.146 198.931 43.164 ;
     RECT  198.499 60.048 198.931 61.254 ;
     RECT  197.771 62.046 198.931 62.694 ;
     RECT  198.931 30.006 199.147 30.366 ;
     RECT  198.895 52.416 199.147 59.256 ;
     RECT  198.931 60.048 199.147 62.694 ;
     RECT  198.679 75.168 199.147 75.654 ;
     RECT  198.751 76.752 199.147 77.544 ;
     RECT  198.491 48.276 199.435 48.879 ;
     RECT  197.64 35.586 199.471 35.604 ;
     RECT  197.64 39.456 199.471 40.284 ;
     RECT  198.823 46.476 199.471 47.304 ;
     RECT  199.435 48.276 199.471 49.464 ;
     RECT  198.859 63.666 199.471 67.194 ;
     RECT  199.471 46.476 199.507 49.464 ;
     RECT  197.64 50.526 199.507 50.544 ;
     RECT  199.435 51.516 199.507 51.534 ;
     RECT  199.147 52.416 199.507 62.694 ;
     RECT  199.471 63.594 199.507 67.194 ;
     RECT  197.64 2.151 199.579 28.944 ;
     RECT  199.147 29.736 199.579 30.366 ;
     RECT  198.931 41.688 199.579 43.164 ;
     RECT  198.275 45.306 199.579 45.414 ;
     RECT  199.507 46.476 199.579 50.544 ;
     RECT  199.147 75.168 199.579 77.544 ;
     RECT  198.859 78.642 199.579 81.594 ;
     RECT  199.471 35.136 199.615 35.604 ;
     RECT  197.64 44.046 199.651 44.064 ;
     RECT  199.579 45.306 199.651 50.544 ;
     RECT  198.787 72.972 199.651 74.304 ;
     RECT  199.579 75.168 199.651 81.594 ;
     RECT  199.579 2.151 199.692 30.366 ;
     RECT  197.64 31.266 199.692 32.454 ;
     RECT  199.615 34.596 199.692 35.604 ;
     RECT  197.64 36.486 199.692 36.504 ;
     RECT  198.895 37.476 199.692 37.494 ;
     RECT  197.64 38.556 199.692 38.574 ;
     RECT  199.471 39.456 199.692 40.464 ;
     RECT  199.579 41.616 199.692 43.164 ;
     RECT  199.651 44.046 199.692 50.724 ;
     RECT  199.507 51.516 199.692 62.694 ;
     RECT  199.507 63.486 199.692 67.194 ;
     RECT  198.383 68.256 199.692 71.64 ;
     RECT  199.651 72.972 199.692 81.774 ;
     RECT  198.823 83.106 199.692 83.664 ;
     RECT  197.64 98.316 199.692 123.129 ;
     RECT  199.692 2.151 218.16 123.129 ;
     RECT  218.16 27.684 218.255 29.934 ;
     RECT  218.16 57.816 218.255 60.264 ;
     RECT  218.255 29.538 218.291 29.934 ;
     RECT  218.16 44.658 218.327 57.024 ;
     RECT  218.16 30.771 218.399 43.794 ;
     RECT  218.399 30.888 218.831 43.794 ;
     RECT  218.255 57.996 218.831 60.264 ;
     RECT  218.291 29.916 218.867 29.934 ;
     RECT  218.831 41.076 218.867 43.794 ;
     RECT  218.831 58.626 218.867 60.264 ;
     RECT  218.831 30.888 218.903 40.284 ;
     RECT  218.327 46.476 219.371 57.024 ;
     RECT  218.903 30.888 219.407 38.502 ;
     RECT  219.407 30.888 219.443 34.884 ;
     RECT  219.407 35.748 219.443 38.502 ;
     RECT  218.903 39.6 219.443 40.284 ;
     RECT  219.371 46.476 219.443 53.514 ;
     RECT  219.371 54.306 219.443 57.024 ;
     RECT  219.443 30.888 219.479 31.554 ;
     RECT  219.443 32.58 219.479 34.794 ;
     RECT  219.443 35.946 219.479 38.502 ;
     RECT  218.327 44.856 219.479 45.684 ;
     RECT  219.443 46.476 219.479 47.106 ;
     RECT  219.443 48.591 219.479 53.199 ;
     RECT  218.255 27.684 219.515 28.782 ;
     RECT  219.479 45.198 219.515 45.684 ;
     RECT  219.515 45.666 219.551 45.684 ;
     RECT  219.515 27.684 219.587 28.746 ;
     RECT  219.487 30.456 219.587 30.474 ;
     RECT  219.587 27.684 219.623 28.278 ;
     RECT  219.623 28.26 219.659 28.278 ;
     RECT  218.867 41.148 220.055 43.794 ;
     RECT  219.443 55.188 220.063 57.024 ;
     RECT  218.867 58.806 220.063 60.264 ;
     RECT  220.055 42.336 220.091 43.794 ;
     RECT  219.479 35.982 220.099 38.502 ;
     RECT  219.443 39.6 220.127 40.014 ;
     RECT  220.063 55.188 220.127 57.096 ;
     RECT  220.099 35.982 220.163 38.736 ;
     RECT  220.127 39.996 220.163 40.014 ;
     RECT  220.055 41.148 220.163 41.274 ;
     RECT  220.091 42.966 220.163 43.794 ;
     RECT  219.479 49.716 220.163 53.199 ;
     RECT  219.443 54.306 220.163 54.396 ;
     RECT  220.127 56.538 220.163 57.096 ;
     RECT  220.063 58.698 220.163 60.264 ;
     RECT  219.479 32.58 220.199 32.994 ;
     RECT  219.479 33.786 220.199 34.794 ;
     RECT  220.163 35.982 220.199 36.504 ;
     RECT  220.163 37.368 220.199 38.736 ;
     RECT  220.163 41.148 220.199 41.166 ;
     RECT  220.163 42.966 220.199 43.704 ;
     RECT  219.479 48.591 220.199 48.726 ;
     RECT  220.163 49.716 220.199 50.418 ;
     RECT  220.163 51.336 220.199 53.199 ;
     RECT  220.127 55.188 220.199 55.584 ;
     RECT  220.163 59.616 220.199 60.264 ;
     RECT  219.479 31.536 220.235 31.554 ;
     RECT  220.199 32.58 220.235 32.598 ;
     RECT  220.199 33.786 220.235 34.254 ;
     RECT  220.199 35.982 220.235 36.072 ;
     RECT  220.199 37.368 220.235 38.502 ;
     RECT  220.199 42.966 220.235 42.984 ;
     RECT  220.199 48.591 220.235 48.609 ;
     RECT  220.199 49.896 220.235 50.418 ;
     RECT  220.199 52.056 220.235 53.199 ;
     RECT  220.163 54.306 220.235 54.324 ;
     RECT  220.199 55.566 220.235 55.584 ;
     RECT  220.163 57.006 220.235 57.096 ;
     RECT  220.163 58.698 220.235 58.824 ;
     RECT  220.235 34.236 220.307 34.254 ;
     RECT  220.235 36.054 220.307 36.072 ;
     RECT  220.235 57.078 220.307 57.096 ;
     RECT  220.199 60.246 220.307 60.264 ;
    LAYER M3 ;
     RECT  2.415 2.143 2.505 2.413 ;
     RECT  7.815 2.143 7.905 2.413 ;
     RECT  13.215 2.143 13.305 2.413 ;
     RECT  18.615 2.143 18.705 2.413 ;
     RECT  24.015 2.143 24.105 2.413 ;
     RECT  29.415 2.143 29.505 2.413 ;
     RECT  34.815 2.143 34.905 2.413 ;
     RECT  40.215 2.143 40.305 2.413 ;
     RECT  45.615 2.143 45.705 2.413 ;
     RECT  51.015 2.143 51.105 2.413 ;
     RECT  56.415 2.143 56.505 2.413 ;
     RECT  61.815 2.143 61.905 2.413 ;
     RECT  67.215 2.143 67.305 2.413 ;
     RECT  72.615 2.143 72.705 2.413 ;
     RECT  78.015 2.143 78.105 2.413 ;
     RECT  83.415 2.143 83.505 2.413 ;
     RECT  88.815 2.143 88.905 2.413 ;
     RECT  94.215 2.143 94.305 2.413 ;
     RECT  99.615 2.143 99.705 2.413 ;
     RECT  105.015 2.143 105.105 2.413 ;
     RECT  110.415 2.143 110.505 2.413 ;
     RECT  115.815 2.143 115.905 2.413 ;
     RECT  121.215 2.143 121.305 2.413 ;
     RECT  126.615 2.143 126.705 2.413 ;
     RECT  132.015 2.143 132.105 2.413 ;
     RECT  137.415 2.143 137.505 2.413 ;
     RECT  142.815 2.143 142.905 2.413 ;
     RECT  148.215 2.143 148.305 2.413 ;
     RECT  153.615 2.143 153.705 2.413 ;
     RECT  159.015 2.143 159.105 2.413 ;
     RECT  164.415 2.143 164.505 2.413 ;
     RECT  169.815 2.143 169.905 2.413 ;
     RECT  175.215 2.143 175.305 2.413 ;
     RECT  180.615 2.143 180.705 2.413 ;
     RECT  186.015 2.143 186.105 2.413 ;
     RECT  191.415 2.143 191.505 2.413 ;
     RECT  196.815 2.143 196.905 2.413 ;
     RECT  202.215 2.143 202.305 2.413 ;
     RECT  207.615 2.143 207.705 2.413 ;
     RECT  213.015 2.143 213.105 2.413 ;
     RECT  67.215 2.413 67.497 16.363 ;
     RECT  88.815 2.413 89.097 16.771 ;
     RECT  88.452 16.771 89.097 16.829 ;
     RECT  87.336 16.795 87.354 16.835 ;
     RECT  88.815 16.829 89.097 16.843 ;
     RECT  90.036 16.771 90.054 16.877 ;
     RECT  66.96 16.363 67.59 17.117 ;
     RECT  78.015 2.413 78.297 17.311 ;
     RECT  99.615 2.413 99.897 17.311 ;
     RECT  110.415 2.413 110.697 17.311 ;
     RECT  121.215 2.413 121.497 17.311 ;
     RECT  132.015 2.413 132.297 17.311 ;
     RECT  142.815 2.413 143.097 17.311 ;
     RECT  153.615 2.413 153.897 17.311 ;
     RECT  164.415 2.413 164.697 17.311 ;
     RECT  175.215 2.413 175.497 17.311 ;
     RECT  186.015 2.413 186.297 17.311 ;
     RECT  94.215 2.413 94.497 17.323 ;
     RECT  77.904 17.311 78.297 17.357 ;
     RECT  99.504 17.311 99.897 17.357 ;
     RECT  110.304 17.311 110.697 17.357 ;
     RECT  121.104 17.311 121.497 17.357 ;
     RECT  131.904 17.311 132.297 17.357 ;
     RECT  142.704 17.311 143.097 17.357 ;
     RECT  153.504 17.311 153.897 17.357 ;
     RECT  164.304 17.311 164.697 17.357 ;
     RECT  175.104 17.311 175.497 17.357 ;
     RECT  185.904 17.311 186.297 17.357 ;
     RECT  88.815 16.843 89.298 17.419 ;
     RECT  86.652 17.323 86.67 17.453 ;
     RECT  94.215 17.323 94.626 17.453 ;
     RECT  194.364 16.939 194.382 17.453 ;
     RECT  90.9 17.419 90.918 17.456 ;
     RECT  88.815 17.419 89.802 17.519 ;
     RECT  66.96 17.117 67.497 17.995 ;
     RECT  85.572 18.121 85.59 18.173 ;
     RECT  86.688 18.139 86.706 18.185 ;
     RECT  65.484 17.083 65.502 18.187 ;
     RECT  61.815 2.413 62.097 18.667 ;
     RECT  178.128 18.661 178.434 18.701 ;
     RECT  85.14 18.661 85.158 18.749 ;
     RECT  86.256 18.715 86.274 18.761 ;
     RECT  61.815 18.667 62.19 18.797 ;
     RECT  178.128 18.701 178.146 18.797 ;
     RECT  83.415 2.413 83.697 18.955 ;
     RECT  85.212 18.931 85.23 18.989 ;
     RECT  83.415 18.955 84.114 18.995 ;
     RECT  83.415 18.995 83.697 19.237 ;
     RECT  11.412 19.237 11.43 19.277 ;
     RECT  82.224 19.201 82.242 19.277 ;
     RECT  13.215 2.413 13.497 19.336 ;
     RECT  65.448 18.187 65.502 19.339 ;
     RECT  12.6 19.336 13.497 19.373 ;
     RECT  199.224 19.345 199.242 19.471 ;
     RECT  83.34 19.237 83.697 19.741 ;
     RECT  75.024 17.611 75.042 19.769 ;
     RECT  95.976 19.345 95.994 19.769 ;
     RECT  19.836 19.507 19.854 19.777 ;
     RECT  78.015 17.357 78.297 19.777 ;
     RECT  83.196 19.741 83.697 19.777 ;
     RECT  80.388 19.741 80.406 19.805 ;
     RECT  81.504 19.768 81.522 19.805 ;
     RECT  83.196 19.777 84.402 19.853 ;
     RECT  70.74 19.777 70.758 19.877 ;
     RECT  75.096 19.777 75.114 19.877 ;
     RECT  78.015 19.777 78.678 19.877 ;
     RECT  83.415 19.853 84.402 19.877 ;
     RECT  107.136 20.281 107.154 20.333 ;
     RECT  81.396 20.299 81.414 20.345 ;
     RECT  106.02 20.299 106.038 20.345 ;
     RECT  18.615 2.413 18.897 20.353 ;
     RECT  19.764 19.777 19.854 20.353 ;
     RECT  18.615 20.353 19.854 20.425 ;
     RECT  201.204 19.921 201.222 20.425 ;
     RECT  78.015 19.877 78.498 20.621 ;
     RECT  106.56 20.551 106.65 20.621 ;
     RECT  107.748 20.587 107.766 20.624 ;
     RECT  83.415 19.877 83.697 20.821 ;
     RECT  83.268 20.821 83.697 20.827 ;
     RECT  84.456 19.921 84.474 20.827 ;
     RECT  106.56 20.621 106.578 20.861 ;
     RECT  13.215 19.373 13.497 20.929 ;
     RECT  80.244 20.821 80.262 20.957 ;
     RECT  194.364 20.827 194.382 20.957 ;
     RECT  83.268 20.827 84.474 20.965 ;
     RECT  71.46 20.929 71.478 21.001 ;
     RECT  18.615 20.425 20.394 21.163 ;
     RECT  68.328 19.291 68.346 21.199 ;
     RECT  94.215 17.453 94.497 21.199 ;
     RECT  86.112 21.235 86.13 21.271 ;
     RECT  68.328 21.199 68.49 21.299 ;
     RECT  106.236 21.397 106.254 21.437 ;
     RECT  15.732 20.317 15.75 21.469 ;
     RECT  16.812 20.965 16.83 21.469 ;
     RECT  75.888 20.461 75.906 21.469 ;
     RECT  70.092 21.451 70.11 21.499 ;
     RECT  11.124 19.813 11.142 21.505 ;
     RECT  94.215 21.199 95.202 21.505 ;
     RECT  15.732 21.469 16.83 21.541 ;
     RECT  66.708 17.995 67.497 21.541 ;
     RECT  81.72 20.965 81.738 21.631 ;
     RECT  70.092 21.499 70.182 21.659 ;
     RECT  9.936 20.389 9.954 21.937 ;
     RECT  199.224 19.471 199.314 21.973 ;
     RECT  61.815 18.797 62.097 22.009 ;
     RECT  94.176 21.505 95.202 22.009 ;
     RECT  11.124 21.505 11.178 22.045 ;
     RECT  199.224 21.973 199.386 22.045 ;
     RECT  13.215 20.929 13.95 22.081 ;
     RECT  15.084 21.541 16.83 22.081 ;
     RECT  93.564 22.009 95.202 22.081 ;
     RECT  88.815 17.519 89.097 22.171 ;
     RECT  198.108 21.541 198.126 22.171 ;
     RECT  61.308 22.009 62.097 22.199 ;
     RECT  71.136 21.001 71.478 22.207 ;
     RECT  200.664 20.425 201.222 22.207 ;
     RECT  13.215 22.081 16.83 22.459 ;
     RECT  107.424 22.045 107.442 22.459 ;
     RECT  106.524 22.441 106.542 22.493 ;
     RECT  13.215 22.459 17.118 22.505 ;
     RECT  107.424 22.459 107.658 22.505 ;
     RECT  9.936 21.937 9.99 22.513 ;
     RECT  86.112 21.271 86.634 22.541 ;
     RECT  83.016 20.965 84.474 22.577 ;
     RECT  9.576 22.513 9.99 22.585 ;
     RECT  86.364 22.541 86.418 22.613 ;
     RECT  198.108 22.171 198.162 22.711 ;
     RECT  66.564 21.541 67.497 22.747 ;
     RECT  68.328 21.299 68.346 22.747 ;
     RECT  65.448 19.339 65.646 22.843 ;
     RECT  66.528 22.747 68.346 22.843 ;
     RECT  17.964 21.163 20.394 22.981 ;
     RECT  51.015 2.413 51.297 23.125 ;
     RECT  5.112 21.127 5.13 23.161 ;
     RECT  56.415 2.413 56.697 23.161 ;
     RECT  65.448 22.843 68.346 23.251 ;
     RECT  7.815 2.413 8.097 23.287 ;
     RECT  9.072 22.585 9.99 23.323 ;
     RECT  11.124 22.045 11.682 23.323 ;
     RECT  80.316 22.783 80.334 23.323 ;
     RECT  86.4 22.613 86.418 23.323 ;
     RECT  85.572 23.251 85.59 23.357 ;
     RECT  86.4 23.323 86.706 23.36 ;
     RECT  61.815 22.199 62.097 23.431 ;
     RECT  61.815 23.431 62.73 23.521 ;
     RECT  198.108 22.711 198.198 23.521 ;
     RECT  199.224 22.045 199.53 23.521 ;
     RECT  21.528 23.629 21.546 23.665 ;
     RECT  83.376 22.577 84.474 23.665 ;
     RECT  65.448 23.251 68.382 23.791 ;
     RECT  77.256 20.425 77.274 23.791 ;
     RECT  78.015 20.621 78.39 23.791 ;
     RECT  80.316 23.323 80.442 23.791 ;
     RECT  81.18 21.631 81.738 23.791 ;
     RECT  88.815 22.171 89.73 23.791 ;
     RECT  99.615 17.357 99.897 23.791 ;
     RECT  109.656 20.389 109.674 23.791 ;
     RECT  110.415 17.357 110.697 23.791 ;
     RECT  121.215 17.357 121.497 23.791 ;
     RECT  132.015 17.357 132.297 23.791 ;
     RECT  142.815 17.357 143.097 23.791 ;
     RECT  153.615 17.357 153.897 23.791 ;
     RECT  164.415 17.357 164.697 23.791 ;
     RECT  175.215 17.357 175.497 23.791 ;
     RECT  186.015 17.357 186.297 23.791 ;
     RECT  194.364 23.659 194.382 23.803 ;
     RECT  21.528 23.665 22.014 23.827 ;
     RECT  83.376 23.665 84.618 23.855 ;
     RECT  198.108 23.521 199.53 23.863 ;
     RECT  80.316 23.791 81.738 23.933 ;
     RECT  194.364 23.803 194.49 23.933 ;
     RECT  65.448 23.791 69.03 23.947 ;
     RECT  65.448 23.947 69.138 23.971 ;
     RECT  70.164 21.659 70.182 23.971 ;
     RECT  44.28 23.701 44.298 23.999 ;
     RECT  202.215 2.413 202.497 24.061 ;
     RECT  65.448 23.971 70.182 24.089 ;
     RECT  21.528 23.827 22.662 24.097 ;
     RECT  65.448 24.089 68.958 24.097 ;
     RECT  72.615 2.413 72.897 24.097 ;
     RECT  85.464 24.061 85.482 24.173 ;
     RECT  9.072 23.323 11.682 24.205 ;
     RECT  64.008 23.287 64.026 24.205 ;
     RECT  65.16 24.097 68.958 24.205 ;
     RECT  99.504 23.791 99.897 24.205 ;
     RECT  81.18 23.933 81.738 24.241 ;
     RECT  34.815 2.413 35.097 24.325 ;
     RECT  13.215 22.505 16.83 24.331 ;
     RECT  24.015 2.413 24.297 24.331 ;
     RECT  45.615 2.413 45.897 24.331 ;
     RECT  81.18 24.241 82.386 24.331 ;
     RECT  109.008 23.791 110.697 24.359 ;
     RECT  21.528 24.097 22.842 24.367 ;
     RECT  102.24 22.045 102.258 24.367 ;
     RECT  198.108 23.863 199.926 24.367 ;
     RECT  200.664 22.207 201.294 24.367 ;
     RECT  13.104 24.331 16.83 24.368 ;
     RECT  64.008 24.205 68.958 24.368 ;
     RECT  77.256 23.791 78.39 24.368 ;
     RECT  88.704 23.791 89.73 24.368 ;
     RECT  121.104 23.791 121.497 24.368 ;
     RECT  131.904 23.791 132.297 24.368 ;
     RECT  142.704 23.791 143.097 24.368 ;
     RECT  153.504 23.791 153.897 24.368 ;
     RECT  164.304 23.791 164.697 24.368 ;
     RECT  175.104 23.791 175.497 24.368 ;
     RECT  185.904 23.791 186.297 24.368 ;
     RECT  102.24 24.367 102.51 24.395 ;
     RECT  109.656 24.359 110.697 24.413 ;
     RECT  194.364 23.933 194.382 24.461 ;
     RECT  61.815 23.521 62.802 24.467 ;
     RECT  106.596 24.367 106.614 24.467 ;
     RECT  102.492 24.395 102.51 24.539 ;
     RECT  64.008 24.368 64.026 24.601 ;
     RECT  81.18 24.331 82.458 24.619 ;
     RECT  65.088 24.368 68.958 24.629 ;
     RECT  98.964 24.205 99.897 24.629 ;
     RECT  109.656 24.413 109.674 24.665 ;
     RECT  63.828 24.601 64.026 24.673 ;
     RECT  196.815 2.413 197.097 24.673 ;
     RECT  198.108 24.367 201.294 24.673 ;
     RECT  117.54 24.637 117.558 24.701 ;
     RECT  81.18 24.619 82.494 24.709 ;
     RECT  83.376 23.855 84.474 24.709 ;
     RECT  63.648 24.673 64.026 24.745 ;
     RECT  90.9 22.747 90.918 24.745 ;
     RECT  92.088 22.711 92.106 24.745 ;
     RECT  58.716 24.673 58.734 24.773 ;
     RECT  90.9 24.745 92.106 24.781 ;
     RECT  23.904 24.331 24.297 24.809 ;
     RECT  34.704 24.325 35.097 24.809 ;
     RECT  45.504 24.331 45.897 24.809 ;
     RECT  80.316 23.933 80.406 24.809 ;
     RECT  40.215 2.413 40.497 24.871 ;
     RECT  69.768 24.089 70.182 24.871 ;
     RECT  81.18 24.709 84.474 24.871 ;
     RECT  66.528 24.629 68.022 24.899 ;
     RECT  90.648 24.781 92.106 24.899 ;
     RECT  107.424 22.505 107.442 24.899 ;
     RECT  88.815 24.368 89.73 24.943 ;
     RECT  106.092 24.907 106.11 24.944 ;
     RECT  75.888 21.469 76.41 24.979 ;
     RECT  40.176 24.871 40.497 25.007 ;
     RECT  21.42 24.367 22.842 25.015 ;
     RECT  50.796 23.125 51.297 25.015 ;
     RECT  71.136 22.207 71.802 25.141 ;
     RECT  75.24 24.979 76.41 25.141 ;
     RECT  81.18 24.871 84.582 25.141 ;
     RECT  65.088 24.629 65.646 25.169 ;
     RECT  34.815 24.809 35.097 25.177 ;
     RECT  35.928 24.745 35.946 25.177 ;
     RECT  74.7 25.141 76.41 25.177 ;
     RECT  86.4 23.36 86.418 25.177 ;
     RECT  99.216 24.629 99.897 25.177 ;
     RECT  13.215 24.368 16.83 25.213 ;
     RECT  17.928 22.981 20.394 25.213 ;
     RECT  65.088 25.169 65.466 25.249 ;
     RECT  86.4 25.177 86.562 25.249 ;
     RECT  99.216 25.177 100.494 25.277 ;
     RECT  78.015 24.368 78.39 25.285 ;
     RECT  80.316 24.809 80.334 25.285 ;
     RECT  61.815 24.467 62.097 25.321 ;
     RECT  63.288 24.745 64.026 25.321 ;
     RECT  74.124 25.177 76.41 25.321 ;
     RECT  71.136 25.141 71.874 25.349 ;
     RECT  92.952 22.081 95.202 25.411 ;
     RECT  65.016 25.249 65.466 25.439 ;
     RECT  80.208 25.285 80.334 25.439 ;
     RECT  81.18 25.141 84.906 25.439 ;
     RECT  87.876 21.901 87.894 25.439 ;
     RECT  92.952 25.411 95.274 25.439 ;
     RECT  108.036 25.147 108.054 25.439 ;
     RECT  81.18 25.439 83.697 25.469 ;
     RECT  66.528 24.899 67.878 25.475 ;
     RECT  73.944 25.321 76.41 25.483 ;
     RECT  77.256 24.368 77.274 25.483 ;
     RECT  105.015 2.413 105.297 25.483 ;
     RECT  106.56 25.411 106.578 25.517 ;
     RECT  109.152 25.519 109.17 25.565 ;
     RECT  94.215 25.439 95.274 25.583 ;
     RECT  66.528 25.475 67.554 25.591 ;
     RECT  88.815 24.943 89.802 25.591 ;
     RECT  66.276 25.591 67.554 25.619 ;
     RECT  68.976 24.871 70.182 25.619 ;
     RECT  24.015 24.809 24.297 25.667 ;
     RECT  29.415 2.413 29.697 25.667 ;
     RECT  34.815 25.177 35.946 25.667 ;
     RECT  45.615 24.809 45.897 25.667 ;
     RECT  55.8 23.161 56.697 25.667 ;
     RECT  61.815 25.321 64.026 25.667 ;
     RECT  66.276 25.619 67.497 25.667 ;
     RECT  82.62 25.469 83.697 25.667 ;
     RECT  110.415 24.413 110.697 25.667 ;
     RECT  115.815 2.413 116.097 25.667 ;
     RECT  121.215 24.368 121.497 25.667 ;
     RECT  126.615 2.413 126.897 25.667 ;
     RECT  132.015 24.368 132.297 25.667 ;
     RECT  137.415 2.413 137.697 25.667 ;
     RECT  142.815 24.368 143.097 25.667 ;
     RECT  148.215 2.413 148.497 25.667 ;
     RECT  153.615 24.368 153.897 25.667 ;
     RECT  159.015 2.413 159.297 25.667 ;
     RECT  164.415 24.368 164.697 25.667 ;
     RECT  175.215 24.368 175.497 25.667 ;
     RECT  180.615 2.413 180.897 25.667 ;
     RECT  186.015 24.368 186.297 25.667 ;
     RECT  191.415 2.413 191.697 25.667 ;
     RECT  72.615 24.097 72.99 25.672 ;
     RECT  50.796 25.015 51.93 25.681 ;
     RECT  71.136 25.349 71.154 25.681 ;
     RECT  32.148 25.435 32.166 25.709 ;
     RECT  58.788 25.555 58.806 25.709 ;
     RECT  62.712 25.667 64.026 25.709 ;
     RECT  70.596 25.681 71.154 25.709 ;
     RECT  84.456 25.439 84.906 25.709 ;
     RECT  88.308 25.591 89.802 25.709 ;
     RECT  90.9 24.899 92.106 25.709 ;
     RECT  101.844 25.291 101.862 25.709 ;
     RECT  34.815 25.667 34.905 25.717 ;
     RECT  40.215 25.007 40.497 25.717 ;
     RECT  60.948 25.675 60.966 25.717 ;
     RECT  61.815 25.667 61.905 25.717 ;
     RECT  90.9 25.709 91.566 25.717 ;
     RECT  97.488 25.591 97.506 25.717 ;
     RECT  50.796 25.681 52.038 25.745 ;
     RECT  55.8 25.667 56.505 25.745 ;
     RECT  60.948 25.717 61.905 25.745 ;
     RECT  89.784 25.709 89.802 25.745 ;
     RECT  73.944 25.483 77.274 25.753 ;
     RECT  97.488 25.717 98.01 25.753 ;
     RECT  99.216 25.277 100.422 25.753 ;
     RECT  194.364 25.681 194.382 25.753 ;
     RECT  119.808 25.717 119.826 25.757 ;
     RECT  81.18 25.469 81.486 25.771 ;
     RECT  70.596 25.709 70.83 25.781 ;
     RECT  37.116 25.717 37.134 25.789 ;
     RECT  86.4 25.249 86.634 25.789 ;
     RECT  80.964 25.771 81.486 25.817 ;
     RECT  90.684 25.717 91.566 25.817 ;
     RECT  105.015 25.483 105.822 25.819 ;
     RECT  31.968 25.717 31.986 25.825 ;
     RECT  35.676 25.667 35.946 25.825 ;
     RECT  37.044 25.789 37.134 25.825 ;
     RECT  59.76 25.717 59.778 25.825 ;
     RECT  78.015 25.285 79.038 25.825 ;
     RECT  80.208 25.439 80.226 25.825 ;
     RECT  26.784 25.717 26.802 25.853 ;
     RECT  31.356 25.825 31.986 25.853 ;
     RECT  34.776 25.717 34.905 25.853 ;
     RECT  35.676 25.825 37.134 25.853 ;
     RECT  38.772 25.717 38.79 25.853 ;
     RECT  40.215 25.717 40.698 25.853 ;
     RECT  46.764 25.681 46.782 25.853 ;
     RECT  51.015 25.745 52.038 25.853 ;
     RECT  56.052 25.745 56.505 25.853 ;
     RECT  73.8 25.753 77.274 25.853 ;
     RECT  49.608 25.825 49.626 25.861 ;
     RECT  68.976 25.619 69.858 25.861 ;
     RECT  72.612 25.672 72.99 25.861 ;
     RECT  73.8 25.853 75.87 25.861 ;
     RECT  76.716 25.853 77.274 25.861 ;
     RECT  78.015 25.825 80.226 25.861 ;
     RECT  86.4 25.789 86.706 25.861 ;
     RECT  35.676 25.853 37.062 25.889 ;
     RECT  58.932 25.825 59.778 25.889 ;
     RECT  104.688 25.819 105.822 25.889 ;
     RECT  24.015 25.667 24.105 25.937 ;
     RECT  29.415 25.667 29.505 25.937 ;
     RECT  34.815 25.853 34.905 25.937 ;
     RECT  40.215 25.853 40.626 25.937 ;
     RECT  45.615 25.667 45.705 25.937 ;
     RECT  51.015 25.853 51.93 25.937 ;
     RECT  56.415 25.853 56.505 25.937 ;
     RECT  61.272 25.745 61.905 25.937 ;
     RECT  76.716 25.861 80.226 25.937 ;
     RECT  82.62 25.667 83.505 25.937 ;
     RECT  94.215 25.583 94.698 25.937 ;
     RECT  105.015 25.889 105.822 25.937 ;
     RECT  115.815 25.667 115.905 25.937 ;
     RECT  126.615 25.667 126.705 25.937 ;
     RECT  137.415 25.667 137.505 25.937 ;
     RECT  148.215 25.667 148.305 25.937 ;
     RECT  159.015 25.667 159.105 25.937 ;
     RECT  169.815 2.413 170.097 25.937 ;
     RECT  180.615 25.667 180.705 25.937 ;
     RECT  191.415 25.667 191.505 25.937 ;
     RECT  196.815 24.673 201.294 25.937 ;
     RECT  13.215 25.213 20.394 25.951 ;
     RECT  21.42 25.015 22.914 25.951 ;
     RECT  110.415 25.667 110.682 25.951 ;
     RECT  118.008 25.717 118.026 25.951 ;
     RECT  121.215 25.667 121.482 25.951 ;
     RECT  132.015 25.667 132.282 25.951 ;
     RECT  142.815 25.667 143.082 25.951 ;
     RECT  153.615 25.667 153.882 25.951 ;
     RECT  164.415 25.667 164.682 25.951 ;
     RECT  175.215 25.667 175.482 25.951 ;
     RECT  186.015 25.667 186.282 25.951 ;
     RECT  35.676 25.889 36.81 25.979 ;
     RECT  49.608 25.861 49.878 25.979 ;
     RECT  94.68 25.937 94.698 25.979 ;
     RECT  88.308 25.709 89.01 25.997 ;
     RECT  110.304 25.951 110.682 25.997 ;
     RECT  121.104 25.951 121.482 25.997 ;
     RECT  131.904 25.951 132.282 25.997 ;
     RECT  142.704 25.951 143.082 25.997 ;
     RECT  153.504 25.951 153.882 25.997 ;
     RECT  164.304 25.951 164.682 25.997 ;
     RECT  175.104 25.951 175.482 25.997 ;
     RECT  185.904 25.951 186.282 25.997 ;
     RECT  36.252 25.979 36.81 26.015 ;
     RECT  51.48 25.937 51.93 26.015 ;
     RECT  97.488 25.753 100.422 26.015 ;
     RECT  81.468 25.817 81.486 26.045 ;
     RECT  40.356 25.937 40.626 26.051 ;
     RECT  54.792 25.861 54.81 26.051 ;
     RECT  61.272 25.937 61.29 26.051 ;
     RECT  86.04 25.861 86.778 26.051 ;
     RECT  98.676 26.015 100.422 26.051 ;
     RECT  106.596 25.861 107.73 26.051 ;
     RECT  110.664 25.997 110.682 26.051 ;
     RECT  118.008 25.951 118.602 26.051 ;
     RECT  121.464 25.997 121.482 26.051 ;
     RECT  130.536 25.951 130.554 26.051 ;
     RECT  132.264 25.997 132.282 26.051 ;
     RECT  138.528 25.951 138.546 26.051 ;
     RECT  143.064 25.997 143.082 26.051 ;
     RECT  150.48 25.951 150.498 26.051 ;
     RECT  153.864 25.997 153.882 26.051 ;
     RECT  162.468 25.951 162.486 26.051 ;
     RECT  164.664 25.997 164.682 26.051 ;
     RECT  170.424 25.951 170.442 26.051 ;
     RECT  175.464 25.997 175.482 26.051 ;
     RECT  182.412 25.951 182.43 26.051 ;
     RECT  186.264 25.997 186.282 26.051 ;
     RECT  76.716 25.937 77.454 26.093 ;
     RECT  78.192 25.937 80.226 26.093 ;
     RECT  106.992 26.051 107.73 26.093 ;
     RECT  30.348 25.861 30.366 26.123 ;
     RECT  51.876 26.015 51.93 26.123 ;
     RECT  97.488 26.015 97.938 26.123 ;
     RECT  194.364 25.753 194.454 26.123 ;
     RECT  105.804 25.937 105.822 26.141 ;
     RECT  36.468 26.015 36.81 26.159 ;
     RECT  86.04 26.051 86.058 26.159 ;
     RECT  194.364 26.123 194.382 26.189 ;
     RECT  62.712 25.709 63.594 26.204 ;
     RECT  70.668 25.781 70.83 26.204 ;
     RECT  76.716 26.093 77.418 26.204 ;
     RECT  82.62 25.937 83.286 26.204 ;
     RECT  51.876 26.123 51.894 26.249 ;
     RECT  82.692 26.204 83.286 26.249 ;
     RECT  90.972 25.817 91.566 26.285 ;
     RECT  40.356 26.051 40.374 26.429 ;
     RECT  13.215 25.951 22.914 26.474 ;
     RECT  58.932 25.889 59.706 26.477 ;
     RECT  9.072 24.205 12.366 26.491 ;
     RECT  73.728 25.861 75.87 26.519 ;
     RECT  82.692 26.249 83.214 26.519 ;
     RECT  78.48 26.093 80.226 26.525 ;
     RECT  4.968 23.161 5.13 26.527 ;
     RECT  6.264 24.781 6.282 26.527 ;
     RECT  63.252 26.204 63.594 26.555 ;
     RECT  82.98 26.519 83.214 26.555 ;
     RECT  78.48 26.525 79.218 26.591 ;
     RECT  99.216 26.051 99.234 26.591 ;
     RECT  100.404 26.051 100.422 26.627 ;
     RECT  76.716 26.204 77.202 26.663 ;
     RECT  58.932 26.477 59.454 26.744 ;
     RECT  66.276 25.667 67.374 26.789 ;
     RECT  4.968 26.527 6.282 26.797 ;
     RECT  197.244 25.937 201.294 26.797 ;
     RECT  202.104 24.061 202.497 26.797 ;
     RECT  197.244 26.797 202.497 26.825 ;
     RECT  31.356 25.853 31.374 27.059 ;
     RECT  4.968 26.797 6.426 27.067 ;
     RECT  72.54 25.861 72.99 27.095 ;
     RECT  79.02 26.591 79.218 27.095 ;
     RECT  73.728 26.519 75.222 27.101 ;
     RECT  73.728 27.101 74.646 27.131 ;
     RECT  84.888 25.709 84.906 27.131 ;
     RECT  3.672 24.475 3.69 27.139 ;
     RECT  4.644 27.067 6.426 27.139 ;
     RECT  80.208 26.525 80.226 27.149 ;
     RECT  66.276 26.789 66.294 27.167 ;
     RECT  88.308 25.997 88.326 27.167 ;
     RECT  82.98 26.555 82.998 27.203 ;
     RECT  97.488 26.123 97.506 27.203 ;
     RECT  73.944 27.131 74.646 27.239 ;
     RECT  118.008 26.051 118.026 27.239 ;
     RECT  70.812 26.204 70.83 27.284 ;
     RECT  68.436 25.861 69.858 27.329 ;
     RECT  3.672 27.139 6.426 27.643 ;
     RECT  7.2 23.287 8.097 27.643 ;
     RECT  197.244 26.825 201.402 27.643 ;
     RECT  202.14 26.825 202.497 27.643 ;
     RECT  217.62 27.679 217.638 27.715 ;
     RECT  215.136 27.571 215.154 27.751 ;
     RECT  217.188 27.715 217.638 27.751 ;
     RECT  216.756 27.751 217.674 27.841 ;
     RECT  3.672 27.643 8.097 27.877 ;
     RECT  8.964 26.491 12.366 27.877 ;
     RECT  216.756 27.841 217.746 27.913 ;
     RECT  216.756 27.913 218.286 28.021 ;
     RECT  13.215 26.474 22.842 28.08 ;
     RECT  36.792 26.159 36.81 28.08 ;
     RECT  49.608 25.979 49.626 28.08 ;
     RECT  58.932 26.744 58.95 28.08 ;
     RECT  63.252 26.555 63.306 28.08 ;
     RECT  64.368 25.861 64.386 28.08 ;
     RECT  67.356 26.789 67.374 28.08 ;
     RECT  68.436 27.329 69.534 28.08 ;
     RECT  72.972 27.095 72.99 28.08 ;
     RECT  74.628 27.239 74.646 28.08 ;
     RECT  76.968 26.663 77.202 28.08 ;
     RECT  79.2 27.095 79.218 28.08 ;
     RECT  91.548 26.285 91.566 28.08 ;
     RECT  96.3 25.591 96.318 28.08 ;
     RECT  197.244 27.643 202.497 28.08 ;
     RECT  219.6 27.679 219.618 28.111 ;
     RECT  216.216 28.021 218.286 28.147 ;
     RECT  204.696 28.021 204.714 28.183 ;
     RECT  219.528 28.111 219.618 28.183 ;
     RECT  2.415 2.413 2.697 28.219 ;
     RECT  219.456 28.183 219.618 28.255 ;
     RECT  2.415 28.219 2.862 28.381 ;
     RECT  3.672 27.877 12.366 28.381 ;
     RECT  216.216 28.147 218.322 28.417 ;
     RECT  2.415 28.381 12.366 28.453 ;
     RECT  214.776 27.751 215.154 28.453 ;
     RECT  216 28.417 218.322 28.453 ;
     RECT  214.776 28.453 218.322 28.687 ;
     RECT  219.456 28.255 219.654 28.687 ;
     RECT  2.34 28.453 12.366 28.795 ;
     RECT  203.904 28.831 203.922 28.921 ;
     RECT  204.696 28.183 205.074 28.921 ;
     RECT  203.544 28.921 205.074 28.993 ;
     RECT  213.015 2.413 213.297 29.029 ;
     RECT  213.015 29.029 213.39 29.065 ;
     RECT  214.776 28.687 219.654 29.065 ;
     RECT  2.304 28.795 12.366 29.069 ;
     RECT  203.544 28.993 205.254 29.101 ;
     RECT  2.34 29.069 12.366 29.191 ;
     RECT  13.215 28.08 202.497 29.191 ;
     RECT  0.18 28.957 0.198 29.263 ;
     RECT  206.568 29.101 206.586 29.299 ;
     RECT  207.615 2.413 207.897 29.299 ;
     RECT  211.932 29.101 212.238 29.299 ;
     RECT  0.18 29.263 0.558 29.323 ;
     RECT  210.816 29.065 210.834 29.335 ;
     RECT  211.896 29.299 212.238 29.335 ;
     RECT  213.015 29.065 219.654 29.335 ;
     RECT  2.34 29.191 202.497 29.371 ;
     RECT  203.544 29.101 205.614 29.371 ;
     RECT  206.568 29.299 207.897 29.371 ;
     RECT  210.816 29.335 210.978 29.371 ;
     RECT  211.86 29.335 219.654 29.371 ;
     RECT  208.98 29.371 208.998 29.419 ;
     RECT  0.108 29.323 0.558 29.453 ;
     RECT  2.34 29.371 205.614 29.461 ;
     RECT  209.88 29.335 209.898 29.533 ;
     RECT  210.816 29.371 219.654 29.533 ;
     RECT  208.872 29.419 209.034 29.731 ;
     RECT  2.34 29.461 205.83 29.803 ;
     RECT  208.872 29.731 209.142 29.803 ;
     RECT  209.88 29.533 219.654 29.803 ;
     RECT  208.872 29.803 219.654 29.837 ;
     RECT  206.568 29.371 208.026 29.839 ;
     RECT  208.872 29.837 218.034 29.839 ;
     RECT  2.304 29.803 205.83 29.911 ;
     RECT  206.568 29.839 218.034 29.911 ;
     RECT  218.844 29.837 219.654 29.933 ;
     RECT  2.304 29.911 218.034 29.939 ;
     RECT  218.844 29.933 219.582 29.939 ;
     RECT  0.108 29.453 0.198 30.065 ;
     RECT  2.304 29.939 211.41 30.065 ;
     RECT  2.304 30.065 210.906 30.181 ;
     RECT  2.268 30.181 210.906 30.317 ;
     RECT  0.144 30.065 0.198 30.379 ;
     RECT  0.144 30.379 0.378 30.509 ;
     RECT  212.184 29.939 218.034 30.76 ;
     RECT  219.456 29.939 219.582 30.763 ;
     RECT  2.304 30.317 210.906 30.811 ;
     RECT  212.184 30.76 218.394 30.811 ;
     RECT  219.456 30.763 220.158 30.859 ;
     RECT  0.144 30.509 0.342 30.893 ;
     RECT  2.304 30.811 218.394 30.947 ;
     RECT  0.144 30.893 0.162 30.955 ;
     RECT  219.456 30.859 220.23 30.989 ;
     RECT  219.456 30.989 219.474 31.085 ;
     RECT  219.42 31.147 219.438 31.153 ;
     RECT  1.152 31.387 1.17 31.487 ;
     RECT  0.108 30.955 0.162 31.723 ;
     RECT  2.304 30.947 217.89 31.792 ;
     RECT  2.304 31.792 217.926 31.801 ;
     RECT  218.844 31.153 219.438 31.801 ;
     RECT  2.304 31.801 219.438 31.919 ;
     RECT  2.304 31.919 12.366 32.035 ;
     RECT  0.108 31.723 0.594 32.045 ;
     RECT  0.108 32.045 0.558 32.141 ;
     RECT  220.212 30.989 220.23 32.203 ;
     RECT  0.108 32.141 0.342 32.297 ;
     RECT  0.144 32.297 0.342 32.333 ;
     RECT  13.104 31.919 219.438 32.525 ;
     RECT  218.844 32.525 219.438 32.611 ;
     RECT  220.176 32.203 220.23 32.611 ;
     RECT  0.216 32.333 0.342 32.717 ;
     RECT  13.104 32.525 217.962 32.729 ;
     RECT  2.268 32.035 12.366 32.809 ;
     RECT  13.104 32.729 217.926 32.809 ;
     RECT  2.268 32.809 217.926 32.909 ;
     RECT  0.108 33.067 0.162 33.341 ;
     RECT  2.304 32.909 217.926 33.655 ;
     RECT  218.844 32.611 220.23 33.655 ;
     RECT  2.304 33.655 220.23 33.965 ;
     RECT  2.304 33.965 217.998 34.205 ;
     RECT  218.88 33.965 220.23 34.231 ;
     RECT  0.108 33.341 0.126 34.315 ;
     RECT  0.108 34.315 0.558 34.457 ;
     RECT  2.304 34.205 210.834 34.457 ;
     RECT  2.304 34.457 206.514 34.685 ;
     RECT  218.88 34.231 220.302 34.799 ;
     RECT  218.88 34.799 219.474 34.829 ;
     RECT  211.68 34.205 217.998 34.933 ;
     RECT  218.88 34.829 219.438 34.933 ;
     RECT  207.468 34.457 210.834 35.131 ;
     RECT  211.68 34.933 219.438 35.131 ;
     RECT  207.468 35.131 219.438 35.275 ;
     RECT  0.108 34.457 0.126 35.371 ;
     RECT  205.956 34.685 206.514 35.401 ;
     RECT  207.288 35.275 219.438 35.401 ;
     RECT  2.304 34.685 205.218 35.437 ;
     RECT  205.956 35.401 219.438 35.437 ;
     RECT  2.304 35.437 219.438 35.465 ;
     RECT  220.212 34.799 220.302 35.563 ;
     RECT  214.02 35.465 219.438 35.659 ;
     RECT  220.176 35.563 220.302 35.659 ;
     RECT  2.304 35.465 213.297 35.803 ;
     RECT  2.232 35.803 213.297 35.843 ;
     RECT  0.108 35.371 0.162 36.041 ;
     RECT  1.152 34.795 1.17 36.043 ;
     RECT  214.02 35.659 220.302 36.077 ;
     RECT  214.02 36.077 220.23 36.149 ;
     RECT  0.54 36.043 1.17 36.239 ;
     RECT  2.304 35.843 213.297 36.247 ;
     RECT  214.02 36.149 217.962 36.247 ;
     RECT  0.54 36.239 0.558 36.383 ;
     RECT  2.304 36.247 217.962 37.003 ;
     RECT  2.196 37.003 217.962 37.157 ;
     RECT  0.108 37.099 0.126 37.195 ;
     RECT  2.268 37.157 217.962 37.387 ;
     RECT  218.844 36.149 220.23 37.387 ;
     RECT  0.108 37.195 0.342 37.421 ;
     RECT  2.268 37.387 220.23 37.805 ;
     RECT  0.108 37.421 0.234 37.853 ;
     RECT  2.304 37.805 220.23 37.931 ;
     RECT  13.215 37.931 220.23 38.309 ;
     RECT  13.215 38.309 218.898 38.507 ;
     RECT  220.068 38.309 220.23 38.507 ;
     RECT  218.808 38.507 218.898 38.669 ;
     RECT  220.068 38.507 220.194 38.741 ;
     RECT  0.108 37.853 0.162 39.019 ;
     RECT  2.304 37.931 12.366 39.211 ;
     RECT  0.108 39.019 0.558 39.245 ;
     RECT  0.144 39.245 0.558 39.317 ;
     RECT  2.16 39.211 12.366 39.515 ;
     RECT  218.844 38.669 218.898 39.595 ;
     RECT  13.215 38.507 217.854 39.631 ;
     RECT  2.304 39.515 12.366 39.793 ;
     RECT  13.215 39.631 218.034 39.793 ;
     RECT  220.068 38.741 220.122 39.883 ;
     RECT  0.144 39.317 0.27 39.979 ;
     RECT  220.032 39.883 220.122 39.979 ;
     RECT  218.808 39.595 218.898 40.075 ;
     RECT  220.032 39.979 220.158 40.075 ;
     RECT  2.304 39.793 218.034 40.171 ;
     RECT  218.808 40.075 220.158 40.171 ;
     RECT  2.304 40.171 220.158 40.325 ;
     RECT  2.304 40.325 208.494 40.363 ;
     RECT  0.108 39.979 0.27 40.433 ;
     RECT  0.144 40.433 0.27 40.459 ;
     RECT  209.484 40.325 220.158 40.459 ;
     RECT  0.144 40.459 0.306 40.555 ;
     RECT  1.152 40.123 1.17 40.555 ;
     RECT  1.152 40.555 1.386 40.685 ;
     RECT  0.144 40.555 0.378 40.973 ;
     RECT  2.268 40.363 208.494 41.021 ;
     RECT  2.304 41.021 208.494 41.135 ;
     RECT  206.028 41.135 208.494 41.171 ;
     RECT  2.304 41.135 205.218 41.369 ;
     RECT  206.28 41.171 208.494 41.449 ;
     RECT  209.484 40.459 220.194 41.449 ;
     RECT  0.144 40.973 0.342 41.453 ;
     RECT  1.152 40.685 1.35 41.515 ;
     RECT  0.144 41.453 0.162 41.597 ;
     RECT  206.28 41.449 220.194 41.639 ;
     RECT  2.304 41.369 12.366 41.648 ;
     RECT  210.348 41.639 220.194 41.819 ;
     RECT  13.215 41.369 205.218 41.881 ;
     RECT  210.384 41.819 220.194 41.909 ;
     RECT  1.152 41.515 1.422 41.945 ;
     RECT  212.292 41.909 218.862 41.945 ;
     RECT  13.215 41.881 205.398 41.989 ;
     RECT  206.28 41.639 209.61 41.989 ;
     RECT  220.068 41.909 220.194 41.995 ;
     RECT  210.708 41.909 211.482 42.179 ;
     RECT  1.188 41.945 1.422 42.215 ;
     RECT  212.292 41.945 218.826 42.215 ;
     RECT  1.224 42.215 1.422 42.287 ;
     RECT  220.068 41.995 220.23 42.359 ;
     RECT  13.215 41.989 209.61 42.449 ;
     RECT  211.464 42.179 211.482 42.449 ;
     RECT  212.4 42.215 218.826 42.449 ;
     RECT  209.556 42.449 209.61 42.521 ;
     RECT  1.332 42.287 1.422 42.557 ;
     RECT  210.708 42.179 210.726 42.557 ;
     RECT  1.404 42.557 1.422 42.593 ;
     RECT  212.4 42.449 218.286 42.755 ;
     RECT  2.34 41.648 12.366 42.763 ;
     RECT  2.304 42.763 12.366 42.989 ;
     RECT  13.215 42.449 208.602 42.989 ;
     RECT  220.14 42.359 220.23 42.989 ;
     RECT  2.304 42.989 6.39 43.025 ;
     RECT  213.015 42.755 218.286 43.097 ;
     RECT  2.415 43.025 6.39 43.169 ;
     RECT  3.636 43.169 6.39 43.259 ;
     RECT  214.02 43.097 218.286 43.259 ;
     RECT  3.636 43.259 6.354 43.295 ;
     RECT  215.64 43.259 218.286 43.529 ;
     RECT  209.556 42.521 209.574 43.681 ;
     RECT  220.14 42.989 220.194 43.709 ;
     RECT  3.672 43.295 6.354 43.799 ;
     RECT  220.14 43.709 220.158 43.799 ;
     RECT  216.216 43.529 217.746 43.835 ;
     RECT  216.54 43.835 217.746 44.069 ;
     RECT  209.556 43.681 209.898 44.113 ;
     RECT  13.215 42.989 208.386 44.185 ;
     RECT  13.215 44.185 208.818 44.221 ;
     RECT  209.556 44.113 210.33 44.221 ;
     RECT  211.392 44.221 211.41 44.311 ;
     RECT  13.215 44.221 210.33 44.383 ;
     RECT  211.392 44.311 211.554 44.383 ;
     RECT  216.936 44.069 217.746 44.653 ;
     RECT  216.072 44.761 216.09 44.851 ;
     RECT  216.936 44.653 218.322 44.923 ;
     RECT  7.2 42.989 12.366 44.957 ;
     RECT  13.215 44.383 211.554 44.995 ;
     RECT  214.668 44.851 215.19 44.995 ;
     RECT  216 44.851 216.09 44.995 ;
     RECT  216.828 44.923 218.322 44.995 ;
     RECT  214.668 44.995 218.322 45.121 ;
     RECT  219.456 44.851 219.474 45.193 ;
     RECT  13.215 44.995 212.022 45.229 ;
     RECT  213.015 43.097 213.297 45.301 ;
     RECT  13.215 45.229 212.058 45.391 ;
     RECT  213.015 45.301 213.57 45.391 ;
     RECT  8.964 44.957 12.366 45.427 ;
     RECT  13.215 45.391 213.57 45.427 ;
     RECT  214.488 45.121 218.322 45.463 ;
     RECT  219.456 45.193 219.51 45.463 ;
     RECT  8.964 45.427 213.57 45.571 ;
     RECT  214.488 45.463 219.51 45.581 ;
     RECT  214.488 45.581 218.034 45.661 ;
     RECT  218.88 45.581 219.51 45.661 ;
     RECT  8.964 45.571 213.642 45.797 ;
     RECT  214.416 45.661 218.034 45.805 ;
     RECT  3.672 43.799 5.202 45.931 ;
     RECT  5.94 43.799 6.354 45.931 ;
     RECT  218.88 45.661 219.546 45.965 ;
     RECT  212.832 45.797 213.642 46.039 ;
     RECT  214.38 45.805 218.034 46.039 ;
     RECT  212.832 46.039 218.034 46.309 ;
     RECT  2.415 43.169 2.697 46.345 ;
     RECT  212.832 46.309 218.322 46.349 ;
     RECT  1.764 46.345 2.697 46.381 ;
     RECT  3.672 45.931 6.354 46.381 ;
     RECT  8.964 45.797 212.094 46.603 ;
     RECT  212.832 46.349 218.286 46.603 ;
     RECT  1.764 46.381 6.354 46.615 ;
     RECT  219.456 45.965 219.546 46.637 ;
     RECT  8.964 46.603 218.286 46.733 ;
     RECT  7.2 44.957 8.154 46.741 ;
     RECT  8.964 46.733 217.998 46.769 ;
     RECT  1.728 46.615 6.354 46.829 ;
     RECT  7.2 46.741 8.226 46.921 ;
     RECT  8.964 46.769 11.142 46.921 ;
     RECT  1.764 46.829 6.354 47.021 ;
     RECT  2.304 47.021 6.354 47.047 ;
     RECT  7.2 46.921 11.142 47.047 ;
     RECT  219.456 46.637 219.474 47.083 ;
     RECT  218.844 47.083 219.474 47.219 ;
     RECT  2.304 47.047 11.142 47.459 ;
     RECT  2.304 47.459 8.226 47.615 ;
     RECT  11.88 46.769 217.998 47.731 ;
     RECT  11.88 47.731 218.322 47.789 ;
     RECT  219.348 47.219 219.474 47.849 ;
     RECT  219.384 47.849 219.474 47.851 ;
     RECT  0.108 46.579 0.126 47.885 ;
     RECT  11.88 47.789 217.89 47.885 ;
     RECT  11.88 47.885 217.854 48.191 ;
     RECT  219.384 47.851 220.122 48.331 ;
     RECT  2.304 47.615 6.354 48.361 ;
     RECT  7.164 47.615 8.226 48.361 ;
     RECT  2.304 48.361 8.226 48.389 ;
     RECT  2.304 48.389 2.697 48.425 ;
     RECT  219.384 48.331 220.194 48.586 ;
     RECT  3.672 48.389 8.226 48.703 ;
     RECT  8.964 47.459 11.142 48.703 ;
     RECT  20.772 48.191 217.854 48.929 ;
     RECT  3.672 48.703 11.142 49.343 ;
     RECT  11.88 48.191 20.034 49.441 ;
     RECT  20.772 48.929 217.818 49.441 ;
     RECT  219.384 48.586 220.23 49.469 ;
     RECT  11.88 49.441 217.818 49.915 ;
     RECT  11.88 49.915 218.286 50.387 ;
     RECT  219.42 49.469 220.23 50.443 ;
     RECT  20.772 50.387 218.286 50.701 ;
     RECT  219.348 50.443 220.23 50.701 ;
     RECT  20.772 50.701 220.23 50.861 ;
     RECT  20.772 50.861 217.926 51.089 ;
     RECT  218.844 50.861 220.23 51.395 ;
     RECT  218.844 51.395 219.438 51.629 ;
     RECT  20.772 51.089 208.494 51.871 ;
     RECT  209.268 51.089 217.926 51.871 ;
     RECT  218.844 51.629 219.402 52.027 ;
     RECT  20.772 51.871 217.926 52.051 ;
     RECT  20.772 52.051 218.034 52.439 ;
     RECT  209.772 52.439 218.034 52.555 ;
     RECT  218.808 52.027 219.402 52.555 ;
     RECT  209.772 52.555 219.438 52.817 ;
     RECT  11.88 50.387 20.034 52.861 ;
     RECT  20.772 52.439 209.034 52.861 ;
     RECT  214.092 52.817 219.438 53.176 ;
     RECT  220.176 51.395 220.23 53.176 ;
     RECT  214.092 53.176 220.23 53.213 ;
     RECT  11.88 52.861 209.034 53.221 ;
     RECT  209.772 52.817 213.297 53.221 ;
     RECT  3.672 49.343 9.99 53.491 ;
     RECT  11.88 53.221 213.297 53.563 ;
     RECT  214.092 53.213 219.438 53.563 ;
     RECT  2.415 48.425 2.697 53.671 ;
     RECT  3.492 53.491 9.99 53.671 ;
     RECT  220.212 53.213 220.23 53.995 ;
     RECT  2.415 53.671 9.99 54.067 ;
     RECT  11.88 53.563 219.438 54.095 ;
     RECT  20.772 54.095 219.438 54.125 ;
     RECT  218.772 54.125 219.438 54.187 ;
     RECT  220.176 53.995 220.23 54.187 ;
     RECT  2.304 54.067 9.99 54.337 ;
     RECT  1.8 54.337 9.99 54.373 ;
     RECT  11.124 49.343 11.142 54.473 ;
     RECT  0.828 54.643 0.846 54.667 ;
     RECT  1.728 54.373 9.99 54.671 ;
     RECT  1.728 54.671 9.594 54.797 ;
     RECT  1.764 54.797 9.594 54.893 ;
     RECT  1.8 54.893 9.594 55.085 ;
     RECT  20.772 54.125 217.962 55.243 ;
     RECT  218.772 54.187 220.23 55.243 ;
     RECT  11.88 54.095 19.71 55.381 ;
     RECT  20.772 55.243 220.23 55.381 ;
     RECT  11.88 55.381 220.23 55.481 ;
     RECT  20.412 55.481 220.23 55.517 ;
     RECT  11.88 55.481 19.674 55.589 ;
     RECT  20.772 55.517 220.23 55.679 ;
     RECT  20.772 55.679 212.166 55.715 ;
     RECT  212.904 55.679 220.23 55.757 ;
     RECT  2.376 55.085 9.594 55.819 ;
     RECT  204.624 55.715 212.166 55.949 ;
     RECT  204.696 55.949 212.166 55.985 ;
     RECT  209.412 55.985 212.166 56.021 ;
     RECT  207.504 55.985 208.674 56.255 ;
     RECT  207.576 56.255 208.674 56.291 ;
     RECT  0.108 54.667 0.846 56.299 ;
     RECT  209.484 56.021 212.166 56.461 ;
     RECT  212.904 55.757 218.286 56.461 ;
     RECT  209.484 56.461 218.286 56.491 ;
     RECT  219.42 55.757 220.23 56.491 ;
     RECT  0.108 56.299 1.17 56.525 ;
     RECT  0.144 56.525 1.17 56.621 ;
     RECT  209.484 56.491 220.23 56.717 ;
     RECT  209.484 56.717 218.862 56.759 ;
     RECT  204.876 55.985 206.514 56.911 ;
     RECT  20.772 55.715 203.886 57.001 ;
     RECT  204.624 56.911 206.514 57.005 ;
     RECT  207.615 56.291 208.674 57.019 ;
     RECT  1.152 56.621 1.17 57.029 ;
     RECT  2.304 55.819 9.594 57.029 ;
     RECT  207.615 57.019 209.07 57.065 ;
     RECT  220.032 56.717 220.23 57.073 ;
     RECT  220.032 57.073 220.302 57.197 ;
     RECT  207.615 57.065 208.782 57.299 ;
     RECT  0.144 56.621 0.162 57.389 ;
     RECT  2.304 57.029 9.09 57.403 ;
     RECT  20.52 57.001 203.886 57.407 ;
     RECT  207.615 57.299 208.458 57.479 ;
     RECT  209.88 56.759 218.862 57.479 ;
     RECT  205.848 57.005 206.514 57.541 ;
     RECT  2.268 57.403 9.09 57.569 ;
     RECT  207.615 57.479 207.99 57.569 ;
     RECT  210.24 57.479 218.862 57.569 ;
     RECT  204.624 57.005 205.11 57.605 ;
     RECT  210.276 57.569 218.862 57.713 ;
     RECT  210.96 57.713 218.862 57.875 ;
     RECT  210.96 57.875 211.482 57.947 ;
     RECT  11.88 55.589 19.566 58.019 ;
     RECT  211.464 57.947 211.482 58.019 ;
     RECT  212.436 57.875 218.862 58.019 ;
     RECT  205.848 57.541 206.658 58.109 ;
     RECT  2.268 57.569 8.982 58.117 ;
     RECT  1.728 58.117 8.982 58.349 ;
     RECT  212.472 58.019 218.862 58.379 ;
     RECT  20.772 57.407 203.886 58.387 ;
     RECT  0.108 57.931 0.126 58.411 ;
     RECT  0.108 58.411 0.342 58.541 ;
     RECT  11.88 58.019 16.938 58.559 ;
     RECT  213.015 58.379 218.862 58.649 ;
     RECT  213.015 58.649 213.354 58.721 ;
     RECT  220.068 57.197 220.302 58.721 ;
     RECT  214.272 58.649 218.79 58.919 ;
     RECT  17.928 58.019 19.566 58.991 ;
     RECT  12.816 58.559 16.938 59.027 ;
     RECT  215.064 58.919 218.79 59.027 ;
     RECT  20.52 58.387 203.886 59.099 ;
     RECT  0.108 58.541 0.126 59.117 ;
     RECT  20.52 59.099 200.358 59.161 ;
     RECT  12.816 59.027 13.662 59.189 ;
     RECT  214.308 58.919 214.326 59.189 ;
     RECT  215.1 59.027 218.79 59.189 ;
     RECT  20.304 59.161 200.358 59.261 ;
     RECT  215.1 59.189 218.286 59.261 ;
     RECT  2.304 58.349 8.982 59.269 ;
     RECT  2.268 59.269 8.982 59.405 ;
     RECT  20.376 59.261 200.358 59.405 ;
     RECT  13.14 59.189 13.662 59.459 ;
     RECT  215.136 59.261 218.286 59.459 ;
     RECT  0.18 59.275 0.378 59.467 ;
     RECT  2.304 59.405 8.982 59.495 ;
     RECT  0.18 59.467 0.558 59.567 ;
     RECT  220.104 58.721 220.302 59.603 ;
     RECT  2.376 59.495 8.982 59.611 ;
     RECT  215.172 59.459 218.286 59.639 ;
     RECT  220.176 59.603 220.302 59.639 ;
     RECT  0.18 59.567 0.414 59.693 ;
     RECT  2.376 59.611 9.27 59.729 ;
     RECT  216.216 59.639 218.286 59.801 ;
     RECT  13.14 59.459 13.497 59.909 ;
     RECT  2.376 59.729 9.234 59.999 ;
     RECT  215.172 59.639 215.19 59.999 ;
     RECT  216.36 59.801 218.286 59.999 ;
     RECT  0.18 59.693 0.306 60.043 ;
     RECT  14.508 59.027 16.938 60.071 ;
     RECT  20.376 59.405 200.286 60.269 ;
     RECT  216.396 59.999 218.142 60.269 ;
     RECT  220.284 59.639 220.302 60.269 ;
     RECT  216.936 60.269 218.142 60.305 ;
     RECT  2.415 59.999 9.234 60.341 ;
     RECT  216.936 60.305 217.746 60.341 ;
     RECT  217.44 60.341 217.746 60.377 ;
     RECT  217.44 60.377 217.458 60.449 ;
     RECT  0.144 60.043 0.306 60.523 ;
     RECT  10.836 60.421 10.854 60.539 ;
     RECT  15.66 60.071 16.938 60.539 ;
     RECT  0.144 60.523 0.342 60.619 ;
     RECT  0.108 60.619 0.342 60.653 ;
     RECT  0.108 60.653 0.162 60.656 ;
     RECT  15.66 60.539 16.686 60.719 ;
     RECT  20.772 60.269 200.286 60.749 ;
     RECT  2.415 60.341 8.982 60.925 ;
     RECT  1.728 60.925 8.982 61.079 ;
     RECT  0.144 60.656 0.162 61.133 ;
     RECT  1.728 61.079 8.478 61.147 ;
     RECT  21.348 60.749 200.286 61.195 ;
     RECT  9.252 61.231 9.27 61.349 ;
     RECT  1.26 61.147 8.478 61.421 ;
     RECT  11.88 58.559 11.898 61.591 ;
     RECT  20.412 61.087 20.43 61.591 ;
     RECT  2.304 61.421 8.478 61.619 ;
     RECT  15.66 60.719 16.398 61.619 ;
     RECT  2.376 61.619 8.478 61.691 ;
     RECT  20.376 61.591 20.43 61.735 ;
     RECT  11.808 61.591 11.898 61.771 ;
     RECT  20.376 61.735 20.538 61.889 ;
     RECT  11.736 61.771 11.898 61.897 ;
     RECT  11.736 61.897 11.97 61.925 ;
     RECT  0.108 61.867 0.126 61.969 ;
     RECT  1.152 61.483 1.17 61.969 ;
     RECT  2.376 61.691 7.002 61.997 ;
     RECT  11.952 61.925 11.97 61.997 ;
     RECT  21.348 61.195 200.322 62.155 ;
     RECT  0.108 61.969 1.17 62.195 ;
     RECT  7.74 61.691 8.478 62.251 ;
     RECT  20.7 62.155 200.322 62.251 ;
     RECT  0.108 62.195 0.45 62.285 ;
     RECT  18.615 58.991 19.566 62.303 ;
     RECT  14.508 60.071 14.526 62.339 ;
     RECT  20.7 62.251 200.394 62.339 ;
     RECT  20.7 62.339 200.358 62.429 ;
     RECT  21.348 62.429 200.358 62.501 ;
     RECT  2.415 61.997 7.002 62.581 ;
     RECT  7.74 62.251 8.514 62.581 ;
     RECT  2.415 62.581 8.514 62.699 ;
     RECT  16.38 61.619 16.398 62.699 ;
     RECT  19.8 62.311 19.962 62.699 ;
     RECT  9.648 62.581 9.666 62.735 ;
     RECT  2.415 62.699 8.478 63.049 ;
     RECT  19.872 62.699 19.962 63.121 ;
     RECT  10.8 62.851 10.818 63.149 ;
     RECT  199.188 62.501 200.358 63.149 ;
     RECT  201.24 59.099 203.886 63.149 ;
     RECT  0.108 62.285 0.162 63.211 ;
     RECT  2.376 63.049 8.478 63.211 ;
     RECT  19.872 63.121 20.43 63.211 ;
     RECT  21.348 62.501 198.09 63.211 ;
     RECT  19.872 63.211 198.09 63.481 ;
     RECT  0.108 63.211 0.198 63.517 ;
     RECT  1.188 62.347 1.206 63.517 ;
     RECT  0.108 63.517 1.242 63.617 ;
     RECT  19.836 63.481 198.09 63.661 ;
     RECT  199.188 63.149 200.322 63.661 ;
     RECT  0.108 63.617 1.206 63.725 ;
     RECT  19.836 63.661 200.322 63.725 ;
     RECT  2.304 63.211 8.478 63.787 ;
     RECT  19.836 63.725 20.61 63.815 ;
     RECT  2.232 63.787 8.478 63.923 ;
     RECT  11.916 63.661 11.934 63.931 ;
     RECT  10.836 63.931 10.854 64.021 ;
     RECT  10.116 64.021 10.854 64.049 ;
     RECT  11.916 63.931 12.258 64.049 ;
     RECT  11.916 64.049 11.934 64.085 ;
     RECT  10.116 64.049 10.134 64.121 ;
     RECT  19.944 63.815 20.61 64.157 ;
     RECT  19.944 64.157 20.25 64.193 ;
     RECT  21.348 63.725 200.322 64.205 ;
     RECT  2.304 63.923 8.478 64.229 ;
     RECT  2.304 64.229 8.406 64.319 ;
     RECT  2.304 64.319 8.262 64.355 ;
     RECT  198.936 64.205 200.322 64.459 ;
     RECT  201.24 63.149 201.33 64.459 ;
     RECT  0.108 63.725 0.198 64.471 ;
     RECT  1.152 63.725 1.206 64.471 ;
     RECT  21.348 64.205 198.09 64.561 ;
     RECT  198.936 64.459 201.33 64.589 ;
     RECT  198.936 64.589 200.43 64.781 ;
     RECT  0.108 64.471 1.206 64.877 ;
     RECT  18.615 62.303 18.897 65.011 ;
     RECT  198.936 64.781 200.358 65.021 ;
     RECT  21.096 64.561 198.09 65.035 ;
     RECT  198.936 65.021 200.322 65.035 ;
     RECT  2.304 64.355 8.19 65.101 ;
     RECT  9.252 64.363 9.27 65.101 ;
     RECT  20.232 64.193 20.25 65.209 ;
     RECT  21.096 65.035 200.322 65.209 ;
     RECT  18.615 65.011 18.99 65.273 ;
     RECT  2.304 65.101 9.27 65.275 ;
     RECT  1.152 64.877 1.206 65.435 ;
     RECT  2.268 65.275 9.27 65.777 ;
     RECT  1.296 65.515 1.314 65.899 ;
     RECT  0.108 64.877 0.342 66.091 ;
     RECT  2.304 65.777 9.27 66.091 ;
     RECT  18.615 65.273 18.897 66.139 ;
     RECT  18.615 66.139 19.278 66.479 ;
     RECT  0.108 66.091 0.558 66.515 ;
     RECT  0.324 66.515 0.558 66.571 ;
     RECT  1.296 65.899 1.422 66.571 ;
     RECT  2.304 66.091 9.486 66.659 ;
     RECT  2.304 66.659 8.514 67.055 ;
     RECT  9.252 66.659 9.486 67.055 ;
     RECT  20.232 65.209 200.322 67.063 ;
     RECT  2.34 67.055 8.514 67.133 ;
     RECT  20.196 67.063 200.322 67.171 ;
     RECT  19.944 67.171 200.322 67.397 ;
     RECT  0.324 66.571 1.422 67.667 ;
     RECT  18.615 66.479 18.897 67.675 ;
     RECT  2.34 67.133 8.19 67.703 ;
     RECT  18.615 67.675 18.954 67.829 ;
     RECT  11.088 66.901 11.106 67.837 ;
     RECT  0.324 67.667 0.342 67.865 ;
     RECT  1.188 67.667 1.422 67.937 ;
     RECT  1.188 67.937 1.206 68.135 ;
     RECT  20.232 67.397 200.322 68.395 ;
     RECT  19.908 68.395 200.322 68.525 ;
     RECT  2.415 67.703 8.19 68.639 ;
     RECT  22.212 68.525 200.322 68.639 ;
     RECT  3.528 68.639 8.19 68.861 ;
     RECT  19.908 68.525 21.366 68.909 ;
     RECT  20.232 68.909 21.366 70.951 ;
     RECT  22.5 68.639 200.322 70.951 ;
     RECT  20.232 70.951 200.322 71.491 ;
     RECT  3.816 68.861 8.19 71.951 ;
     RECT  19.656 71.491 200.322 77.009 ;
     RECT  20.232 77.009 200.322 78.907 ;
     RECT  20.052 78.907 200.322 78.944 ;
     RECT  11.088 67.837 11.538 80.941 ;
     RECT  20.196 78.944 200.322 84.847 ;
     RECT  19.944 84.847 200.322 84.893 ;
     RECT  20.196 84.893 200.322 88.501 ;
     RECT  201.24 64.589 201.33 89.159 ;
     RECT  3.816 71.951 4.446 89.771 ;
     RECT  5.364 71.951 8.19 95.477 ;
     RECT  11.088 80.941 11.682 96.053 ;
     RECT  7.128 95.477 8.19 96.629 ;
     RECT  19.764 88.501 200.322 97.529 ;
     RECT  5.364 95.477 6.21 98.339 ;
     RECT  20.052 97.529 200.322 98.55 ;
     RECT  20.052 98.55 22.914 98.609 ;
     RECT  7.668 96.629 8.19 98.915 ;
     RECT  3.816 89.771 4.338 98.987 ;
     RECT  66.384 98.55 66.69 99.104 ;
     RECT  66.384 99.104 66.618 99.463 ;
     RECT  5.364 98.339 5.382 99.491 ;
     RECT  68.328 98.55 68.67 99.499 ;
     RECT  68.328 99.499 68.994 99.571 ;
     RECT  69.84 98.55 69.858 99.571 ;
     RECT  11.088 96.053 11.106 99.599 ;
     RECT  88.2 98.55 88.218 99.661 ;
     RECT  20.232 98.609 22.914 99.689 ;
     RECT  6.192 98.339 6.21 99.761 ;
     RECT  67.572 99.463 67.59 100.003 ;
     RECT  68.328 99.571 69.858 100.003 ;
     RECT  3.996 98.987 4.338 100.031 ;
     RECT  87.948 99.661 88.218 100.039 ;
     RECT  7.668 98.915 8.097 100.067 ;
     RECT  21.348 99.689 22.914 100.103 ;
     RECT  197.64 98.55 200.322 100.103 ;
     RECT  9.324 67.055 9.486 100.139 ;
     RECT  20.232 99.689 20.358 100.229 ;
     RECT  65.16 99.499 65.178 100.426 ;
     RECT  71.748 100.039 71.766 100.459 ;
     RECT  87.804 100.039 88.218 100.499 ;
     RECT  32.148 99.733 32.166 100.507 ;
     RECT  65.16 100.426 65.214 100.507 ;
     RECT  67.572 100.003 69.858 100.507 ;
     RECT  70.668 98.55 70.686 100.507 ;
     RECT  75.348 100.471 75.366 100.507 ;
     RECT  76.356 99.535 76.374 100.507 ;
     RECT  67.572 100.507 70.686 100.543 ;
     RECT  73.98 100.543 73.998 100.555 ;
     RECT  50.4 99.697 50.418 100.579 ;
     RECT  143.136 100.075 143.154 100.603 ;
     RECT  80.82 100.579 80.838 100.615 ;
     RECT  67.572 100.543 70.722 100.651 ;
     RECT  73.908 100.555 73.998 100.651 ;
     RECT  75.348 100.507 76.374 100.651 ;
     RECT  50.4 100.579 50.67 100.693 ;
     RECT  62.568 98.55 62.586 100.693 ;
     RECT  67.572 100.651 70.794 100.693 ;
     RECT  105.372 100.459 106.002 100.693 ;
     RECT  180.144 100.555 180.162 100.693 ;
     RECT  185.544 100.603 185.562 100.693 ;
     RECT  197.64 100.103 199.71 100.693 ;
     RECT  32.148 100.507 32.418 100.741 ;
     RECT  145.368 100.603 145.386 100.741 ;
     RECT  83.607 100.693 83.697 100.747 ;
     RECT  64.08 98.55 64.098 100.769 ;
     RECT  67.407 100.693 70.794 100.769 ;
     RECT  71.748 100.459 72.018 100.769 ;
     RECT  75.348 100.651 76.986 100.769 ;
     RECT  80.748 100.615 80.838 100.769 ;
     RECT  84.78 100.579 84.798 100.769 ;
     RECT  87.876 100.499 88.218 100.769 ;
     RECT  95.976 100.507 95.994 100.769 ;
     RECT  97.092 99.979 97.11 100.769 ;
     RECT  103.752 100.507 103.77 100.769 ;
     RECT  105.207 100.693 106.002 100.769 ;
     RECT  145.044 100.741 145.386 100.769 ;
     RECT  180.144 100.693 180.897 100.769 ;
     RECT  185.544 100.693 186.297 100.769 ;
     RECT  62.007 100.693 62.586 100.777 ;
     RECT  142.524 100.603 143.154 100.781 ;
     RECT  178.632 100.555 178.65 100.795 ;
     RECT  184.104 100.603 184.122 100.795 ;
     RECT  32.148 100.741 33.138 100.805 ;
     RECT  37.944 100.201 37.962 100.805 ;
     RECT  41.832 100.111 41.85 100.805 ;
     RECT  50.4 100.693 51.297 100.805 ;
     RECT  71.748 100.769 71.766 100.805 ;
     RECT  87.948 100.769 87.966 100.805 ;
     RECT  145.044 100.769 145.062 100.829 ;
     RECT  142.815 100.781 143.154 100.84 ;
     RECT  68.328 100.769 70.794 100.841 ;
     RECT  178.596 100.795 178.65 100.841 ;
     RECT  183.996 100.795 184.122 100.841 ;
     RECT  72.807 100.693 72.897 100.843 ;
     RECT  73.908 100.651 74.25 100.843 ;
     RECT  108.72 100.741 108.738 100.849 ;
     RECT  90.54 100.543 90.558 100.877 ;
     RECT  142.815 100.84 143.514 100.877 ;
     RECT  146.628 100.84 146.646 100.877 ;
     RECT  150.444 100.747 150.462 100.877 ;
     RECT  82.332 100.849 82.35 100.885 ;
     RECT  108.648 100.849 108.738 100.885 ;
     RECT  197.007 100.693 199.71 100.891 ;
     RECT  75.348 100.769 76.374 100.921 ;
     RECT  83.607 100.747 83.79 100.921 ;
     RECT  24.207 100.693 24.297 100.963 ;
     RECT  29.607 100.693 29.697 100.963 ;
     RECT  35.007 100.693 35.097 100.963 ;
     RECT  40.407 100.693 40.497 100.963 ;
     RECT  45.807 100.693 45.897 100.963 ;
     RECT  56.607 100.693 56.697 100.963 ;
     RECT  62.007 100.777 62.838 100.963 ;
     RECT  66.276 99.463 66.618 100.963 ;
     RECT  67.407 100.769 67.554 100.963 ;
     RECT  72.807 100.843 74.25 100.963 ;
     RECT  78.207 100.693 78.297 100.963 ;
     RECT  83.607 100.921 83.862 100.963 ;
     RECT  89.007 100.693 89.097 100.963 ;
     RECT  94.407 100.693 94.497 100.963 ;
     RECT  99.807 100.693 99.897 100.963 ;
     RECT  105.207 100.769 105.297 100.963 ;
     RECT  110.607 100.693 110.697 100.963 ;
     RECT  116.007 100.693 116.097 100.963 ;
     RECT  121.407 100.693 121.497 100.963 ;
     RECT  126.807 100.693 126.897 100.963 ;
     RECT  132.207 100.693 132.297 100.963 ;
     RECT  137.607 100.693 137.697 100.963 ;
     RECT  148.407 100.693 148.497 100.963 ;
     RECT  153.807 100.693 153.897 100.963 ;
     RECT  159.207 100.693 159.297 100.963 ;
     RECT  164.607 100.693 164.697 100.963 ;
     RECT  170.007 100.693 170.097 100.963 ;
     RECT  175.407 100.693 175.497 100.963 ;
     RECT  191.607 100.693 191.697 100.963 ;
     RECT  197.007 100.891 200.43 100.963 ;
     RECT  108.324 100.885 108.81 100.973 ;
     RECT  72.615 100.963 74.25 101.011 ;
     RECT  75.276 100.921 76.374 101.011 ;
     RECT  32.796 100.805 33.138 101.039 ;
     RECT  68.328 100.841 70.11 101.039 ;
     RECT  71.568 100.921 71.622 101.039 ;
     RECT  72.615 101.011 76.374 101.039 ;
     RECT  83.415 100.963 83.862 101.039 ;
     RECT  86.76 100.921 86.85 101.039 ;
     RECT  108.36 100.973 108.666 101.039 ;
     RECT  178.632 100.841 178.65 101.039 ;
     RECT  184.104 100.841 184.122 101.039 ;
     RECT  40.215 100.963 40.497 101.047 ;
     RECT  31.788 101.035 32.058 101.075 ;
     RECT  32.796 101.039 32.814 101.075 ;
     RECT  69.516 101.039 69.858 101.075 ;
     RECT  7.815 100.067 8.097 101.083 ;
     RECT  102.636 100.603 102.654 101.083 ;
     RECT  106.092 101.011 106.614 101.083 ;
     RECT  82.332 100.885 82.602 101.111 ;
     RECT  102.636 101.083 102.798 101.179 ;
     RECT  106.092 101.083 106.686 101.179 ;
     RECT  102.6 101.179 102.798 101.182 ;
     RECT  21.924 100.103 22.914 101.183 ;
     RECT  61.815 100.963 62.838 101.183 ;
     RECT  98.676 101.083 98.694 101.183 ;
     RECT  62.82 101.183 62.838 101.191 ;
     RECT  65.16 100.507 65.286 101.191 ;
     RECT  66.276 100.963 67.554 101.191 ;
     RECT  7.815 101.083 8.19 101.213 ;
     RECT  39.672 101.047 40.497 101.213 ;
     RECT  62.82 101.191 62.874 101.213 ;
     RECT  194.364 101.083 194.382 101.213 ;
     RECT  106.092 101.179 107.226 101.219 ;
     RECT  108.36 101.039 108.486 101.219 ;
     RECT  68.4 101.039 68.67 101.309 ;
     RECT  81.144 101.011 81.522 101.309 ;
     RECT  82.332 101.111 82.35 101.309 ;
     RECT  98.604 101.191 98.622 101.309 ;
     RECT  102.6 101.182 102.834 101.309 ;
     RECT  196.815 100.963 200.43 101.309 ;
     RECT  78.015 100.963 78.297 101.353 ;
     RECT  65.088 101.191 65.43 101.357 ;
     RECT  72.615 101.039 74.862 101.357 ;
     RECT  81.396 101.309 81.522 101.357 ;
     RECT  102.6 101.309 102.618 101.357 ;
     RECT  106.092 101.219 106.11 101.357 ;
     RECT  107.208 101.219 107.226 101.357 ;
     RECT  62.856 101.213 62.874 101.381 ;
     RECT  71.604 101.039 71.622 101.381 ;
     RECT  66.24 101.191 67.554 101.405 ;
     RECT  101.592 101.191 101.61 101.405 ;
     RECT  32.04 101.075 32.058 101.453 ;
     RECT  65.16 101.357 65.43 101.453 ;
     RECT  66.276 101.405 67.554 101.453 ;
     RECT  74.052 101.357 74.862 101.453 ;
     RECT  78.015 101.353 78.678 101.453 ;
     RECT  108.36 101.219 108.378 101.453 ;
     RECT  196.815 101.309 200.106 101.459 ;
     RECT  75.672 101.039 76.014 101.489 ;
     RECT  65.16 101.453 65.178 101.579 ;
     RECT  67.215 101.453 67.554 101.579 ;
     RECT  81.504 101.357 81.522 101.579 ;
     RECT  70.704 101.563 70.722 101.693 ;
     RECT  29.415 100.963 29.697 101.731 ;
     RECT  51.015 100.805 51.297 101.731 ;
     RECT  52.884 99.571 52.902 101.731 ;
     RECT  3.996 100.031 4.194 101.759 ;
     RECT  86.76 101.039 86.778 101.759 ;
     RECT  196.815 101.459 199.71 101.759 ;
     RECT  50.724 101.731 51.297 101.849 ;
     RECT  52.884 101.731 53.118 101.849 ;
     RECT  68.652 101.309 68.67 101.849 ;
     RECT  74.052 101.453 74.07 101.849 ;
     RECT  75.996 101.489 76.014 101.849 ;
     RECT  52.884 101.849 52.902 101.885 ;
     RECT  75.168 101.821 75.186 101.885 ;
     RECT  54.72 101.731 54.738 102.029 ;
     RECT  66.276 101.453 66.294 102.029 ;
     RECT  21.924 101.183 22.842 102.119 ;
     RECT  69.516 101.075 69.534 102.119 ;
     RECT  196.815 101.759 199.638 102.119 ;
     RECT  142.815 100.877 143.154 102.155 ;
     RECT  20.232 100.229 20.25 102.299 ;
     RECT  196.815 102.119 199.458 102.389 ;
     RECT  65.412 102.379 65.43 102.425 ;
     RECT  29.415 101.731 30.222 102.659 ;
     RECT  68.724 102.271 68.742 102.659 ;
     RECT  198.18 102.389 199.458 102.695 ;
     RECT  21.924 102.119 22.662 102.803 ;
     RECT  22.572 102.803 22.662 102.839 ;
     RECT  145.944 101.731 145.962 102.839 ;
     RECT  70.596 102.811 70.614 102.901 ;
     RECT  64.944 102.811 64.962 102.929 ;
     RECT  66.132 102.775 66.15 102.929 ;
     RECT  70.596 102.901 70.686 102.929 ;
     RECT  198.18 102.695 198.738 102.929 ;
     RECT  70.668 102.929 70.686 103.001 ;
     RECT  69.84 102.811 69.858 103.181 ;
     RECT  3.996 101.759 4.014 103.199 ;
     RECT  198.18 102.929 198.63 103.199 ;
     RECT  83.415 101.039 83.697 103.441 ;
     RECT  85.572 100.921 85.59 103.477 ;
     RECT  83.415 103.441 83.754 103.517 ;
     RECT  84.852 103.477 85.59 103.517 ;
     RECT  84.78 103.981 84.798 104.045 ;
     RECT  85.572 103.517 85.59 104.189 ;
     RECT  110.415 100.963 110.697 104.245 ;
     RECT  78.015 101.453 78.297 104.251 ;
     RECT  83.415 103.517 83.697 104.251 ;
     RECT  88.815 100.963 89.097 104.251 ;
     RECT  99.615 100.963 99.897 104.251 ;
     RECT  121.215 100.963 121.497 104.251 ;
     RECT  132.015 100.963 132.297 104.251 ;
     RECT  142.815 102.155 143.097 104.251 ;
     RECT  153.615 100.963 153.897 104.251 ;
     RECT  164.415 100.963 164.697 104.251 ;
     RECT  175.215 100.963 175.497 104.251 ;
     RECT  186.015 100.769 186.297 104.251 ;
     RECT  53.244 104.161 53.262 104.279 ;
     RECT  110.304 104.245 110.697 104.285 ;
     RECT  194.364 104.107 194.382 104.285 ;
     RECT  77.904 104.251 78.297 104.288 ;
     RECT  82.8 104.251 83.934 104.288 ;
     RECT  88.704 104.251 89.097 104.288 ;
     RECT  99.504 104.251 99.897 104.288 ;
     RECT  121.104 104.251 121.497 104.288 ;
     RECT  131.904 104.251 132.297 104.288 ;
     RECT  142.704 104.251 143.097 104.288 ;
     RECT  153.504 104.251 153.897 104.288 ;
     RECT  164.304 104.251 164.697 104.288 ;
     RECT  175.104 104.251 175.497 104.288 ;
     RECT  185.904 104.251 186.297 104.288 ;
     RECT  22.572 102.839 22.59 104.315 ;
     RECT  97.632 104.521 97.65 104.573 ;
     RECT  9.324 100.139 9.378 104.585 ;
     RECT  59.796 104.539 59.814 104.585 ;
     RECT  96.516 104.539 96.534 104.585 ;
     RECT  83.415 104.288 83.697 105.355 ;
     RECT  85.32 105.331 85.338 105.389 ;
     RECT  83.415 105.355 84.222 105.395 ;
     RECT  198.18 103.199 198.198 105.629 ;
     RECT  9.324 104.585 9.342 105.665 ;
     RECT  202.14 63.149 203.886 105.781 ;
     RECT  202.104 105.781 203.886 105.821 ;
     RECT  205.092 57.605 205.11 107.789 ;
     RECT  202.14 105.821 203.886 107.941 ;
     RECT  201.276 89.159 201.33 113.419 ;
     RECT  200.772 113.419 201.33 113.459 ;
     RECT  200.484 113.503 200.502 113.549 ;
     RECT  167.148 115.003 167.166 115.619 ;
     RECT  168.696 115.231 168.714 115.661 ;
     RECT  201.276 113.459 201.33 118.561 ;
     RECT  201.276 118.561 201.402 119.707 ;
     RECT  202.14 107.941 203.958 119.707 ;
     RECT  201.276 119.707 203.958 121.261 ;
     RECT  201.24 121.261 203.958 121.435 ;
     RECT  200.556 121.435 203.958 121.711 ;
     RECT  200.16 121.711 203.958 121.865 ;
     RECT  200.304 121.865 203.958 121.963 ;
     RECT  205.848 58.109 205.866 121.973 ;
     RECT  200.304 121.963 204.102 122.099 ;
     RECT  200.304 122.099 203.31 122.369 ;
     RECT  204.084 122.099 204.102 122.369 ;
     RECT  200.304 122.369 203.238 122.639 ;
     RECT  200.304 122.639 203.022 122.819 ;
     RECT  2.415 68.639 2.697 122.867 ;
     RECT  7.815 101.213 8.097 122.867 ;
     RECT  13.215 59.909 13.497 122.867 ;
     RECT  18.615 67.829 18.897 122.867 ;
     RECT  24.015 100.963 24.297 122.867 ;
     RECT  29.415 102.659 29.697 122.867 ;
     RECT  34.815 100.963 35.097 122.867 ;
     RECT  40.215 101.213 40.497 122.867 ;
     RECT  45.615 100.963 45.897 122.867 ;
     RECT  51.015 101.849 51.297 122.867 ;
     RECT  56.415 100.963 56.697 122.867 ;
     RECT  61.815 101.183 62.097 122.867 ;
     RECT  67.215 101.579 67.497 122.867 ;
     RECT  72.615 101.357 72.897 122.867 ;
     RECT  78.015 104.288 78.297 122.867 ;
     RECT  83.415 105.395 83.697 122.867 ;
     RECT  88.815 104.288 89.097 122.867 ;
     RECT  94.215 100.963 94.497 122.867 ;
     RECT  99.615 104.288 99.897 122.867 ;
     RECT  105.015 100.963 105.297 122.867 ;
     RECT  110.415 104.285 110.697 122.867 ;
     RECT  115.815 100.963 116.097 122.867 ;
     RECT  121.215 104.288 121.497 122.867 ;
     RECT  126.615 100.963 126.897 122.867 ;
     RECT  132.015 104.288 132.297 122.867 ;
     RECT  137.415 100.963 137.697 122.867 ;
     RECT  142.815 104.288 143.097 122.867 ;
     RECT  148.215 100.963 148.497 122.867 ;
     RECT  153.615 104.288 153.897 122.867 ;
     RECT  159.015 100.963 159.297 122.867 ;
     RECT  164.415 104.288 164.697 122.867 ;
     RECT  169.815 100.963 170.097 122.867 ;
     RECT  175.215 104.288 175.497 122.867 ;
     RECT  180.615 100.769 180.897 122.867 ;
     RECT  186.015 104.288 186.297 122.867 ;
     RECT  191.415 100.963 191.697 122.867 ;
     RECT  196.815 102.389 197.097 122.867 ;
     RECT  207.615 57.569 207.897 122.867 ;
     RECT  213.015 58.721 213.297 122.867 ;
     RECT  200.484 122.819 203.022 122.909 ;
     RECT  200.736 122.909 203.022 122.945 ;
     RECT  200.736 122.945 202.77 123.101 ;
     RECT  2.415 122.867 2.505 123.137 ;
     RECT  7.815 122.867 7.905 123.137 ;
     RECT  13.215 122.867 13.305 123.137 ;
     RECT  18.615 122.867 18.705 123.137 ;
     RECT  24.015 122.867 24.105 123.137 ;
     RECT  29.415 122.867 29.505 123.137 ;
     RECT  34.815 122.867 34.905 123.137 ;
     RECT  40.215 122.867 40.305 123.137 ;
     RECT  45.615 122.867 45.705 123.137 ;
     RECT  51.015 122.867 51.105 123.137 ;
     RECT  56.415 122.867 56.505 123.137 ;
     RECT  61.815 122.867 61.905 123.137 ;
     RECT  67.215 122.867 67.305 123.137 ;
     RECT  72.615 122.867 72.705 123.137 ;
     RECT  78.015 122.867 78.105 123.137 ;
     RECT  83.415 122.867 83.505 123.137 ;
     RECT  88.815 122.867 88.905 123.137 ;
     RECT  94.215 122.867 94.305 123.137 ;
     RECT  99.615 122.867 99.705 123.137 ;
     RECT  105.015 122.867 105.105 123.137 ;
     RECT  110.415 122.867 110.505 123.137 ;
     RECT  115.815 122.867 115.905 123.137 ;
     RECT  121.215 122.867 121.305 123.137 ;
     RECT  126.615 122.867 126.705 123.137 ;
     RECT  132.015 122.867 132.105 123.137 ;
     RECT  137.415 122.867 137.505 123.137 ;
     RECT  142.815 122.867 142.905 123.137 ;
     RECT  148.215 122.867 148.305 123.137 ;
     RECT  153.615 122.867 153.705 123.137 ;
     RECT  159.015 122.867 159.105 123.137 ;
     RECT  164.415 122.867 164.505 123.137 ;
     RECT  169.815 122.867 169.905 123.137 ;
     RECT  175.215 122.867 175.305 123.137 ;
     RECT  180.615 122.867 180.705 123.137 ;
     RECT  186.015 122.867 186.105 123.137 ;
     RECT  191.415 122.867 191.505 123.137 ;
     RECT  196.815 122.867 196.905 123.137 ;
     RECT  207.615 122.867 207.705 123.137 ;
     RECT  213.015 122.867 213.105 123.137 ;
     RECT  200.952 123.101 202.77 123.293 ;
     RECT  200.952 123.293 202.194 123.677 ;
     RECT  200.952 123.677 201.078 123.725 ;
     RECT  201.06 123.725 201.078 124.301 ;
    LAYER M4 ;
     RECT  0.084 29.328 0.133 29.352 ;
     RECT  0.06 29.352 0.133 29.424 ;
     RECT  0.084 29.424 0.133 29.448 ;
     RECT  0.06 29.448 0.133 29.52 ;
     RECT  0.084 29.52 0.133 29.544 ;
     RECT  0.06 29.544 0.133 29.616 ;
     RECT  0.084 29.616 0.133 29.64 ;
     RECT  0.06 29.64 0.133 29.712 ;
     RECT  0.084 29.712 0.133 29.736 ;
     RECT  0.06 29.736 0.133 29.808 ;
     RECT  0.084 29.808 0.133 29.832 ;
     RECT  0.06 29.832 0.133 29.904 ;
     RECT  0.084 29.904 0.133 29.928 ;
     RECT  0.06 29.928 0.133 30 ;
     RECT  0.084 30 0.133 30.024 ;
     RECT  0.06 30.024 0.133 30.096 ;
     RECT  0.084 30.096 0.133 30.12 ;
     RECT  0.06 30.12 0.133 30.192 ;
     RECT  0.084 30.192 0.133 30.216 ;
     RECT  0.06 30.216 0.133 30.288 ;
     RECT  0.084 30.288 0.133 30.312 ;
     RECT  0.06 30.312 0.133 30.384 ;
     RECT  0.084 30.384 0.133 30.408 ;
     RECT  0.06 30.408 0.133 30.48 ;
     RECT  0.084 30.48 0.133 30.504 ;
     RECT  0.06 30.504 0.133 30.576 ;
     RECT  0.084 30.576 0.133 30.6 ;
     RECT  0.06 30.6 0.133 30.672 ;
     RECT  0.084 30.672 0.133 30.696 ;
     RECT  0.06 30.696 0.133 30.768 ;
     RECT  0.084 30.768 0.133 30.792 ;
     RECT  0.06 30.792 0.133 30.864 ;
     RECT  0.084 30.864 0.133 30.888 ;
     RECT  0.06 30.888 0.133 30.96 ;
     RECT  0.084 30.96 0.133 30.984 ;
     RECT  0.06 30.984 0.133 31.056 ;
     RECT  0.084 31.056 0.133 31.08 ;
     RECT  0.06 31.08 0.133 31.152 ;
     RECT  0.084 31.152 0.133 31.176 ;
     RECT  0.06 31.176 0.133 31.248 ;
     RECT  0.084 31.248 0.133 31.272 ;
     RECT  0.06 31.272 0.133 31.344 ;
     RECT  0.084 31.344 0.133 31.368 ;
     RECT  0.06 31.368 0.133 31.44 ;
     RECT  0.084 31.44 0.133 31.464 ;
     RECT  0.06 31.464 0.133 31.536 ;
     RECT  0.084 31.536 0.133 31.56 ;
     RECT  0.06 31.56 0.133 31.632 ;
     RECT  0.084 31.632 0.133 31.656 ;
     RECT  0.06 31.656 0.133 31.728 ;
     RECT  0.084 31.728 0.133 31.752 ;
     RECT  0.06 31.752 0.133 31.824 ;
     RECT  0.084 31.824 0.133 31.848 ;
     RECT  0.06 31.848 0.133 31.92 ;
     RECT  0.084 31.92 0.133 31.944 ;
     RECT  0.06 31.944 0.133 32.016 ;
     RECT  0.084 32.016 0.133 32.04 ;
     RECT  0.06 32.04 0.133 32.112 ;
     RECT  0.084 32.112 0.133 32.136 ;
     RECT  0.06 32.136 0.133 32.208 ;
     RECT  0.084 32.208 0.133 32.232 ;
     RECT  0.06 32.232 0.133 32.304 ;
     RECT  0.084 32.304 0.133 32.328 ;
     RECT  0.06 32.328 0.133 32.4 ;
     RECT  0.084 32.4 0.133 32.424 ;
     RECT  0.06 32.424 0.133 32.496 ;
     RECT  0.084 32.496 0.133 32.52 ;
     RECT  0.06 32.52 0.133 32.592 ;
     RECT  0.084 32.592 0.133 32.616 ;
     RECT  0.06 32.616 0.133 32.688 ;
     RECT  0.084 32.688 0.133 32.712 ;
     RECT  0.06 32.712 0.133 32.784 ;
     RECT  0.084 32.784 0.133 32.808 ;
     RECT  0.06 32.808 0.133 32.88 ;
     RECT  0.084 32.88 0.133 32.904 ;
     RECT  0.06 32.904 0.133 32.976 ;
     RECT  0.084 32.976 0.133 33 ;
     RECT  0.06 33 0.133 33.072 ;
     RECT  0.084 33.072 0.133 33.096 ;
     RECT  0.06 33.096 0.133 33.168 ;
     RECT  0.084 33.168 0.133 33.192 ;
     RECT  0.06 33.192 0.133 33.264 ;
     RECT  0.084 33.264 0.133 33.288 ;
     RECT  0.06 33.288 0.133 33.36 ;
     RECT  0.084 33.36 0.133 33.384 ;
     RECT  0.06 33.384 0.133 33.456 ;
     RECT  0.084 33.456 0.133 33.48 ;
     RECT  0.06 33.48 0.133 33.552 ;
     RECT  0.084 33.552 0.133 33.576 ;
     RECT  0.06 33.576 0.133 33.648 ;
     RECT  0.084 33.648 0.133 33.672 ;
     RECT  0.06 33.672 0.133 33.744 ;
     RECT  0.084 33.744 0.133 33.768 ;
     RECT  0.06 33.768 0.133 33.84 ;
     RECT  0.084 33.84 0.133 33.864 ;
     RECT  0.06 33.864 0.133 33.936 ;
     RECT  0.084 33.936 0.133 33.96 ;
     RECT  0.06 33.96 0.133 34.032 ;
     RECT  0.084 34.032 0.133 34.056 ;
     RECT  0.06 34.056 0.133 34.128 ;
     RECT  0.084 34.128 0.133 34.152 ;
     RECT  0.06 34.152 0.133 34.224 ;
     RECT  0.084 34.224 0.133 34.248 ;
     RECT  0.06 34.248 0.133 34.32 ;
     RECT  0.084 34.32 0.133 34.344 ;
     RECT  0.06 34.344 0.133 34.416 ;
     RECT  0.084 34.416 0.133 34.44 ;
     RECT  0.06 34.44 0.133 34.512 ;
     RECT  0.084 34.512 0.133 34.536 ;
     RECT  0.06 34.536 0.133 34.608 ;
     RECT  0.084 34.608 0.133 34.632 ;
     RECT  0.06 34.632 0.133 34.704 ;
     RECT  0.084 34.704 0.133 34.728 ;
     RECT  0.06 34.728 0.133 34.8 ;
     RECT  0.084 34.8 0.133 34.824 ;
     RECT  0.06 34.824 0.133 34.896 ;
     RECT  0.084 34.896 0.133 34.92 ;
     RECT  0.06 34.92 0.133 34.992 ;
     RECT  0.084 34.992 0.133 35.016 ;
     RECT  0.06 35.016 0.133 35.088 ;
     RECT  0.084 35.088 0.133 35.112 ;
     RECT  0.06 35.112 0.133 35.184 ;
     RECT  0.084 35.184 0.133 35.208 ;
     RECT  0.06 35.208 0.133 35.28 ;
     RECT  0.084 35.28 0.133 35.304 ;
     RECT  0.06 35.304 0.133 35.376 ;
     RECT  0.084 35.376 0.133 35.4 ;
     RECT  0.06 35.4 0.133 35.472 ;
     RECT  0.084 35.472 0.133 35.496 ;
     RECT  0.06 35.496 0.133 35.568 ;
     RECT  0.084 35.568 0.133 35.592 ;
     RECT  0.06 35.592 0.133 35.664 ;
     RECT  0.084 35.664 0.133 35.688 ;
     RECT  0.06 35.688 0.133 35.76 ;
     RECT  0.084 35.76 0.133 35.784 ;
     RECT  0.06 35.784 0.133 35.856 ;
     RECT  0.084 35.856 0.133 35.88 ;
     RECT  0.06 35.88 0.133 35.952 ;
     RECT  0.084 35.952 0.133 35.976 ;
     RECT  0.06 35.976 0.133 36.048 ;
     RECT  0.084 36.048 0.133 36.072 ;
     RECT  0.06 36.072 0.133 36.144 ;
     RECT  0.084 36.144 0.133 36.168 ;
     RECT  0.06 36.168 0.133 36.24 ;
     RECT  0.084 36.24 0.133 36.264 ;
     RECT  0.06 36.264 0.133 36.336 ;
     RECT  0.084 36.336 0.133 36.36 ;
     RECT  0.06 36.36 0.133 36.432 ;
     RECT  0.084 36.432 0.133 36.456 ;
     RECT  0.06 36.456 0.133 36.528 ;
     RECT  0.084 36.528 0.133 36.552 ;
     RECT  0.06 36.552 0.133 36.624 ;
     RECT  0.084 36.624 0.133 36.648 ;
     RECT  0.06 36.648 0.133 36.72 ;
     RECT  0.084 36.72 0.133 36.744 ;
     RECT  0.06 36.744 0.133 36.816 ;
     RECT  0.084 36.816 0.133 36.84 ;
     RECT  0.06 36.84 0.133 36.912 ;
     RECT  0.084 36.912 0.133 36.936 ;
     RECT  0.06 36.936 0.133 37.008 ;
     RECT  0.084 37.008 0.133 37.032 ;
     RECT  0.06 37.032 0.133 37.104 ;
     RECT  0.084 37.104 0.133 37.128 ;
     RECT  0.06 37.128 0.133 37.2 ;
     RECT  0.084 37.2 0.133 37.224 ;
     RECT  0.06 37.224 0.133 37.296 ;
     RECT  0.084 37.296 0.133 37.32 ;
     RECT  0.06 37.32 0.133 37.392 ;
     RECT  0.084 37.392 0.133 37.416 ;
     RECT  0.06 37.416 0.133 37.488 ;
     RECT  0.084 37.488 0.133 37.512 ;
     RECT  0.06 37.512 0.133 37.584 ;
     RECT  0.084 37.584 0.133 37.608 ;
     RECT  0.06 37.608 0.133 37.68 ;
     RECT  0.084 37.68 0.133 37.704 ;
     RECT  0.06 37.704 0.133 37.776 ;
     RECT  0.084 37.776 0.133 37.8 ;
     RECT  0.06 37.8 0.133 37.872 ;
     RECT  0.084 37.872 0.133 37.896 ;
     RECT  0.06 37.896 0.133 37.968 ;
     RECT  0.084 37.968 0.133 37.992 ;
     RECT  0.06 37.992 0.133 38.064 ;
     RECT  0.084 38.064 0.133 38.088 ;
     RECT  0.06 38.088 0.133 38.16 ;
     RECT  0.084 38.16 0.133 38.184 ;
     RECT  0.06 38.184 0.133 38.256 ;
     RECT  0.084 38.256 0.133 38.28 ;
     RECT  0.06 38.28 0.133 38.352 ;
     RECT  0.084 38.352 0.133 38.376 ;
     RECT  0.06 38.376 0.133 38.448 ;
     RECT  0.084 38.448 0.133 38.472 ;
     RECT  0.06 38.472 0.133 38.544 ;
     RECT  0.084 38.544 0.133 38.568 ;
     RECT  0.06 38.568 0.133 38.64 ;
     RECT  0.084 38.64 0.133 38.664 ;
     RECT  0.06 38.664 0.133 38.736 ;
     RECT  0.084 38.736 0.133 38.76 ;
     RECT  0.06 38.76 0.133 38.832 ;
     RECT  0.084 38.832 0.133 38.856 ;
     RECT  0.06 38.856 0.133 38.928 ;
     RECT  0.084 38.928 0.133 38.952 ;
     RECT  0.06 38.952 0.133 39.024 ;
     RECT  0.084 39.024 0.133 39.048 ;
     RECT  0.06 39.048 0.133 39.12 ;
     RECT  0.084 39.12 0.133 39.144 ;
     RECT  0.06 39.144 0.133 39.216 ;
     RECT  0.084 39.216 0.133 39.24 ;
     RECT  0.06 39.24 0.133 39.312 ;
     RECT  0.084 39.312 0.133 39.336 ;
     RECT  0.06 39.336 0.133 39.408 ;
     RECT  0.084 39.408 0.133 39.432 ;
     RECT  0.06 39.432 0.133 39.504 ;
     RECT  0.084 39.504 0.133 39.528 ;
     RECT  0.06 39.528 0.133 39.6 ;
     RECT  0.084 39.6 0.133 39.624 ;
     RECT  0.06 39.624 0.133 39.696 ;
     RECT  0.084 39.696 0.133 39.72 ;
     RECT  0.06 39.72 0.133 39.792 ;
     RECT  0.084 39.792 0.133 39.816 ;
     RECT  0.06 39.816 0.133 39.888 ;
     RECT  0.084 39.888 0.133 39.912 ;
     RECT  0.06 39.912 0.133 39.984 ;
     RECT  0.084 39.984 0.133 40.008 ;
     RECT  0.06 40.008 0.133 40.08 ;
     RECT  0.084 40.08 0.133 40.104 ;
     RECT  0.06 40.104 0.133 40.176 ;
     RECT  0.084 40.176 0.133 40.2 ;
     RECT  0.06 40.2 0.133 40.272 ;
     RECT  0.084 40.272 0.133 40.296 ;
     RECT  0.06 40.296 0.133 40.368 ;
     RECT  0.084 40.368 0.133 40.392 ;
     RECT  0.06 40.392 0.133 40.464 ;
     RECT  0.084 40.464 0.133 40.488 ;
     RECT  0.06 40.488 0.133 40.56 ;
     RECT  0.084 40.56 0.133 40.584 ;
     RECT  0.06 40.584 0.133 40.656 ;
     RECT  0.084 40.656 0.133 40.68 ;
     RECT  0.06 40.68 0.133 40.752 ;
     RECT  0.084 40.752 0.133 40.776 ;
     RECT  0.06 40.776 0.133 40.848 ;
     RECT  0.084 40.848 0.133 40.872 ;
     RECT  0.06 40.872 0.133 40.944 ;
     RECT  0.084 40.944 0.133 40.968 ;
     RECT  0.06 40.968 0.133 41.04 ;
     RECT  0.084 41.04 0.133 41.064 ;
     RECT  0.06 41.064 0.133 41.136 ;
     RECT  0.084 41.136 0.133 41.16 ;
     RECT  0.06 41.16 0.133 41.232 ;
     RECT  0.084 41.232 0.133 41.256 ;
     RECT  0.06 41.256 0.133 41.328 ;
     RECT  0.084 41.328 0.133 41.352 ;
     RECT  0.06 41.352 0.133 41.424 ;
     RECT  0.084 41.424 0.133 41.448 ;
     RECT  0.06 41.448 0.133 41.52 ;
     RECT  0.084 41.52 0.133 41.544 ;
     RECT  0.084 54.672 0.133 54.696 ;
     RECT  0.06 54.696 0.133 54.768 ;
     RECT  0.084 54.768 0.133 54.792 ;
     RECT  0.06 54.792 0.133 54.864 ;
     RECT  0.084 54.864 0.133 54.888 ;
     RECT  0.06 54.888 0.133 54.96 ;
     RECT  0.084 54.96 0.133 54.984 ;
     RECT  0.06 54.984 0.133 55.056 ;
     RECT  0.084 55.056 0.133 55.08 ;
     RECT  0.06 55.08 0.133 55.152 ;
     RECT  0.084 55.152 0.133 55.176 ;
     RECT  0.06 55.176 0.133 55.248 ;
     RECT  0.084 55.248 0.133 55.272 ;
     RECT  0.06 55.272 0.133 55.344 ;
     RECT  0.084 55.344 0.133 55.368 ;
     RECT  0.06 55.368 0.133 55.44 ;
     RECT  0.084 55.44 0.133 55.464 ;
     RECT  0.06 55.464 0.133 55.536 ;
     RECT  0.084 55.536 0.133 55.56 ;
     RECT  0.06 55.56 0.133 55.632 ;
     RECT  0.084 55.632 0.133 55.656 ;
     RECT  0.06 55.656 0.133 55.728 ;
     RECT  0.084 55.728 0.133 55.752 ;
     RECT  0.06 55.752 0.133 55.824 ;
     RECT  0.084 55.824 0.133 55.848 ;
     RECT  0.06 55.848 0.133 55.92 ;
     RECT  0.084 55.92 0.133 55.944 ;
     RECT  0.06 55.944 0.133 56.016 ;
     RECT  0.084 56.016 0.133 56.04 ;
     RECT  0.06 56.04 0.133 56.112 ;
     RECT  0.084 56.112 0.133 56.136 ;
     RECT  0.06 56.136 0.133 56.208 ;
     RECT  0.084 56.208 0.133 56.232 ;
     RECT  0.06 56.232 0.133 56.304 ;
     RECT  0.084 56.304 0.133 56.328 ;
     RECT  0.06 56.328 0.133 56.4 ;
     RECT  0.084 56.4 0.133 56.424 ;
     RECT  0.06 56.424 0.133 56.496 ;
     RECT  0.084 56.496 0.133 56.52 ;
     RECT  0.06 56.52 0.133 56.592 ;
     RECT  0.084 56.592 0.133 56.616 ;
     RECT  0.06 56.616 0.133 56.688 ;
     RECT  0.084 56.688 0.133 56.712 ;
     RECT  0.06 56.712 0.133 56.784 ;
     RECT  0.084 56.784 0.133 56.808 ;
     RECT  0.06 56.808 0.133 56.88 ;
     RECT  0.084 56.88 0.133 56.904 ;
     RECT  0.06 56.904 0.133 56.976 ;
     RECT  0.084 56.976 0.133 57 ;
     RECT  0.06 57 0.133 57.072 ;
     RECT  0.084 57.072 0.133 57.096 ;
     RECT  0.06 57.096 0.133 57.168 ;
     RECT  0.084 57.168 0.133 57.192 ;
     RECT  0.06 57.192 0.133 57.264 ;
     RECT  0.084 57.264 0.133 57.288 ;
     RECT  0.06 57.288 0.133 57.36 ;
     RECT  0.084 57.36 0.133 57.384 ;
     RECT  0.06 57.384 0.133 57.456 ;
     RECT  0.084 57.456 0.133 57.48 ;
     RECT  0.06 57.48 0.133 57.552 ;
     RECT  0.084 57.552 0.133 57.576 ;
     RECT  0.06 57.576 0.133 57.648 ;
     RECT  0.084 57.648 0.133 57.672 ;
     RECT  0.06 57.672 0.133 57.744 ;
     RECT  0.084 57.744 0.133 57.768 ;
     RECT  0.06 57.768 0.133 57.84 ;
     RECT  0.084 57.84 0.133 57.864 ;
     RECT  0.06 57.864 0.133 57.936 ;
     RECT  0.084 57.936 0.133 57.96 ;
     RECT  0.06 57.96 0.133 58.032 ;
     RECT  0.084 58.032 0.133 58.056 ;
     RECT  0.06 58.056 0.133 58.128 ;
     RECT  0.084 58.128 0.133 58.152 ;
     RECT  0.06 58.152 0.133 58.224 ;
     RECT  0.084 58.224 0.133 58.248 ;
     RECT  0.06 58.248 0.133 58.32 ;
     RECT  0.084 58.32 0.133 58.344 ;
     RECT  0.06 58.344 0.133 58.416 ;
     RECT  0.084 58.416 0.133 58.44 ;
     RECT  0.06 58.44 0.133 58.512 ;
     RECT  0.084 58.512 0.133 58.536 ;
     RECT  0.06 58.536 0.133 58.608 ;
     RECT  0.084 58.608 0.133 58.632 ;
     RECT  0.06 58.632 0.133 58.704 ;
     RECT  0.084 58.704 0.133 58.728 ;
     RECT  0.06 58.728 0.133 58.8 ;
     RECT  0.084 58.8 0.133 58.824 ;
     RECT  0.06 58.824 0.133 58.896 ;
     RECT  0.084 58.896 0.133 58.92 ;
     RECT  0.06 58.92 0.133 58.992 ;
     RECT  0.084 58.992 0.133 59.016 ;
     RECT  0.06 59.016 0.133 59.088 ;
     RECT  0.084 59.088 0.133 59.112 ;
     RECT  0.06 59.112 0.133 59.184 ;
     RECT  0.084 59.184 0.133 59.208 ;
     RECT  0.06 59.208 0.133 59.28 ;
     RECT  0.084 59.28 0.133 59.304 ;
     RECT  0.06 59.304 0.133 59.376 ;
     RECT  0.084 59.376 0.133 59.4 ;
     RECT  0.06 59.4 0.133 59.472 ;
     RECT  0.084 59.472 0.133 59.496 ;
     RECT  0.06 59.496 0.133 59.568 ;
     RECT  0.084 59.568 0.133 59.592 ;
     RECT  0.06 59.592 0.133 59.664 ;
     RECT  0.084 59.664 0.133 59.688 ;
     RECT  0.06 59.688 0.133 59.76 ;
     RECT  0.084 59.76 0.133 59.784 ;
     RECT  0.06 59.784 0.133 59.856 ;
     RECT  0.084 59.856 0.133 59.88 ;
     RECT  0.06 59.88 0.133 59.952 ;
     RECT  0.084 59.952 0.133 59.976 ;
     RECT  0.06 59.976 0.133 60.048 ;
     RECT  0.084 60.048 0.133 60.072 ;
     RECT  0.06 60.072 0.133 60.144 ;
     RECT  0.084 60.144 0.133 60.168 ;
     RECT  0.06 60.168 0.133 60.24 ;
     RECT  0.084 60.24 0.133 60.264 ;
     RECT  0.06 60.264 0.133 60.336 ;
     RECT  0.084 60.336 0.133 60.36 ;
     RECT  0.06 60.36 0.133 60.432 ;
     RECT  0.084 60.432 0.133 60.456 ;
     RECT  0.06 60.456 0.133 60.528 ;
     RECT  0.084 60.528 0.133 60.552 ;
     RECT  0.06 60.552 0.133 60.624 ;
     RECT  0.084 60.624 0.133 60.648 ;
     RECT  0.06 60.648 0.133 60.72 ;
     RECT  0.084 60.72 0.133 60.744 ;
     RECT  0.06 60.744 0.133 60.816 ;
     RECT  0.084 60.816 0.133 60.84 ;
     RECT  0.06 60.84 0.133 60.912 ;
     RECT  0.084 60.912 0.133 60.936 ;
     RECT  0.06 60.936 0.133 61.008 ;
     RECT  0.084 61.008 0.133 61.032 ;
     RECT  0.06 61.032 0.133 61.104 ;
     RECT  0.084 61.104 0.133 61.128 ;
     RECT  0.06 61.128 0.133 61.2 ;
     RECT  0.084 61.2 0.133 61.224 ;
     RECT  0.06 61.224 0.133 61.296 ;
     RECT  0.084 61.296 0.133 61.32 ;
     RECT  0.06 61.32 0.133 61.392 ;
     RECT  0.084 61.392 0.133 61.416 ;
     RECT  0.06 61.416 0.133 61.488 ;
     RECT  0.084 61.488 0.133 61.512 ;
     RECT  0.06 61.512 0.133 61.584 ;
     RECT  0.084 61.584 0.133 61.608 ;
     RECT  0.06 61.608 0.133 61.68 ;
     RECT  0.084 61.68 0.133 61.704 ;
     RECT  0.06 61.704 0.133 61.776 ;
     RECT  0.084 61.776 0.133 61.8 ;
     RECT  0.06 61.8 0.133 61.872 ;
     RECT  0.084 61.872 0.133 61.896 ;
     RECT  0.06 61.896 0.133 61.968 ;
     RECT  0.084 61.968 0.133 61.992 ;
     RECT  0.06 61.992 0.133 62.064 ;
     RECT  0.084 62.064 0.133 62.088 ;
     RECT  0.06 62.088 0.133 62.16 ;
     RECT  0.084 62.16 0.133 62.184 ;
     RECT  0.06 62.184 0.133 62.256 ;
     RECT  0.084 62.256 0.133 62.28 ;
     RECT  0.06 62.28 0.133 62.352 ;
     RECT  0.084 62.352 0.133 62.376 ;
     RECT  0.06 62.376 0.133 62.448 ;
     RECT  0.084 62.448 0.133 62.472 ;
     RECT  0.06 62.472 0.133 62.544 ;
     RECT  0.084 62.544 0.133 62.568 ;
     RECT  0.06 62.568 0.133 62.64 ;
     RECT  0.084 62.64 0.133 62.664 ;
     RECT  0.06 62.664 0.133 62.736 ;
     RECT  0.084 62.736 0.133 62.76 ;
     RECT  0.06 62.76 0.133 62.832 ;
     RECT  0.084 62.832 0.133 62.856 ;
     RECT  0.06 62.856 0.133 62.928 ;
     RECT  0.084 62.928 0.133 62.952 ;
     RECT  0.06 62.952 0.133 63.024 ;
     RECT  0.084 63.024 0.133 63.048 ;
     RECT  0.06 63.048 0.133 63.12 ;
     RECT  0.084 63.12 0.133 63.144 ;
     RECT  0.06 63.144 0.133 63.216 ;
     RECT  0.084 63.216 0.133 63.24 ;
     RECT  0.06 63.24 0.133 63.312 ;
     RECT  0.084 63.312 0.133 63.336 ;
     RECT  0.06 63.336 0.133 63.408 ;
     RECT  0.084 63.408 0.133 63.432 ;
     RECT  0.06 63.432 0.133 63.504 ;
     RECT  0.084 63.504 0.133 63.528 ;
     RECT  0.06 63.528 0.133 63.6 ;
     RECT  0.084 63.6 0.133 63.624 ;
     RECT  0.06 63.624 0.133 63.696 ;
     RECT  0.084 63.696 0.133 63.72 ;
     RECT  0.06 63.72 0.133 63.792 ;
     RECT  0.084 63.792 0.133 63.816 ;
     RECT  0.06 63.816 0.133 63.888 ;
     RECT  0.084 63.888 0.133 63.912 ;
     RECT  0.06 63.912 0.133 63.984 ;
     RECT  0.084 63.984 0.133 64.008 ;
     RECT  0.06 64.008 0.133 64.08 ;
     RECT  0.084 64.08 0.133 64.104 ;
     RECT  0.06 64.104 0.133 64.176 ;
     RECT  0.084 64.176 0.133 64.2 ;
     RECT  0.06 64.2 0.133 64.272 ;
     RECT  0.084 64.272 0.133 64.296 ;
     RECT  0.06 64.296 0.133 64.368 ;
     RECT  0.084 64.368 0.133 64.392 ;
     RECT  0.06 64.392 0.133 64.464 ;
     RECT  0.084 64.464 0.133 64.488 ;
     RECT  0.06 64.488 0.133 64.56 ;
     RECT  0.084 64.56 0.133 64.584 ;
     RECT  0.06 64.584 0.133 64.656 ;
     RECT  0.084 64.656 0.133 64.68 ;
     RECT  0.06 64.68 0.133 64.752 ;
     RECT  0.084 64.752 0.133 64.776 ;
     RECT  0.06 64.776 0.133 64.848 ;
     RECT  0.084 64.848 0.133 64.872 ;
     RECT  0.06 64.872 0.133 64.944 ;
     RECT  0.084 64.944 0.133 64.968 ;
     RECT  0.06 64.968 0.133 65.04 ;
     RECT  0.084 65.04 0.133 65.064 ;
     RECT  0.06 65.064 0.133 65.136 ;
     RECT  0.084 65.136 0.133 65.16 ;
     RECT  0.06 65.16 0.133 65.232 ;
     RECT  0.084 65.232 0.133 65.256 ;
     RECT  0.06 65.256 0.133 65.328 ;
     RECT  0.084 65.328 0.133 65.352 ;
     RECT  0.06 65.352 0.133 65.424 ;
     RECT  0.084 65.424 0.133 65.448 ;
     RECT  0.06 65.448 0.133 65.52 ;
     RECT  0.084 65.52 0.133 65.544 ;
     RECT  0.06 65.544 0.133 65.616 ;
     RECT  0.084 65.616 0.133 65.64 ;
     RECT  0.06 65.64 0.133 65.712 ;
     RECT  0.084 65.712 0.133 65.736 ;
     RECT  0.06 65.736 0.133 65.808 ;
     RECT  0.084 65.808 0.133 65.832 ;
     RECT  0.06 65.832 0.133 65.904 ;
     RECT  0.084 65.904 0.133 65.928 ;
     RECT  0.06 65.928 0.133 66 ;
     RECT  0.084 66 0.133 66.024 ;
     RECT  0.06 66.024 0.133 66.096 ;
     RECT  0.084 66.096 0.133 66.12 ;
     RECT  0.06 66.12 0.133 66.192 ;
     RECT  0.084 66.192 0.133 66.216 ;
     RECT  0.06 66.216 0.133 66.288 ;
     RECT  0.084 66.288 0.133 66.312 ;
     RECT  0.06 66.312 0.133 66.384 ;
     RECT  0.084 66.384 0.133 66.408 ;
     RECT  0.06 66.408 0.133 66.48 ;
     RECT  0.084 66.48 0.133 66.504 ;
     RECT  0.06 66.504 0.133 66.576 ;
     RECT  0.084 66.576 0.133 66.6 ;
     RECT  0.06 66.6 0.133 66.672 ;
     RECT  0.084 66.672 0.133 66.696 ;
     RECT  0.06 66.696 0.133 66.768 ;
     RECT  0.084 66.768 0.133 66.792 ;
     RECT  0.06 66.792 0.133 66.864 ;
     RECT  0.084 66.864 0.133 66.888 ;
     RECT  0.084 46.704 0.137 46.728 ;
     RECT  0.06 46.728 0.137 46.8 ;
     RECT  0.084 46.8 0.137 46.824 ;
     RECT  0.06 46.824 0.137 46.896 ;
     RECT  0.084 46.896 0.137 46.92 ;
     RECT  0.06 46.92 0.137 46.992 ;
     RECT  0.084 46.992 0.137 47.016 ;
     RECT  0.06 47.016 0.137 47.088 ;
     RECT  0.084 47.088 0.137 47.112 ;
     RECT  0.06 47.112 0.137 47.184 ;
     RECT  0.084 47.184 0.137 47.208 ;
     RECT  0.06 47.208 0.137 47.28 ;
     RECT  0.084 47.28 0.137 47.304 ;
     RECT  0.06 47.304 0.137 47.376 ;
     RECT  0.084 47.376 0.137 47.4 ;
     RECT  0.06 47.4 0.137 47.472 ;
     RECT  0.084 47.472 0.137 47.496 ;
     RECT  0.06 47.496 0.137 47.568 ;
     RECT  0.084 47.568 0.137 47.592 ;
     RECT  0.06 47.592 0.137 47.664 ;
     RECT  0.084 47.664 0.137 47.688 ;
     RECT  0.133 54.48 0.181 67.848 ;
     RECT  0.133 28.464 0.229 41.592 ;
     RECT  0.133 42.768 0.229 42.792 ;
     RECT  0.181 54.096 0.373 67.848 ;
     RECT  0.373 53.904 1.217 67.848 ;
     RECT  1.217 67.824 2.293 67.848 ;
     RECT  0.229 28.464 2.408 42.792 ;
     RECT  0.137 46.8 2.408 47.496 ;
     RECT  1.217 53.904 2.408 66.792 ;
     RECT  2.293 67.776 2.408 68.472 ;
     RECT  2.408 2.148 2.512 123.132 ;
     RECT  2.512 2.418 2.704 122.862 ;
     RECT  2.704 28.368 3.107 43.272 ;
     RECT  2.704 47.376 3.521 47.4 ;
     RECT  2.704 53.52 3.521 68.856 ;
     RECT  3.521 53.568 3.587 68.856 ;
     RECT  3.781 46.08 3.913 46.104 ;
     RECT  2.704 80.4 3.953 80.424 ;
     RECT  3.877 50.112 3.964 50.136 ;
     RECT  3.587 53.568 3.971 68.712 ;
     RECT  3.913 46.08 3.989 46.728 ;
     RECT  3.905 70.128 3.989 70.152 ;
     RECT  3.971 53.952 4.061 68.712 ;
     RECT  3.107 28.416 4.069 43.272 ;
     RECT  4.069 28.416 4.213 43.416 ;
     RECT  4.213 28.368 4.421 43.416 ;
     RECT  4.061 53.952 4.499 68.568 ;
     RECT  4.421 35.424 4.529 43.416 ;
     RECT  4.499 54 4.817 68.568 ;
     RECT  4.817 54.096 5.123 68.568 ;
     RECT  4.421 28.368 5.132 34.44 ;
     RECT  3.989 46.704 5.317 46.728 ;
     RECT  5.317 46.704 5.357 46.824 ;
     RECT  5.132 28.32 5.389 34.44 ;
     RECT  4.529 35.424 5.389 43.368 ;
     RECT  3.829 101.376 5.413 101.4 ;
     RECT  5.389 28.32 5.468 43.368 ;
     RECT  5.468 27.888 5.555 43.368 ;
     RECT  5.123 54.672 5.653 68.568 ;
     RECT  5.653 54.672 5.74 68.856 ;
     RECT  5.357 46.752 5.749 46.824 ;
     RECT  4.417 47.856 5.749 47.88 ;
     RECT  5.749 46.752 5.861 47.88 ;
     RECT  5.555 28.368 5.869 43.368 ;
     RECT  3.685 23.28 5.941 23.304 ;
     RECT  5.74 54.672 5.977 68.28 ;
     RECT  5.861 46.752 5.987 47.352 ;
     RECT  5.977 55.008 5.987 68.28 ;
     RECT  5.965 50.688 6.049 50.712 ;
     RECT  5.987 55.008 6.179 67.848 ;
     RECT  5.941 22.464 6.421 23.304 ;
     RECT  6.179 55.008 6.437 67.8 ;
     RECT  6.437 55.008 6.581 64.392 ;
     RECT  6.581 56.88 6.653 64.392 ;
     RECT  5.869 28.368 6.716 42.792 ;
     RECT  6.716 28.32 6.725 42.792 ;
     RECT  6.725 28.32 6.797 42.216 ;
     RECT  6.797 28.32 6.803 28.344 ;
     RECT  6.421 22.464 6.997 23.592 ;
     RECT  4.741 24.72 6.997 24.744 ;
     RECT  6.581 55.008 7.004 55.8 ;
     RECT  5.987 47.328 7.045 47.352 ;
     RECT  6.653 58.416 7.621 64.392 ;
     RECT  6.437 65.376 7.621 67.8 ;
     RECT  7.477 19.248 7.808 19.272 ;
     RECT  6.997 22.464 7.808 24.744 ;
     RECT  7.045 25.824 7.808 25.848 ;
     RECT  5.749 27.072 7.808 27.096 ;
     RECT  6.797 29.664 7.808 42.216 ;
     RECT  6.325 44.928 7.808 44.952 ;
     RECT  7.045 47.328 7.808 48.264 ;
     RECT  6.217 50.448 7.808 50.472 ;
     RECT  7.004 54.672 7.808 55.8 ;
     RECT  6.653 56.88 7.808 57.384 ;
     RECT  7.621 58.416 7.808 67.8 ;
     RECT  6.901 78.912 7.808 78.936 ;
     RECT  7.621 84.864 7.808 84.888 ;
     RECT  4.741 88.368 7.808 88.392 ;
     RECT  5.413 100.512 7.808 101.4 ;
     RECT  5.077 102.384 7.808 102.408 ;
     RECT  7.808 2.148 7.912 123.132 ;
     RECT  7.912 2.418 8.104 122.862 ;
     RECT  8.104 29.808 8.201 30.888 ;
     RECT  8.104 32.208 8.273 35.784 ;
     RECT  8.104 56.88 8.273 56.904 ;
     RECT  8.104 59.712 8.273 59.88 ;
     RECT  8.104 62.256 8.273 67.128 ;
     RECT  8.273 62.256 8.309 64.2 ;
     RECT  8.104 44.928 8.381 44.952 ;
     RECT  8.104 47.424 8.381 47.448 ;
     RECT  8.309 62.256 8.381 62.856 ;
     RECT  8.309 64.176 8.417 64.2 ;
     RECT  8.273 65.232 8.417 67.128 ;
     RECT  8.104 37.008 8.489 41.976 ;
     RECT  8.381 62.256 8.525 62.28 ;
     RECT  8.417 65.76 8.525 67.128 ;
     RECT  8.489 38.16 8.561 41.976 ;
     RECT  8.561 39.36 8.597 41.976 ;
     RECT  8.525 65.76 8.597 66.552 ;
     RECT  8.597 65.76 8.633 65.784 ;
     RECT  8.489 37.008 8.857 37.032 ;
     RECT  8.597 39.36 8.885 41.448 ;
     RECT  8.885 39.792 8.921 41.448 ;
     RECT  8.273 32.208 9.029 35.736 ;
     RECT  9.029 32.208 9.137 35.544 ;
     RECT  9.137 33.36 9.245 35.544 ;
     RECT  8.921 39.792 9.281 41.16 ;
     RECT  9.281 40.8 9.677 41.16 ;
     RECT  9.677 40.8 10.109 40.824 ;
     RECT  9.137 32.208 10.825 32.232 ;
     RECT  10.825 32.112 10.861 32.232 ;
     RECT  9.245 33.36 10.861 35.496 ;
     RECT  10.861 32.112 10.973 35.496 ;
     RECT  10.973 33.36 11.117 35.496 ;
     RECT  8.104 19.248 11.441 19.272 ;
     RECT  9.281 39.792 11.621 39.816 ;
     RECT  8.201 29.856 11.977 30.888 ;
     RECT  11.117 34.656 12.089 35.496 ;
     RECT  11.117 33.36 12.517 33.576 ;
     RECT  8.104 22.464 12.613 24.744 ;
     RECT  8.104 25.824 12.613 25.848 ;
     RECT  12.589 19.344 13.208 19.368 ;
     RECT  12.613 22.464 13.208 25.848 ;
     RECT  8.104 27.072 13.208 27.096 ;
     RECT  11.977 29.856 13.208 30.936 ;
     RECT  10.973 32.208 13.208 32.232 ;
     RECT  12.517 33.312 13.208 33.576 ;
     RECT  12.089 35.472 13.208 35.496 ;
     RECT  8.561 38.16 13.208 38.184 ;
     RECT  12.049 40.944 13.208 40.968 ;
     RECT  8.273 59.712 13.208 59.736 ;
     RECT  8.104 78.912 13.208 78.936 ;
     RECT  8.104 84.864 13.208 84.888 ;
     RECT  8.104 100.512 13.208 101.4 ;
     RECT  8.104 102.384 13.208 102.408 ;
     RECT  13.208 2.148 13.312 123.132 ;
     RECT  13.312 2.418 13.504 122.862 ;
     RECT  13.504 29.856 13.601 29.88 ;
     RECT  13.504 30.912 13.889 30.936 ;
     RECT  13.504 33.264 14.321 33.384 ;
     RECT  14.821 35.808 14.857 35.832 ;
     RECT  13.504 38.16 14.969 38.184 ;
     RECT  14.857 35.808 15.077 35.928 ;
     RECT  13.504 32.208 15.325 32.232 ;
     RECT  14.321 33.264 15.325 33.336 ;
     RECT  15.325 32.208 15.361 33.336 ;
     RECT  15.361 30.624 15.541 30.648 ;
     RECT  15.505 29.232 15.757 29.256 ;
     RECT  15.361 32.208 15.757 34.248 ;
     RECT  15.505 37.104 15.757 37.128 ;
     RECT  15.757 28.944 15.793 29.256 ;
     RECT  15.541 30.624 15.793 30.84 ;
     RECT  15.757 32.208 15.833 34.44 ;
     RECT  15.793 28.944 15.937 30.84 ;
     RECT  15.937 28.944 17.089 30.888 ;
     RECT  13.504 22.464 17.129 25.848 ;
     RECT  17.129 23.28 18.313 25.848 ;
     RECT  18.313 22.752 18.608 25.848 ;
     RECT  13.504 27.072 18.608 27.096 ;
     RECT  17.089 28.944 18.608 31.128 ;
     RECT  15.833 32.208 18.608 33.144 ;
     RECT  15.833 34.224 18.608 34.44 ;
     RECT  15.397 35.472 18.608 35.496 ;
     RECT  15.757 37.104 18.608 37.896 ;
     RECT  15.721 40.032 18.608 40.056 ;
     RECT  13.504 59.712 18.608 59.736 ;
     RECT  13.504 78.912 18.608 78.936 ;
     RECT  13.504 84.864 18.608 84.888 ;
     RECT  13.504 100.512 18.608 101.4 ;
     RECT  13.504 102.384 18.608 102.408 ;
     RECT  18.608 2.148 18.712 123.132 ;
     RECT  18.712 2.418 18.904 122.862 ;
     RECT  18.904 28.848 19.001 31.128 ;
     RECT  18.904 32.208 19.289 33.192 ;
     RECT  18.904 66.144 19.379 66.168 ;
     RECT  18.904 27.072 19.433 27.096 ;
     RECT  19.289 32.496 19.933 33.192 ;
     RECT  18.904 34.224 19.933 34.44 ;
     RECT  18.904 84.864 19.973 84.888 ;
     RECT  19.897 68.4 19.981 68.424 ;
     RECT  19.909 67.2 19.996 67.224 ;
     RECT  18.904 63.792 20.009 63.816 ;
     RECT  18.904 78.912 20.081 78.936 ;
     RECT  18.904 23.28 20.197 25.848 ;
     RECT  18.904 59.712 20.365 59.736 ;
     RECT  20.365 59.712 20.449 59.88 ;
     RECT  20.365 66.672 20.449 66.696 ;
     RECT  19.933 32.496 20.509 34.44 ;
     RECT  18.904 35.472 20.509 35.688 ;
     RECT  18.904 36.912 20.509 37.896 ;
     RECT  20.509 32.4 20.653 37.896 ;
     RECT  20.197 23.28 20.689 26.52 ;
     RECT  19.001 28.848 20.689 31.08 ;
     RECT  20.689 68.928 20.773 68.952 ;
     RECT  18.904 39.984 21.049 40.008 ;
     RECT  20.689 28.848 21.085 31.368 ;
     RECT  20.653 32.4 21.085 38.856 ;
     RECT  20.617 47.184 21.085 47.208 ;
     RECT  20.689 23.28 21.107 26.808 ;
     RECT  21.085 42.384 21.121 43.176 ;
     RECT  21.085 49.872 21.121 52.68 ;
     RECT  21.085 41.232 21.481 41.256 ;
     RECT  21.121 42.384 21.481 43.272 ;
     RECT  21.085 28.848 21.517 38.856 ;
     RECT  21.049 39.984 21.517 40.2 ;
     RECT  21.481 41.232 21.517 43.272 ;
     RECT  21.085 46.128 21.517 47.208 ;
     RECT  21.085 64.752 21.517 66.12 ;
     RECT  21.481 67.248 21.517 67.272 ;
     RECT  21.517 41.232 21.553 43.848 ;
     RECT  21.517 45.264 21.553 47.208 ;
     RECT  21.085 59.088 21.553 59.112 ;
     RECT  21.085 60.144 21.553 60.744 ;
     RECT  20.689 62.16 21.553 62.184 ;
     RECT  21.085 63.696 21.553 63.72 ;
     RECT  21.517 64.752 21.553 67.56 ;
     RECT  21.085 48.816 21.589 48.84 ;
     RECT  21.121 49.872 21.589 52.968 ;
     RECT  21.085 54 21.589 54.024 ;
     RECT  21.085 55.056 21.589 55.08 ;
     RECT  21.553 59.088 21.589 62.184 ;
     RECT  21.553 63.696 21.589 67.56 ;
     RECT  21.517 28.848 21.625 40.2 ;
     RECT  21.553 41.232 21.625 47.208 ;
     RECT  21.589 48.336 21.625 52.968 ;
     RECT  21.589 54 21.625 56.904 ;
     RECT  21.589 58.512 21.625 67.848 ;
     RECT  21.625 28.848 22.968 68.52 ;
     RECT  21.107 23.28 24.008 26.52 ;
     RECT  18.904 100.512 24.008 101.4 ;
     RECT  18.904 102.384 24.008 102.408 ;
     RECT  24.008 2.148 24.112 26.52 ;
     RECT  24.008 100.512 24.112 123.132 ;
     RECT  24.112 2.418 24.304 26.52 ;
     RECT  24.112 100.512 24.304 122.862 ;
     RECT  24.304 23.28 29.408 26.52 ;
     RECT  24.304 100.512 29.408 101.4 ;
     RECT  24.304 102.384 29.408 102.408 ;
     RECT  29.408 2.148 29.512 26.52 ;
     RECT  29.408 100.512 29.512 123.132 ;
     RECT  29.512 2.418 29.704 26.52 ;
     RECT  29.512 100.512 29.704 122.862 ;
     RECT  29.704 23.28 34.808 26.52 ;
     RECT  29.704 100.512 34.808 101.4 ;
     RECT  29.704 102.384 34.808 102.408 ;
     RECT  34.808 2.148 34.912 26.52 ;
     RECT  34.808 100.512 34.912 123.132 ;
     RECT  34.912 2.418 35.104 26.52 ;
     RECT  34.912 100.512 35.104 122.862 ;
     RECT  35.104 23.28 40.208 26.52 ;
     RECT  35.104 100.512 40.208 101.4 ;
     RECT  35.104 102.384 40.208 102.408 ;
     RECT  40.208 2.148 40.312 26.52 ;
     RECT  40.208 100.512 40.312 123.132 ;
     RECT  40.312 2.418 40.504 26.52 ;
     RECT  40.312 100.512 40.504 122.862 ;
     RECT  40.504 23.28 45.608 26.52 ;
     RECT  40.504 100.512 45.608 101.4 ;
     RECT  40.504 102.384 45.608 102.408 ;
     RECT  45.608 2.148 45.712 26.52 ;
     RECT  45.608 100.512 45.712 123.132 ;
     RECT  45.712 2.418 45.904 26.52 ;
     RECT  45.712 100.512 45.904 122.862 ;
     RECT  45.904 23.28 51.008 26.52 ;
     RECT  45.904 100.512 51.008 101.4 ;
     RECT  45.904 102.384 51.008 102.408 ;
     RECT  51.008 2.148 51.112 26.52 ;
     RECT  51.008 100.512 51.112 123.132 ;
     RECT  51.112 2.418 51.304 26.52 ;
     RECT  51.112 100.512 51.304 122.862 ;
     RECT  51.304 23.28 56.408 26.52 ;
     RECT  51.304 100.512 56.408 101.4 ;
     RECT  51.304 102.384 56.408 102.408 ;
     RECT  56.408 2.148 56.512 26.52 ;
     RECT  56.408 100.512 56.512 123.132 ;
     RECT  56.512 2.418 56.704 26.52 ;
     RECT  56.512 100.512 56.704 122.862 ;
     RECT  60.949 18.768 61.808 18.792 ;
     RECT  56.704 23.28 61.808 26.52 ;
     RECT  56.704 100.512 61.808 101.4 ;
     RECT  56.704 102.384 61.808 102.408 ;
     RECT  59.785 104.544 61.808 104.568 ;
     RECT  61.808 2.148 61.912 26.52 ;
     RECT  61.808 100.512 61.912 123.132 ;
     RECT  61.912 2.418 62.104 26.52 ;
     RECT  61.912 100.512 62.104 122.862 ;
     RECT  62.104 18.672 62.201 18.792 ;
     RECT  22.968 28.08 64.357 98.55 ;
     RECT  62.104 23.28 64.577 26.52 ;
     RECT  62.104 100.512 65.297 101.4 ;
     RECT  65.297 100.56 65.401 101.4 ;
     RECT  62.104 102.384 65.401 102.408 ;
     RECT  62.104 104.544 65.413 104.568 ;
     RECT  62.201 18.672 65.437 18.696 ;
     RECT  65.401 100.56 65.441 102.408 ;
     RECT  65.437 18.192 65.617 18.696 ;
     RECT  64.577 23.28 65.653 23.592 ;
     RECT  64.577 24.624 65.653 26.52 ;
     RECT  65.617 18.192 65.749 19.368 ;
     RECT  65.653 23.28 66.085 26.52 ;
     RECT  66.085 22.848 66.517 26.52 ;
     RECT  66.517 22.752 66.589 26.52 ;
     RECT  65.749 18.192 66.613 19.8 ;
     RECT  65.413 104.112 66.613 104.568 ;
     RECT  66.613 104.016 66.661 104.568 ;
     RECT  65.473 17.088 66.697 17.112 ;
     RECT  66.613 18.192 66.697 19.848 ;
     RECT  66.697 17.088 66.949 19.848 ;
     RECT  66.949 16.368 67.208 19.848 ;
     RECT  66.589 22.704 67.208 26.52 ;
     RECT  65.441 100.56 67.208 102.024 ;
     RECT  66.661 103.488 67.208 104.568 ;
     RECT  67.208 2.148 67.312 26.52 ;
     RECT  67.208 100.56 67.312 123.132 ;
     RECT  67.312 2.418 67.504 26.52 ;
     RECT  67.312 100.56 67.504 122.862 ;
     RECT  67.504 16.368 67.601 19.848 ;
     RECT  67.504 103.488 69.829 104.568 ;
     RECT  69.829 103.152 70.069 104.568 ;
     RECT  67.504 100.56 70.081 101.592 ;
     RECT  70.069 103.152 70.115 105.384 ;
     RECT  70.081 21.456 70.153 21.48 ;
     RECT  70.081 100.512 70.693 101.592 ;
     RECT  70.693 100.512 71.989 101.688 ;
     RECT  67.601 16.512 72.608 19.848 ;
     RECT  70.153 21.456 72.608 21.528 ;
     RECT  67.504 22.752 72.608 26.52 ;
     RECT  71.989 100.464 72.608 101.688 ;
     RECT  70.115 103.488 72.608 105.384 ;
     RECT  72.608 2.148 72.712 26.52 ;
     RECT  72.608 100.464 72.712 123.132 ;
     RECT  72.712 2.418 72.904 26.52 ;
     RECT  72.712 100.464 72.904 122.862 ;
     RECT  72.904 22.752 74.077 26.52 ;
     RECT  64.357 27.6 74.077 98.55 ;
     RECT  72.904 100.464 74.081 101.688 ;
     RECT  74.081 100.464 75.157 101.4 ;
     RECT  72.904 16.512 78.008 19.848 ;
     RECT  72.904 21.456 78.008 21.528 ;
     RECT  74.077 22.752 78.008 98.55 ;
     RECT  75.157 100.464 78.008 101.88 ;
     RECT  72.904 103.488 78.008 105.384 ;
     RECT  78.008 2.148 78.112 98.55 ;
     RECT  78.008 100.464 78.112 123.132 ;
     RECT  78.112 2.418 78.304 98.55 ;
     RECT  78.112 100.464 78.304 122.862 ;
     RECT  78.304 16.512 83.221 21.528 ;
     RECT  78.304 22.752 83.221 98.55 ;
     RECT  83.221 16.512 83.408 98.55 ;
     RECT  78.304 100.464 83.408 101.88 ;
     RECT  78.304 103.488 83.408 105.384 ;
     RECT  83.408 2.148 83.512 98.55 ;
     RECT  83.408 100.464 83.512 123.132 ;
     RECT  83.512 2.418 83.704 98.55 ;
     RECT  83.512 100.464 83.704 122.862 ;
     RECT  83.704 103.488 83.765 105.384 ;
     RECT  83.765 104.256 84.233 105.384 ;
     RECT  84.233 104.256 84.769 104.568 ;
     RECT  84.769 104.016 84.841 104.568 ;
     RECT  84.841 103.488 85.309 104.568 ;
     RECT  83.704 16.512 88.808 98.55 ;
     RECT  83.704 100.464 88.808 101.88 ;
     RECT  85.309 103.488 88.808 105.384 ;
     RECT  88.808 2.148 88.912 98.55 ;
     RECT  88.808 100.464 88.912 123.132 ;
     RECT  88.912 2.418 89.104 98.55 ;
     RECT  88.912 100.464 89.104 122.862 ;
     RECT  89.104 16.512 94.208 98.55 ;
     RECT  89.104 100.464 94.208 101.88 ;
     RECT  89.104 103.488 94.208 105.384 ;
     RECT  94.208 2.148 94.312 98.55 ;
     RECT  94.208 100.464 94.312 123.132 ;
     RECT  94.312 2.418 94.504 98.55 ;
     RECT  94.312 100.464 94.504 122.862 ;
     RECT  94.504 103.488 96.545 105.384 ;
     RECT  94.504 100.464 97.081 101.88 ;
     RECT  96.545 103.488 97.621 104.28 ;
     RECT  96.545 105.36 97.621 105.384 ;
     RECT  94.504 16.512 99.608 98.55 ;
     RECT  97.081 99.984 99.608 101.88 ;
     RECT  97.621 103.488 99.608 105.384 ;
     RECT  99.608 2.148 99.712 98.55 ;
     RECT  99.608 99.984 99.712 123.132 ;
     RECT  99.712 2.418 99.904 98.55 ;
     RECT  99.712 99.984 99.904 122.862 ;
     RECT  99.904 16.512 105.008 98.55 ;
     RECT  99.904 99.984 105.008 101.88 ;
     RECT  99.904 103.488 105.008 105.384 ;
     RECT  105.008 2.148 105.112 98.55 ;
     RECT  105.008 99.984 105.112 123.132 ;
     RECT  105.112 2.418 105.304 98.55 ;
     RECT  105.112 99.984 105.304 122.862 ;
     RECT  105.304 16.512 106.553 98.55 ;
     RECT  106.553 16.512 107.629 21.528 ;
     RECT  106.553 22.752 107.629 98.55 ;
     RECT  107.629 16.512 110.408 98.55 ;
     RECT  105.304 99.984 110.408 101.88 ;
     RECT  105.304 103.488 110.408 105.384 ;
     RECT  108.373 113.52 110.408 113.544 ;
     RECT  110.408 2.148 110.512 98.55 ;
     RECT  110.408 99.984 110.512 123.132 ;
     RECT  110.512 2.418 110.704 98.55 ;
     RECT  110.512 99.984 110.704 122.862 ;
     RECT  110.704 16.512 115.808 98.55 ;
     RECT  110.704 99.984 115.808 101.88 ;
     RECT  110.704 103.488 115.808 105.384 ;
     RECT  110.704 113.52 115.808 113.544 ;
     RECT  115.808 2.148 115.912 98.55 ;
     RECT  115.808 99.984 115.912 123.132 ;
     RECT  115.912 2.418 116.104 98.55 ;
     RECT  115.912 99.984 116.104 122.862 ;
     RECT  116.104 16.512 121.208 98.55 ;
     RECT  116.104 99.984 121.208 101.88 ;
     RECT  116.104 103.488 121.208 105.384 ;
     RECT  116.104 113.52 121.208 113.544 ;
     RECT  121.208 2.148 121.312 98.55 ;
     RECT  121.208 99.984 121.312 123.132 ;
     RECT  121.312 2.418 121.504 98.55 ;
     RECT  121.312 99.984 121.504 122.862 ;
     RECT  121.504 16.512 126.608 98.55 ;
     RECT  121.504 99.984 126.608 101.88 ;
     RECT  121.504 103.488 126.608 105.384 ;
     RECT  121.504 113.52 126.608 113.544 ;
     RECT  126.608 2.148 126.712 98.55 ;
     RECT  126.608 99.984 126.712 123.132 ;
     RECT  126.712 2.418 126.904 98.55 ;
     RECT  126.712 99.984 126.904 122.862 ;
     RECT  126.904 16.512 132.008 98.55 ;
     RECT  126.904 99.984 132.008 101.88 ;
     RECT  126.904 103.488 132.008 105.384 ;
     RECT  126.904 113.52 132.008 113.544 ;
     RECT  132.008 2.148 132.112 98.55 ;
     RECT  132.008 99.984 132.112 123.132 ;
     RECT  132.112 2.418 132.304 98.55 ;
     RECT  132.112 99.984 132.304 122.862 ;
     RECT  132.304 16.512 137.408 98.55 ;
     RECT  132.304 99.984 137.408 101.88 ;
     RECT  132.304 103.488 137.408 105.384 ;
     RECT  132.304 113.52 137.408 113.544 ;
     RECT  137.408 2.148 137.512 98.55 ;
     RECT  137.408 99.984 137.512 123.132 ;
     RECT  137.512 2.418 137.704 98.55 ;
     RECT  137.512 99.984 137.704 122.862 ;
     RECT  137.704 16.512 142.808 98.55 ;
     RECT  137.704 99.984 142.808 101.88 ;
     RECT  137.704 103.488 142.808 105.384 ;
     RECT  137.704 113.52 142.808 113.544 ;
     RECT  142.808 2.148 142.912 98.55 ;
     RECT  142.808 99.984 142.912 123.132 ;
     RECT  142.912 2.418 143.104 98.55 ;
     RECT  142.912 99.984 143.104 122.862 ;
     RECT  143.104 16.512 148.208 98.55 ;
     RECT  143.104 99.984 148.208 101.88 ;
     RECT  143.104 103.488 148.208 105.384 ;
     RECT  143.104 113.52 148.208 113.544 ;
     RECT  148.208 2.148 148.312 98.55 ;
     RECT  148.208 99.984 148.312 123.132 ;
     RECT  148.312 2.418 148.504 98.55 ;
     RECT  148.312 99.984 148.504 122.862 ;
     RECT  148.504 16.512 153.608 98.55 ;
     RECT  148.504 99.984 153.608 101.88 ;
     RECT  148.504 103.488 153.608 105.384 ;
     RECT  148.504 113.52 153.608 113.544 ;
     RECT  153.608 2.148 153.712 98.55 ;
     RECT  153.608 99.984 153.712 123.132 ;
     RECT  153.712 2.418 153.904 98.55 ;
     RECT  153.712 99.984 153.904 122.862 ;
     RECT  153.904 16.512 159.008 98.55 ;
     RECT  153.904 99.984 159.008 101.88 ;
     RECT  153.904 103.488 159.008 105.384 ;
     RECT  153.904 113.52 159.008 113.544 ;
     RECT  159.008 2.148 159.112 98.55 ;
     RECT  159.008 99.984 159.112 123.132 ;
     RECT  159.112 2.418 159.304 98.55 ;
     RECT  159.112 99.984 159.304 122.862 ;
     RECT  159.304 16.512 164.408 98.55 ;
     RECT  159.304 99.984 164.408 101.88 ;
     RECT  159.304 103.488 164.408 105.384 ;
     RECT  159.304 113.52 164.408 113.544 ;
     RECT  164.408 2.148 164.512 98.55 ;
     RECT  164.408 99.984 164.512 123.132 ;
     RECT  164.512 2.418 164.704 98.55 ;
     RECT  164.512 99.984 164.704 122.862 ;
     RECT  167.132 115.008 167.219 115.032 ;
     RECT  164.704 16.512 169.808 98.55 ;
     RECT  164.704 99.984 169.808 101.88 ;
     RECT  164.704 103.488 169.808 105.384 ;
     RECT  164.704 113.52 169.808 113.544 ;
     RECT  168.685 115.392 169.808 115.656 ;
     RECT  169.808 2.148 169.912 98.55 ;
     RECT  169.808 99.984 169.912 123.132 ;
     RECT  169.912 2.418 170.104 98.55 ;
     RECT  169.912 99.984 170.104 122.862 ;
     RECT  170.104 16.512 175.208 98.55 ;
     RECT  170.104 99.984 175.208 101.88 ;
     RECT  170.104 103.488 175.208 105.384 ;
     RECT  170.104 113.52 175.208 113.544 ;
     RECT  170.104 115.392 175.208 115.656 ;
     RECT  175.208 2.148 175.312 98.55 ;
     RECT  175.208 99.984 175.312 123.132 ;
     RECT  175.312 2.418 175.504 98.55 ;
     RECT  175.312 99.984 175.504 122.862 ;
     RECT  175.504 16.512 180.608 98.55 ;
     RECT  175.504 99.984 180.608 101.88 ;
     RECT  175.504 103.488 180.608 105.384 ;
     RECT  175.504 113.52 180.608 113.544 ;
     RECT  175.504 115.392 180.608 115.656 ;
     RECT  180.608 2.148 180.712 98.55 ;
     RECT  180.608 99.984 180.712 123.132 ;
     RECT  180.712 2.418 180.904 98.55 ;
     RECT  180.712 99.984 180.904 122.862 ;
     RECT  180.904 16.512 186.008 98.55 ;
     RECT  180.904 99.984 186.008 101.88 ;
     RECT  180.904 103.488 186.008 105.384 ;
     RECT  180.904 113.52 186.008 113.544 ;
     RECT  180.904 115.392 186.008 115.656 ;
     RECT  186.008 2.148 186.112 98.55 ;
     RECT  186.008 99.984 186.112 123.132 ;
     RECT  186.112 2.418 186.304 98.55 ;
     RECT  186.112 99.984 186.304 122.862 ;
     RECT  186.304 16.512 191.408 98.55 ;
     RECT  186.304 99.984 191.408 101.88 ;
     RECT  186.304 103.488 191.408 105.384 ;
     RECT  186.304 113.52 191.408 113.544 ;
     RECT  186.304 115.392 191.408 115.656 ;
     RECT  191.408 2.148 191.512 98.55 ;
     RECT  191.408 99.984 191.512 123.132 ;
     RECT  191.512 2.418 191.704 98.55 ;
     RECT  191.512 99.984 191.704 122.862 ;
     RECT  191.704 16.512 196.808 98.55 ;
     RECT  191.704 99.984 196.808 101.88 ;
     RECT  191.704 103.488 196.808 105.384 ;
     RECT  191.704 113.52 196.808 113.544 ;
     RECT  191.704 115.392 196.808 115.656 ;
     RECT  196.808 2.148 196.912 98.55 ;
     RECT  196.808 99.984 196.912 123.132 ;
     RECT  196.912 2.418 197.104 98.55 ;
     RECT  196.912 99.984 197.104 122.862 ;
     RECT  197.104 16.512 197.568 98.55 ;
     RECT  197.104 115.392 197.747 115.656 ;
     RECT  197.104 99.984 197.795 101.88 ;
     RECT  197.795 99.984 198.035 101.352 ;
     RECT  197.104 103.488 198.083 105.384 ;
     RECT  198.083 103.488 198.131 104.568 ;
     RECT  198.131 104.016 198.179 104.568 ;
     RECT  197.568 16.512 198.245 68.616 ;
     RECT  198.179 104.112 198.275 104.568 ;
     RECT  198.035 99.984 198.323 101.112 ;
     RECT  198.323 99.984 198.659 100.776 ;
     RECT  198.275 104.544 198.707 104.568 ;
     RECT  198.245 16.512 198.803 68.52 ;
     RECT  198.803 20.304 199.139 68.52 ;
     RECT  199.139 24.096 199.331 68.52 ;
     RECT  198.803 16.512 199.427 19.32 ;
     RECT  199.331 24.384 199.715 68.52 ;
     RECT  199.715 27.984 199.763 68.52 ;
     RECT  199.715 24.384 199.811 26.472 ;
     RECT  199.825 77.472 199.861 77.496 ;
     RECT  198.659 100.56 199.861 100.776 ;
     RECT  198.613 75.12 199.865 75.144 ;
     RECT  198.661 80.256 199.865 80.28 ;
     RECT  199.763 28.656 199.901 68.52 ;
     RECT  199.901 28.656 199.937 65.592 ;
     RECT  199.901 66.768 199.937 68.52 ;
     RECT  199.853 89.52 199.937 89.544 ;
     RECT  199.937 66.768 199.973 67.272 ;
     RECT  199.973 66.768 200.009 66.888 ;
     RECT  199.937 68.496 200.045 68.52 ;
     RECT  199.861 76.992 200.051 77.496 ;
     RECT  199.861 100.56 200.06 100.92 ;
     RECT  197.104 113.52 200.101 113.544 ;
     RECT  199.937 28.656 200.117 65.112 ;
     RECT  199.139 20.304 200.147 23.016 ;
     RECT  200.06 100.56 200.147 101.448 ;
     RECT  200.117 28.656 200.153 55.944 ;
     RECT  200.117 57.024 200.153 65.112 ;
     RECT  200.051 76.992 200.153 77.016 ;
     RECT  200.005 89.424 200.153 89.448 ;
     RECT  199.427 18.048 200.195 19.32 ;
     RECT  200.153 57.024 200.225 65.016 ;
     RECT  200.225 57.024 200.261 63.144 ;
     RECT  200.195 18.048 200.291 19.272 ;
     RECT  200.261 57.024 200.333 57.096 ;
     RECT  200.261 60.48 200.333 63.144 ;
     RECT  200.261 58.128 200.369 59.4 ;
     RECT  200.333 62.064 200.369 63.144 ;
     RECT  200.225 64.464 200.369 65.016 ;
     RECT  200.369 58.128 200.441 59.352 ;
     RECT  200.369 64.464 200.441 64.776 ;
     RECT  200.147 100.56 200.441 100.92 ;
     RECT  199.811 25.44 200.483 26.472 ;
     RECT  200.441 64.464 200.549 64.488 ;
     RECT  199.811 24.384 200.579 24.408 ;
     RECT  199.427 16.512 200.675 16.872 ;
     RECT  200.333 60.48 200.675 61.032 ;
     RECT  200.545 121.44 200.689 121.464 ;
     RECT  200.675 16.848 200.723 16.872 ;
     RECT  200.675 60.48 200.723 60.504 ;
     RECT  200.291 18.72 200.771 19.272 ;
     RECT  200.333 57.024 200.771 57.048 ;
     RECT  200.101 113.424 200.801 113.544 ;
     RECT  200.147 22.464 200.819 23.016 ;
     RECT  200.369 62.064 200.819 62.76 ;
     RECT  200.725 123.072 200.833 123.096 ;
     RECT  200.483 25.44 200.867 26.088 ;
     RECT  200.819 62.736 200.867 62.76 ;
     RECT  200.771 18.768 200.915 19.272 ;
     RECT  200.801 113.52 200.915 113.544 ;
     RECT  200.833 122.784 200.941 123.096 ;
     RECT  200.147 20.304 200.963 21.432 ;
     RECT  200.963 21.408 201.011 21.432 ;
     RECT  200.941 122.784 201.049 123.72 ;
     RECT  200.689 121.44 201.157 121.512 ;
     RECT  201.049 122.784 201.157 124.296 ;
     RECT  201.157 121.44 201.299 124.296 ;
     RECT  201.299 121.44 201.491 123.72 ;
     RECT  201.349 125.088 201.539 125.112 ;
     RECT  201.157 120.192 201.877 120.216 ;
     RECT  201.877 119.712 201.973 120.216 ;
     RECT  201.491 121.44 201.973 123.672 ;
     RECT  201.973 119.712 202.205 123.672 ;
     RECT  200.915 18.768 202.208 18.792 ;
     RECT  200.963 20.304 202.208 20.328 ;
     RECT  200.819 22.464 202.208 22.488 ;
     RECT  200.867 25.44 202.208 25.512 ;
     RECT  200.153 28.944 202.208 55.944 ;
     RECT  200.441 58.128 202.208 58.152 ;
     RECT  200.441 59.328 202.208 59.352 ;
     RECT  200.441 100.56 202.208 100.632 ;
     RECT  201.493 105.792 202.208 105.816 ;
     RECT  197.747 115.392 202.208 115.416 ;
     RECT  202.205 119.712 202.208 123.288 ;
     RECT  202.208 2.148 202.312 123.288 ;
     RECT  202.312 2.418 202.504 123.288 ;
     RECT  202.504 28.992 202.565 55.272 ;
     RECT  202.504 100.56 202.643 100.632 ;
     RECT  202.565 28.992 202.745 54.936 ;
     RECT  202.745 28.992 202.781 54.456 ;
     RECT  202.504 123.264 202.781 123.288 ;
     RECT  202.781 30.384 202.925 54.456 ;
     RECT  202.925 30.384 202.961 35.016 ;
     RECT  202.504 120.816 202.997 120.84 ;
     RECT  202.961 30.432 203.321 35.016 ;
     RECT  202.925 36.096 203.465 54.456 ;
     RECT  203.516 109.968 203.603 109.992 ;
     RECT  203.465 36.336 203.717 54.456 ;
     RECT  203.321 30.432 203.753 30.744 ;
     RECT  203.557 121.968 204.113 121.992 ;
     RECT  203.321 31.824 204.185 35.016 ;
     RECT  203.717 38.688 204.221 54.456 ;
     RECT  204.185 33.12 204.433 35.016 ;
     RECT  203.717 36.336 204.433 37.704 ;
     RECT  202.781 28.992 204.469 29.016 ;
     RECT  204.433 33.12 204.509 37.704 ;
     RECT  204.221 42.72 204.509 54.456 ;
     RECT  204.469 28.992 204.553 29.064 ;
     RECT  204.221 38.688 204.653 41.688 ;
     RECT  204.553 28.992 204.797 29.016 ;
     RECT  204.509 42.72 204.833 53.592 ;
     RECT  204.653 38.688 204.941 40.584 ;
     RECT  204.833 43.056 205.013 53.592 ;
     RECT  205.013 47.328 205.043 53.592 ;
     RECT  204.509 33.888 205.225 37.704 ;
     RECT  204.941 39.168 205.265 40.584 ;
     RECT  205.265 39.168 205.409 40.296 ;
     RECT  205.225 33.888 205.657 38.04 ;
     RECT  205.013 43.056 205.733 45.624 ;
     RECT  203.753 30.72 205.765 30.744 ;
     RECT  205.657 33.504 205.801 38.04 ;
     RECT  205.765 30.144 205.805 30.744 ;
     RECT  205.043 47.328 206.305 53.544 ;
     RECT  205.409 39.168 206.345 40.152 ;
     RECT  204.185 31.824 206.413 31.848 ;
     RECT  206.305 47.04 206.444 53.544 ;
     RECT  206.341 54.72 206.444 54.744 ;
     RECT  206.444 47.04 206.477 54.744 ;
     RECT  205.225 56.976 206.485 57 ;
     RECT  205.805 30.144 206.521 30.168 ;
     RECT  206.485 56.976 206.525 57.336 ;
     RECT  206.477 47.04 206.531 55.32 ;
     RECT  206.521 30.048 206.561 30.168 ;
     RECT  206.531 54.336 206.561 55.32 ;
     RECT  205.801 32.976 206.569 38.04 ;
     RECT  205.733 43.776 206.629 45.624 ;
     RECT  206.413 31.296 206.809 31.848 ;
     RECT  206.569 32.976 206.809 34.392 ;
     RECT  204.653 41.664 207.02 41.688 ;
     RECT  206.629 43.776 207.061 45.912 ;
     RECT  207.061 43.008 207.241 45.912 ;
     RECT  206.531 47.04 207.241 52.728 ;
     RECT  206.569 35.52 207.385 38.04 ;
     RECT  206.345 39.168 207.385 39.768 ;
     RECT  207.385 35.52 207.457 39.768 ;
     RECT  206.561 30.048 207.608 30.072 ;
     RECT  206.809 31.296 207.608 34.392 ;
     RECT  207.457 35.52 207.608 40.152 ;
     RECT  207.02 41.568 207.608 41.688 ;
     RECT  207.241 43.008 207.608 52.728 ;
     RECT  206.561 54.336 207.608 54.744 ;
     RECT  206.525 57.312 207.608 57.336 ;
     RECT  202.643 100.56 207.608 100.584 ;
     RECT  202.504 115.392 207.608 115.416 ;
     RECT  207.608 2.148 207.712 123.132 ;
     RECT  207.712 2.418 207.904 122.862 ;
     RECT  207.904 35.712 208.073 38.28 ;
     RECT  207.904 41.616 208.073 41.688 ;
     RECT  207.904 43.872 208.181 43.896 ;
     RECT  207.904 45.648 208.325 50.664 ;
     RECT  208.073 41.616 208.361 41.64 ;
     RECT  207.904 51.888 208.649 54.36 ;
     RECT  207.904 39.312 208.684 40.488 ;
     RECT  208.073 36.048 208.685 38.28 ;
     RECT  207.904 29.424 209.045 32.568 ;
     RECT  207.904 57.024 209.081 57.048 ;
     RECT  209.045 30.576 209.149 32.568 ;
     RECT  207.904 33.6 209.149 34.68 ;
     RECT  209.149 30.576 209.153 34.68 ;
     RECT  209.153 30.576 209.261 31.56 ;
     RECT  208.685 36.096 209.261 38.28 ;
     RECT  209.153 32.544 209.293 34.68 ;
     RECT  208.325 45.696 209.329 50.664 ;
     RECT  208.649 51.888 209.329 53.256 ;
     RECT  209.329 45.696 209.333 53.256 ;
     RECT  209.293 32.544 209.369 34.872 ;
     RECT  208.684 39.744 209.411 40.488 ;
     RECT  207.904 115.392 209.459 115.416 ;
     RECT  207.904 55.68 209.66 55.752 ;
     RECT  209.333 45.696 209.693 51.576 ;
     RECT  209.077 54.624 209.725 54.648 ;
     RECT  209.66 55.68 209.747 56.616 ;
     RECT  207.904 100.56 209.747 100.584 ;
     RECT  209.369 33.456 209.761 34.872 ;
     RECT  209.725 54.48 209.797 54.648 ;
     RECT  209.747 55.68 209.797 56.472 ;
     RECT  209.045 29.424 209.909 29.448 ;
     RECT  209.761 33.456 210.049 34.92 ;
     RECT  209.411 40.032 210.049 40.488 ;
     RECT  209.797 54.48 210.053 56.472 ;
     RECT  210.053 54.48 210.085 54.648 ;
     RECT  209.261 36.768 210.089 38.28 ;
     RECT  209.693 45.696 210.092 45.912 ;
     RECT  210.085 54.384 210.125 54.648 ;
     RECT  210.092 44.976 210.179 45.912 ;
     RECT  209.261 31.104 210.193 31.56 ;
     RECT  209.693 46.944 210.301 51.576 ;
     RECT  209.333 52.656 210.301 53.256 ;
     RECT  210.049 33.456 210.341 35.64 ;
     RECT  210.179 45.456 210.341 45.912 ;
     RECT  210.049 40.032 210.373 41.448 ;
     RECT  210.301 46.944 210.377 53.256 ;
     RECT  210.301 29.904 210.413 29.928 ;
     RECT  210.193 31.104 210.413 31.896 ;
     RECT  210.089 36.768 210.413 37.128 ;
     RECT  210.413 31.104 210.449 31.8 ;
     RECT  210.377 48.816 210.485 53.256 ;
     RECT  210.373 40.032 210.773 41.688 ;
     RECT  210.053 55.68 210.985 56.472 ;
     RECT  210.413 36.912 211.165 37.128 ;
     RECT  210.089 38.112 211.165 38.28 ;
     RECT  210.341 33.648 211.205 35.64 ;
     RECT  211.165 36.912 211.379 38.28 ;
     RECT  211.205 33.648 211.381 33.864 ;
     RECT  210.985 55.68 211.381 56.52 ;
     RECT  210.449 31.152 211.421 31.8 ;
     RECT  210.485 48.96 211.421 53.256 ;
     RECT  211.381 32.784 211.453 33.864 ;
     RECT  210.773 40.992 211.453 41.688 ;
     RECT  211.453 40.992 211.493 42.36 ;
     RECT  211.381 55.68 211.532 56.76 ;
     RECT  211.205 34.896 211.561 35.64 ;
     RECT  211.421 31.152 211.597 31.272 ;
     RECT  210.377 46.944 211.597 47.832 ;
     RECT  211.421 48.96 211.597 51.288 ;
     RECT  210.125 54.384 211.597 54.504 ;
     RECT  211.532 55.68 211.619 57.528 ;
     RECT  211.597 46.944 211.741 51.288 ;
     RECT  211.741 46.752 211.745 51.288 ;
     RECT  211.453 32.304 211.781 33.864 ;
     RECT  210.341 45.456 211.813 45.48 ;
     RECT  211.597 30.816 211.853 31.272 ;
     RECT  211.813 45.456 211.853 45.576 ;
     RECT  211.777 40.464 211.885 40.488 ;
     RECT  211.379 36.96 211.921 38.28 ;
     RECT  211.885 39.648 211.921 40.488 ;
     RECT  211.745 50.304 212.033 51.288 ;
     RECT  211.745 46.752 212.173 49.08 ;
     RECT  211.421 52.272 212.461 53.256 ;
     RECT  211.597 54.384 212.461 54.648 ;
     RECT  211.853 45.552 212.641 45.576 ;
     RECT  212.173 46.608 212.641 49.08 ;
     RECT  211.619 55.68 212.821 56.808 ;
     RECT  212.425 57.84 212.821 57.864 ;
     RECT  211.597 29.616 213.008 29.64 ;
     RECT  211.853 30.816 213.008 31.176 ;
     RECT  211.781 33.264 213.008 33.864 ;
     RECT  211.561 34.896 213.008 35.88 ;
     RECT  211.921 36.96 213.008 40.488 ;
     RECT  211.493 41.568 213.008 42.36 ;
     RECT  212.641 45.552 213.008 49.08 ;
     RECT  212.033 50.304 213.008 51 ;
     RECT  212.461 52.272 213.008 54.648 ;
     RECT  212.821 55.68 213.008 57.864 ;
     RECT  213.008 2.148 213.112 123.132 ;
     RECT  213.112 2.418 213.304 122.862 ;
     RECT  213.304 36.672 213.365 39.864 ;
     RECT  213.304 29.232 214.085 29.256 ;
     RECT  213.304 54.96 214.333 57.624 ;
     RECT  213.365 38.16 214.369 39.864 ;
     RECT  213.304 50.352 214.369 53.256 ;
     RECT  214.333 54.72 214.369 57.624 ;
     RECT  213.304 34.416 214.405 34.92 ;
     RECT  213.365 36.672 214.405 36.888 ;
     RECT  214.369 50.352 214.405 57.624 ;
     RECT  213.304 31.872 214.441 31.896 ;
     RECT  214.441 31.776 214.445 31.896 ;
     RECT  214.405 34.416 214.477 35.256 ;
     RECT  214.369 38.16 214.481 40.584 ;
     RECT  214.405 36.672 214.513 37.176 ;
     RECT  214.481 38.16 214.513 40.536 ;
     RECT  214.405 50.256 214.553 57.624 ;
     RECT  214.477 34.416 214.585 35.544 ;
     RECT  214.513 32.976 214.801 33 ;
     RECT  214.585 34.08 214.801 35.544 ;
     RECT  214.801 32.976 214.873 35.544 ;
     RECT  214.513 36.672 214.873 40.536 ;
     RECT  213.304 47.568 215.017 48.984 ;
     RECT  214.553 50.256 215.017 57.576 ;
     RECT  215.017 47.568 215.089 57.576 ;
     RECT  215.089 47.04 215.305 57.576 ;
     RECT  214.445 31.776 215.413 31.8 ;
     RECT  215.413 30.864 215.449 31.8 ;
     RECT  214.873 32.976 215.449 40.536 ;
     RECT  215.305 46.704 215.557 57.576 ;
     RECT  215.557 46.608 215.701 57.576 ;
     RECT  215.701 46.08 215.773 57.576 ;
     RECT  214.369 41.712 215.813 41.736 ;
     RECT  215.449 30.864 215.921 40.536 ;
     RECT  215.921 31.152 216.461 40.536 ;
     RECT  215.773 45.936 216.817 57.576 ;
     RECT  216.817 45.84 216.925 57.576 ;
     RECT  216.925 45.36 217.109 57.576 ;
     RECT  216.461 31.152 217.253 40.008 ;
     RECT  217.033 29.616 217.393 29.64 ;
     RECT  216.745 41.232 217.429 41.256 ;
     RECT  217.393 29.616 217.501 30.024 ;
     RECT  217.253 31.152 217.501 38.04 ;
     RECT  217.501 29.616 217.685 38.04 ;
     RECT  217.429 41.232 217.717 41.832 ;
     RECT  217.685 29.616 217.897 37.704 ;
     RECT  217.897 29.328 218.005 37.704 ;
     RECT  217.109 45.36 218.077 55.848 ;
     RECT  217.109 57.024 218.077 57.576 ;
     RECT  218.077 45.36 218.113 57.576 ;
     RECT  217.717 41.136 218.221 41.832 ;
     RECT  217.253 39.216 218.257 40.008 ;
     RECT  218.221 41.136 218.257 42.12 ;
     RECT  218.005 29.136 218.797 37.704 ;
     RECT  218.257 39.216 218.869 42.12 ;
     RECT  218.797 29.136 219.373 37.992 ;
     RECT  218.869 39.12 219.373 42.12 ;
     RECT  218.113 45.36 219.445 57.672 ;
     RECT  219.373 29.136 220.236 29.16 ;
     RECT  219.373 29.16 220.284 29.232 ;
     RECT  219.373 29.232 220.236 29.256 ;
     RECT  219.373 29.256 220.284 29.328 ;
     RECT  219.373 29.328 220.236 29.352 ;
     RECT  219.373 29.352 220.284 29.424 ;
     RECT  219.373 29.424 220.236 29.448 ;
     RECT  219.373 29.448 220.284 29.52 ;
     RECT  219.373 29.52 220.236 29.544 ;
     RECT  219.373 29.544 220.284 29.616 ;
     RECT  219.373 29.616 220.236 29.64 ;
     RECT  219.373 29.64 220.284 29.712 ;
     RECT  219.373 29.712 220.236 29.736 ;
     RECT  219.373 29.736 220.284 29.808 ;
     RECT  219.373 29.808 220.236 29.832 ;
     RECT  219.373 29.832 220.284 29.904 ;
     RECT  219.373 29.904 220.236 29.928 ;
     RECT  219.373 29.928 220.284 30 ;
     RECT  219.373 30 220.236 30.024 ;
     RECT  219.373 30.024 220.284 30.096 ;
     RECT  219.373 30.096 220.236 30.12 ;
     RECT  219.373 30.12 220.284 30.192 ;
     RECT  219.373 30.192 220.236 30.216 ;
     RECT  219.373 30.216 220.284 30.288 ;
     RECT  219.373 30.288 220.236 30.312 ;
     RECT  219.373 30.312 220.284 30.384 ;
     RECT  219.373 30.384 220.236 30.408 ;
     RECT  219.373 30.408 220.284 30.48 ;
     RECT  219.373 30.48 220.236 30.504 ;
     RECT  219.373 30.504 220.284 30.576 ;
     RECT  219.373 30.576 220.236 30.6 ;
     RECT  219.373 30.6 220.284 30.672 ;
     RECT  219.373 30.672 220.236 30.696 ;
     RECT  219.373 30.696 220.284 30.768 ;
     RECT  219.373 30.768 220.236 30.792 ;
     RECT  219.373 30.792 220.284 30.864 ;
     RECT  219.373 30.864 220.236 30.888 ;
     RECT  219.373 30.888 220.284 30.96 ;
     RECT  219.373 30.96 220.236 30.984 ;
     RECT  219.373 30.984 220.284 31.056 ;
     RECT  219.373 31.056 220.236 31.08 ;
     RECT  219.373 31.08 220.284 31.152 ;
     RECT  219.373 31.152 220.236 31.176 ;
     RECT  219.373 31.176 220.284 31.248 ;
     RECT  219.373 31.248 220.236 31.272 ;
     RECT  219.373 31.272 220.284 31.344 ;
     RECT  219.373 31.344 220.236 31.368 ;
     RECT  219.373 31.368 220.284 31.44 ;
     RECT  219.373 31.44 220.236 31.464 ;
     RECT  219.373 31.464 220.284 31.536 ;
     RECT  219.373 31.536 220.236 31.56 ;
     RECT  219.373 31.56 220.284 31.632 ;
     RECT  219.373 31.632 220.236 31.656 ;
     RECT  219.373 31.656 220.284 31.728 ;
     RECT  219.373 31.728 220.236 31.752 ;
     RECT  219.373 31.752 220.284 31.824 ;
     RECT  219.373 31.824 220.236 31.848 ;
     RECT  219.373 31.848 220.284 31.92 ;
     RECT  219.373 31.92 220.236 31.944 ;
     RECT  219.373 31.944 220.284 32.016 ;
     RECT  219.373 32.016 220.236 32.04 ;
     RECT  219.373 32.04 220.284 32.112 ;
     RECT  219.373 32.112 220.236 32.136 ;
     RECT  219.373 32.136 220.284 32.208 ;
     RECT  219.373 32.208 220.236 32.232 ;
     RECT  219.373 32.232 220.284 32.304 ;
     RECT  219.373 32.304 220.236 32.328 ;
     RECT  219.373 32.328 220.284 32.4 ;
     RECT  219.373 32.4 220.236 32.424 ;
     RECT  219.373 32.424 220.284 32.496 ;
     RECT  219.373 32.496 220.236 32.52 ;
     RECT  219.373 32.52 220.284 32.592 ;
     RECT  219.373 32.592 220.236 32.616 ;
     RECT  219.373 32.616 220.284 32.688 ;
     RECT  219.373 32.688 220.236 32.712 ;
     RECT  219.373 32.712 220.284 32.784 ;
     RECT  219.373 32.784 220.236 32.808 ;
     RECT  219.373 32.808 220.284 32.88 ;
     RECT  219.373 32.88 220.236 32.904 ;
     RECT  219.373 32.904 220.284 32.976 ;
     RECT  219.373 32.976 220.236 33 ;
     RECT  219.373 33 220.284 33.072 ;
     RECT  219.373 33.072 220.236 33.096 ;
     RECT  219.373 33.096 220.284 33.168 ;
     RECT  219.373 33.168 220.236 33.192 ;
     RECT  219.373 33.192 220.284 33.264 ;
     RECT  219.373 33.264 220.236 33.288 ;
     RECT  219.373 33.288 220.284 33.36 ;
     RECT  219.373 33.36 220.236 33.384 ;
     RECT  219.373 33.384 220.284 33.456 ;
     RECT  219.373 33.456 220.236 33.48 ;
     RECT  219.373 33.48 220.284 33.552 ;
     RECT  219.373 33.552 220.236 33.576 ;
     RECT  219.373 33.576 220.284 33.648 ;
     RECT  219.373 33.648 220.236 33.672 ;
     RECT  219.373 33.672 220.284 33.744 ;
     RECT  219.373 33.744 220.236 33.768 ;
     RECT  219.373 33.768 220.284 33.84 ;
     RECT  219.373 33.84 220.236 33.864 ;
     RECT  219.373 33.864 220.284 33.936 ;
     RECT  219.373 33.936 220.236 33.96 ;
     RECT  219.373 33.96 220.284 34.032 ;
     RECT  219.373 34.032 220.236 34.056 ;
     RECT  219.373 34.056 220.284 34.128 ;
     RECT  219.373 34.128 220.236 34.152 ;
     RECT  219.373 34.152 220.284 34.224 ;
     RECT  219.373 34.224 220.236 34.248 ;
     RECT  219.373 34.248 220.284 34.32 ;
     RECT  219.373 34.32 220.236 34.344 ;
     RECT  219.373 34.344 220.284 34.416 ;
     RECT  219.373 34.416 220.236 34.44 ;
     RECT  219.373 34.44 220.284 34.512 ;
     RECT  219.373 34.512 220.236 34.536 ;
     RECT  219.373 34.536 220.284 34.608 ;
     RECT  219.373 34.608 220.236 34.632 ;
     RECT  219.373 34.632 220.284 34.704 ;
     RECT  219.373 34.704 220.236 34.728 ;
     RECT  219.373 34.728 220.284 34.8 ;
     RECT  219.373 34.8 220.236 34.824 ;
     RECT  219.373 34.824 220.284 34.896 ;
     RECT  219.373 34.896 220.236 34.92 ;
     RECT  219.373 34.92 220.284 34.992 ;
     RECT  219.373 34.992 220.236 35.016 ;
     RECT  219.373 35.016 220.284 35.088 ;
     RECT  219.373 35.088 220.236 35.112 ;
     RECT  219.373 35.112 220.284 35.184 ;
     RECT  219.373 35.184 220.236 35.208 ;
     RECT  219.373 35.208 220.284 35.28 ;
     RECT  219.373 35.28 220.236 35.304 ;
     RECT  219.373 35.304 220.284 35.376 ;
     RECT  219.373 35.376 220.236 35.4 ;
     RECT  219.373 35.4 220.284 35.472 ;
     RECT  219.373 35.472 220.236 35.496 ;
     RECT  219.373 35.496 220.284 35.568 ;
     RECT  219.373 35.568 220.236 35.592 ;
     RECT  219.373 35.592 220.284 35.664 ;
     RECT  219.373 35.664 220.236 35.688 ;
     RECT  219.373 35.688 220.284 35.76 ;
     RECT  219.373 35.76 220.236 35.784 ;
     RECT  219.373 35.784 220.284 35.856 ;
     RECT  219.373 35.856 220.236 35.88 ;
     RECT  219.373 35.88 220.284 35.952 ;
     RECT  219.373 35.952 220.236 35.976 ;
     RECT  219.373 35.976 220.284 36.048 ;
     RECT  219.373 36.048 220.236 36.072 ;
     RECT  219.373 36.072 220.284 36.144 ;
     RECT  219.373 36.144 220.236 36.168 ;
     RECT  219.373 36.168 220.284 36.24 ;
     RECT  219.373 36.24 220.236 36.264 ;
     RECT  219.373 36.264 220.284 36.336 ;
     RECT  219.373 36.336 220.236 36.36 ;
     RECT  219.373 36.36 220.284 36.432 ;
     RECT  219.373 36.432 220.236 36.456 ;
     RECT  219.373 36.456 220.284 36.528 ;
     RECT  219.373 36.528 220.236 36.552 ;
     RECT  219.373 36.552 220.284 36.624 ;
     RECT  219.373 36.624 220.236 36.648 ;
     RECT  219.373 36.648 220.284 36.72 ;
     RECT  219.373 36.72 220.236 36.744 ;
     RECT  219.373 36.744 220.284 36.816 ;
     RECT  219.373 36.816 220.236 36.84 ;
     RECT  219.373 36.84 220.284 36.912 ;
     RECT  219.373 36.912 220.236 36.936 ;
     RECT  219.373 36.936 220.284 37.008 ;
     RECT  219.373 37.008 220.236 37.032 ;
     RECT  219.373 37.032 220.284 37.104 ;
     RECT  219.373 37.104 220.236 37.128 ;
     RECT  219.373 37.128 220.284 37.2 ;
     RECT  219.373 37.2 220.236 37.224 ;
     RECT  219.373 37.224 220.284 37.296 ;
     RECT  219.373 37.296 220.236 37.32 ;
     RECT  219.373 37.32 220.284 37.392 ;
     RECT  219.373 37.392 220.236 37.416 ;
     RECT  219.373 37.416 220.284 37.488 ;
     RECT  219.373 37.488 220.236 37.512 ;
     RECT  219.373 37.512 220.284 37.584 ;
     RECT  219.373 37.584 220.236 37.608 ;
     RECT  219.373 37.608 220.284 37.68 ;
     RECT  219.373 37.68 220.236 37.704 ;
     RECT  219.373 37.704 220.284 37.776 ;
     RECT  219.373 37.776 220.236 37.8 ;
     RECT  219.373 37.8 220.284 37.872 ;
     RECT  219.373 37.872 220.236 37.896 ;
     RECT  219.373 37.896 220.284 37.968 ;
     RECT  219.373 37.968 220.236 37.992 ;
     RECT  219.373 37.992 220.284 38.064 ;
     RECT  219.373 38.064 220.236 38.088 ;
     RECT  219.373 38.088 220.284 38.16 ;
     RECT  219.373 38.16 220.236 38.184 ;
     RECT  219.373 38.184 220.284 38.256 ;
     RECT  219.373 38.256 220.236 38.28 ;
     RECT  219.373 38.28 220.284 39.12 ;
     RECT  219.373 39.12 220.236 39.144 ;
     RECT  219.373 39.144 220.284 39.216 ;
     RECT  219.373 39.216 220.236 39.24 ;
     RECT  219.373 39.24 220.284 39.312 ;
     RECT  219.373 39.312 220.236 39.336 ;
     RECT  219.373 39.336 220.284 39.408 ;
     RECT  219.373 39.408 220.236 39.432 ;
     RECT  219.373 39.432 220.284 39.504 ;
     RECT  219.373 39.504 220.236 39.528 ;
     RECT  219.373 39.528 220.284 39.6 ;
     RECT  219.373 39.6 220.236 39.624 ;
     RECT  219.373 39.624 220.284 39.696 ;
     RECT  219.373 39.696 220.236 39.72 ;
     RECT  219.373 39.72 220.284 39.792 ;
     RECT  219.373 39.792 220.236 39.816 ;
     RECT  219.373 39.816 220.284 39.888 ;
     RECT  219.373 39.888 220.236 39.912 ;
     RECT  219.373 39.912 220.284 39.984 ;
     RECT  219.373 39.984 220.236 40.008 ;
     RECT  219.373 40.008 220.284 40.08 ;
     RECT  219.373 40.08 220.236 40.104 ;
     RECT  219.373 40.104 220.284 40.176 ;
     RECT  219.373 40.176 220.236 40.2 ;
     RECT  219.373 40.2 220.284 40.272 ;
     RECT  219.373 40.272 220.236 40.296 ;
     RECT  219.373 40.296 220.284 40.368 ;
     RECT  219.373 40.368 220.236 40.392 ;
     RECT  219.373 40.392 220.284 40.464 ;
     RECT  219.373 40.464 220.236 40.488 ;
     RECT  219.373 40.488 220.284 40.56 ;
     RECT  219.373 40.56 220.236 40.584 ;
     RECT  219.373 40.584 220.284 40.656 ;
     RECT  219.373 40.656 220.236 40.68 ;
     RECT  219.373 40.68 220.284 40.752 ;
     RECT  219.373 40.752 220.236 40.776 ;
     RECT  219.373 40.776 220.284 40.848 ;
     RECT  219.373 40.848 220.236 40.872 ;
     RECT  219.373 40.872 220.284 40.944 ;
     RECT  219.373 40.944 220.236 40.968 ;
     RECT  219.373 40.968 220.284 41.04 ;
     RECT  219.373 41.04 220.236 41.064 ;
     RECT  219.373 41.064 220.284 41.136 ;
     RECT  219.373 41.136 220.236 41.16 ;
     RECT  219.373 41.16 220.284 41.232 ;
     RECT  219.373 41.232 220.236 41.256 ;
     RECT  219.373 41.256 220.284 41.328 ;
     RECT  219.373 41.328 220.236 41.352 ;
     RECT  219.373 41.352 220.284 41.424 ;
     RECT  219.373 41.424 220.236 41.448 ;
     RECT  219.373 41.448 220.284 41.52 ;
     RECT  219.373 41.52 220.236 41.544 ;
     RECT  219.373 41.544 220.284 41.616 ;
     RECT  219.373 41.616 220.236 41.64 ;
     RECT  219.373 41.64 220.284 41.712 ;
     RECT  219.373 41.712 220.236 41.736 ;
     RECT  219.373 41.736 220.284 41.808 ;
     RECT  219.373 41.808 220.236 41.832 ;
     RECT  219.373 41.832 220.284 41.904 ;
     RECT  219.373 41.904 220.236 41.928 ;
     RECT  219.373 41.928 220.284 42 ;
     RECT  219.373 42 220.236 42.024 ;
     RECT  219.373 42.024 220.284 42.096 ;
     RECT  219.373 42.096 220.236 42.12 ;
     RECT  219.445 45.264 220.236 45.288 ;
     RECT  219.445 45.288 220.284 45.36 ;
     RECT  219.445 45.36 220.236 45.384 ;
     RECT  219.445 45.384 220.284 45.456 ;
     RECT  219.445 45.456 220.236 45.48 ;
     RECT  219.445 45.48 220.284 45.552 ;
     RECT  219.445 45.552 220.236 45.576 ;
     RECT  219.445 45.576 220.284 45.648 ;
     RECT  219.445 45.648 220.236 45.672 ;
     RECT  219.445 45.672 220.284 45.744 ;
     RECT  219.445 45.744 220.236 45.768 ;
     RECT  219.445 45.768 220.284 45.84 ;
     RECT  219.445 45.84 220.236 45.864 ;
     RECT  219.445 45.864 220.284 45.936 ;
     RECT  219.445 45.936 220.236 45.96 ;
     RECT  219.445 45.96 220.284 46.032 ;
     RECT  219.445 46.032 220.236 46.056 ;
     RECT  219.445 46.056 220.284 46.128 ;
     RECT  219.445 46.128 220.236 46.152 ;
     RECT  219.445 46.152 220.284 46.224 ;
     RECT  219.445 46.224 220.236 46.248 ;
     RECT  219.445 46.248 220.284 46.32 ;
     RECT  219.445 46.32 220.236 46.344 ;
     RECT  219.445 46.344 220.284 46.416 ;
     RECT  219.445 46.416 220.236 46.44 ;
     RECT  219.445 46.44 220.284 46.512 ;
     RECT  219.445 46.512 220.236 46.536 ;
     RECT  219.445 46.536 220.284 46.608 ;
     RECT  219.445 46.608 220.236 46.632 ;
     RECT  219.445 46.632 220.284 46.704 ;
     RECT  219.445 46.704 220.236 46.728 ;
     RECT  219.445 46.728 220.284 46.8 ;
     RECT  219.445 46.8 220.236 46.824 ;
     RECT  219.445 46.824 220.284 46.896 ;
     RECT  219.445 46.896 220.236 46.92 ;
     RECT  219.445 46.92 220.284 46.992 ;
     RECT  219.445 46.992 220.236 47.016 ;
     RECT  219.445 47.016 220.284 47.088 ;
     RECT  219.445 47.088 220.236 47.112 ;
     RECT  219.445 47.112 220.284 47.184 ;
     RECT  219.445 47.184 220.236 47.208 ;
     RECT  219.445 47.208 220.284 47.28 ;
     RECT  219.445 47.28 220.236 47.304 ;
     RECT  219.445 47.304 220.284 47.376 ;
     RECT  219.445 47.376 220.236 47.4 ;
     RECT  219.445 47.4 220.284 47.472 ;
     RECT  219.445 47.472 220.236 47.496 ;
     RECT  219.445 47.496 220.284 47.568 ;
     RECT  219.445 47.568 220.236 47.592 ;
     RECT  219.445 47.592 220.284 47.664 ;
     RECT  219.445 47.664 220.236 47.688 ;
     RECT  219.445 47.688 220.284 47.76 ;
     RECT  219.445 47.76 220.236 47.784 ;
     RECT  219.445 47.784 220.284 47.856 ;
     RECT  219.445 47.856 220.236 47.88 ;
     RECT  219.445 47.88 220.284 47.952 ;
     RECT  219.445 47.952 220.236 47.976 ;
     RECT  219.445 47.976 220.284 48.048 ;
     RECT  219.445 48.048 220.236 48.072 ;
     RECT  219.445 48.072 220.284 48.144 ;
     RECT  219.445 48.144 220.236 48.168 ;
     RECT  219.445 48.168 220.284 48.24 ;
     RECT  219.445 48.24 220.236 48.264 ;
     RECT  219.445 48.264 220.284 48.336 ;
     RECT  219.445 48.336 220.236 48.36 ;
     RECT  219.445 48.36 220.284 48.432 ;
     RECT  219.445 48.432 220.236 48.456 ;
     RECT  219.445 48.456 220.284 48.528 ;
     RECT  219.445 48.528 220.236 48.552 ;
     RECT  219.445 48.552 220.284 48.624 ;
     RECT  219.445 48.624 220.236 48.648 ;
     RECT  219.445 48.648 220.284 48.72 ;
     RECT  219.445 48.72 220.236 48.744 ;
     RECT  219.445 48.744 220.284 48.816 ;
     RECT  219.445 48.816 220.236 48.84 ;
     RECT  219.445 48.84 220.284 48.912 ;
     RECT  219.445 48.912 220.236 48.936 ;
     RECT  219.445 48.936 220.284 49.008 ;
     RECT  219.445 49.008 220.236 49.032 ;
     RECT  219.445 49.032 220.284 49.104 ;
     RECT  219.445 49.104 220.236 49.128 ;
     RECT  219.445 49.128 220.284 49.2 ;
     RECT  219.445 49.2 220.236 49.224 ;
     RECT  219.445 49.224 220.284 49.296 ;
     RECT  219.445 49.296 220.236 49.32 ;
     RECT  219.445 49.32 220.284 49.392 ;
     RECT  219.445 49.392 220.236 49.416 ;
     RECT  219.445 49.416 220.284 49.488 ;
     RECT  219.445 49.488 220.236 49.512 ;
     RECT  219.445 49.512 220.284 49.584 ;
     RECT  219.445 49.584 220.236 49.608 ;
     RECT  219.445 49.608 220.284 49.68 ;
     RECT  219.445 49.68 220.236 49.704 ;
     RECT  219.445 49.704 220.284 49.776 ;
     RECT  219.445 49.776 220.236 49.8 ;
     RECT  219.445 49.8 220.284 49.872 ;
     RECT  219.445 49.872 220.236 49.896 ;
     RECT  219.445 49.896 220.284 49.968 ;
     RECT  219.445 49.968 220.236 49.992 ;
     RECT  219.445 49.992 220.284 50.064 ;
     RECT  219.445 50.064 220.236 50.088 ;
     RECT  219.445 50.088 220.284 50.16 ;
     RECT  219.445 50.16 220.236 50.184 ;
     RECT  219.445 50.184 220.284 50.256 ;
     RECT  219.445 50.256 220.236 50.28 ;
     RECT  219.445 50.28 220.284 50.352 ;
     RECT  219.445 50.352 220.236 50.376 ;
     RECT  219.445 50.376 220.284 50.448 ;
     RECT  219.445 50.448 220.236 50.472 ;
     RECT  219.445 50.472 220.284 50.544 ;
     RECT  219.445 50.544 220.236 50.568 ;
     RECT  219.445 50.568 220.284 50.64 ;
     RECT  219.445 50.64 220.236 50.664 ;
     RECT  219.445 50.664 220.284 50.736 ;
     RECT  219.445 50.736 220.236 50.76 ;
     RECT  219.445 50.76 220.284 50.832 ;
     RECT  219.445 50.832 220.236 50.856 ;
     RECT  219.445 50.856 220.284 50.928 ;
     RECT  219.445 50.928 220.236 50.952 ;
     RECT  219.445 50.952 220.284 51.024 ;
     RECT  219.445 51.024 220.236 51.048 ;
     RECT  219.445 51.048 220.284 51.12 ;
     RECT  219.445 51.12 220.236 51.144 ;
     RECT  219.445 51.144 220.284 51.216 ;
     RECT  219.445 51.216 220.236 51.24 ;
     RECT  219.445 51.24 220.284 51.312 ;
     RECT  219.445 51.312 220.236 51.336 ;
     RECT  219.445 51.336 220.284 51.408 ;
     RECT  219.445 51.408 220.236 51.432 ;
     RECT  219.445 51.432 220.284 51.504 ;
     RECT  219.445 51.504 220.236 51.528 ;
     RECT  219.445 51.528 220.284 51.6 ;
     RECT  219.445 51.6 220.236 51.624 ;
     RECT  219.445 51.624 220.284 51.696 ;
     RECT  219.445 51.696 220.236 51.72 ;
     RECT  219.445 51.72 220.284 51.792 ;
     RECT  219.445 51.792 220.236 51.816 ;
     RECT  219.445 51.816 220.284 51.888 ;
     RECT  219.445 51.888 220.236 51.912 ;
     RECT  219.445 51.912 220.284 51.984 ;
     RECT  219.445 51.984 220.236 52.008 ;
     RECT  219.445 52.008 220.284 52.08 ;
     RECT  219.445 52.08 220.236 52.104 ;
     RECT  219.445 52.104 220.284 52.176 ;
     RECT  219.445 52.176 220.236 52.2 ;
     RECT  219.445 52.2 220.284 52.272 ;
     RECT  219.445 52.272 220.236 52.296 ;
     RECT  219.445 52.296 220.284 52.368 ;
     RECT  219.445 52.368 220.236 52.392 ;
     RECT  219.445 52.392 220.284 52.464 ;
     RECT  219.445 52.464 220.236 52.488 ;
     RECT  219.445 52.488 220.284 52.56 ;
     RECT  219.445 52.56 220.236 52.584 ;
     RECT  219.445 52.584 220.284 52.656 ;
     RECT  219.445 52.656 220.236 52.68 ;
     RECT  219.445 52.68 220.284 52.752 ;
     RECT  219.445 52.752 220.236 52.776 ;
     RECT  219.445 52.776 220.284 52.848 ;
     RECT  219.445 52.848 220.236 52.872 ;
     RECT  219.445 52.872 220.284 52.944 ;
     RECT  219.445 52.944 220.236 52.968 ;
     RECT  219.445 52.968 220.284 53.04 ;
     RECT  219.445 53.04 220.236 53.064 ;
     RECT  219.445 53.064 220.284 53.136 ;
     RECT  219.445 53.136 220.236 53.16 ;
     RECT  219.445 53.16 220.284 53.232 ;
     RECT  219.445 53.232 220.236 53.256 ;
     RECT  219.445 53.256 220.284 53.328 ;
     RECT  219.445 53.328 220.236 53.352 ;
     RECT  219.445 53.352 220.284 53.424 ;
     RECT  219.445 53.424 220.236 53.448 ;
     RECT  219.445 53.448 220.284 53.52 ;
     RECT  219.445 53.52 220.236 53.544 ;
     RECT  219.445 53.544 220.284 53.616 ;
     RECT  219.445 53.616 220.236 53.64 ;
     RECT  219.445 53.64 220.284 53.712 ;
     RECT  219.445 53.712 220.236 53.736 ;
     RECT  219.445 53.736 220.284 53.808 ;
     RECT  219.445 53.808 220.236 53.832 ;
     RECT  219.445 53.832 220.284 53.904 ;
     RECT  219.445 53.904 220.236 53.928 ;
     RECT  219.445 53.928 220.284 54 ;
     RECT  219.445 54 220.236 54.024 ;
     RECT  219.445 54.024 220.284 54.096 ;
     RECT  219.445 54.096 220.236 54.12 ;
     RECT  219.445 54.12 220.284 54.192 ;
     RECT  219.445 54.192 220.236 54.216 ;
     RECT  219.445 54.216 220.284 54.288 ;
     RECT  219.445 54.288 220.236 54.312 ;
     RECT  219.445 54.312 220.284 54.384 ;
     RECT  219.445 54.384 220.236 54.408 ;
     RECT  219.445 54.408 220.284 54.48 ;
     RECT  219.445 54.48 220.236 54.504 ;
     RECT  219.445 54.504 220.284 54.576 ;
     RECT  219.445 54.576 220.236 54.6 ;
     RECT  219.445 54.6 220.284 54.672 ;
     RECT  219.445 54.672 220.236 54.696 ;
     RECT  219.445 54.696 220.284 54.768 ;
     RECT  219.445 54.768 220.236 54.792 ;
     RECT  219.445 54.792 220.284 54.864 ;
     RECT  219.445 54.864 220.236 54.888 ;
     RECT  219.445 54.888 220.284 54.96 ;
     RECT  219.445 54.96 220.236 54.984 ;
     RECT  219.445 54.984 220.284 55.056 ;
     RECT  219.445 55.056 220.236 55.08 ;
     RECT  219.445 55.08 220.284 55.152 ;
     RECT  219.445 55.152 220.236 55.176 ;
     RECT  219.445 55.176 220.284 55.248 ;
     RECT  219.445 55.248 220.236 55.272 ;
     RECT  219.445 55.272 220.284 55.344 ;
     RECT  219.445 55.344 220.236 55.368 ;
     RECT  219.445 55.368 220.284 55.44 ;
     RECT  219.445 55.44 220.236 55.464 ;
     RECT  219.445 55.464 220.284 55.536 ;
     RECT  219.445 55.536 220.236 55.56 ;
     RECT  219.445 55.56 220.284 55.632 ;
     RECT  219.445 55.632 220.236 55.656 ;
     RECT  219.445 55.656 220.284 55.728 ;
     RECT  219.445 55.728 220.236 55.752 ;
     RECT  219.445 55.752 220.284 55.824 ;
     RECT  219.445 55.824 220.236 55.848 ;
     RECT  219.445 55.848 220.284 55.92 ;
     RECT  219.445 55.92 220.236 55.944 ;
     RECT  219.445 55.944 220.284 56.016 ;
     RECT  219.445 56.016 220.236 56.04 ;
     RECT  219.445 56.04 220.284 56.112 ;
     RECT  219.445 56.112 220.236 56.136 ;
     RECT  219.445 56.136 220.284 56.208 ;
     RECT  219.445 56.208 220.236 56.232 ;
     RECT  219.445 56.232 220.284 56.304 ;
     RECT  219.445 56.304 220.236 56.328 ;
     RECT  219.445 56.328 220.284 56.4 ;
     RECT  219.445 56.4 220.236 56.424 ;
     RECT  219.445 56.424 220.284 56.496 ;
     RECT  219.445 56.496 220.236 56.52 ;
     RECT  219.445 56.52 220.284 56.592 ;
     RECT  219.445 56.592 220.236 56.616 ;
     RECT  219.445 56.616 220.284 56.688 ;
     RECT  219.445 56.688 220.236 56.712 ;
     RECT  219.445 56.712 220.284 56.784 ;
     RECT  219.445 56.784 220.236 56.808 ;
     RECT  219.445 56.808 220.284 56.88 ;
     RECT  219.445 56.88 220.236 56.904 ;
     RECT  219.445 56.904 220.284 56.976 ;
     RECT  219.445 56.976 220.236 57 ;
     RECT  219.445 57 220.284 57.072 ;
     RECT  219.445 57.072 220.236 57.096 ;
     RECT  219.445 57.096 220.284 57.168 ;
     RECT  219.445 57.168 220.236 57.192 ;
     RECT  219.445 57.192 220.284 57.264 ;
     RECT  219.445 57.264 220.236 57.288 ;
     RECT  219.445 57.288 220.284 57.36 ;
     RECT  219.445 57.36 220.236 57.384 ;
     RECT  219.445 57.384 220.284 57.456 ;
     RECT  219.445 57.456 220.236 57.48 ;
     RECT  219.445 57.48 220.284 57.552 ;
     RECT  219.445 57.552 220.236 57.576 ;
     RECT  219.445 57.576 220.284 57.648 ;
     RECT  219.445 57.648 220.236 57.672 ;
    LAYER M5 ;
     RECT  2.4 2.137 2.52 2.151 ;
     RECT  7.8 2.137 7.92 2.151 ;
     RECT  13.2 2.137 13.32 2.151 ;
     RECT  18.6 2.137 18.72 2.151 ;
     RECT  24 2.137 24.12 2.151 ;
     RECT  29.4 2.137 29.52 2.151 ;
     RECT  34.8 2.137 34.92 2.151 ;
     RECT  40.2 2.137 40.32 2.151 ;
     RECT  45.6 2.137 45.72 2.151 ;
     RECT  51 2.137 51.12 2.151 ;
     RECT  56.4 2.137 56.52 2.151 ;
     RECT  61.8 2.137 61.92 2.151 ;
     RECT  67.2 2.137 67.32 2.151 ;
     RECT  72.6 2.137 72.72 2.151 ;
     RECT  78 2.137 78.12 2.151 ;
     RECT  83.4 2.137 83.52 2.151 ;
     RECT  88.8 2.137 88.92 2.151 ;
     RECT  94.2 2.137 94.32 2.151 ;
     RECT  99.6 2.137 99.72 2.151 ;
     RECT  105 2.137 105.12 2.151 ;
     RECT  110.4 2.137 110.52 2.151 ;
     RECT  115.8 2.137 115.92 2.151 ;
     RECT  121.2 2.137 121.32 2.151 ;
     RECT  126.6 2.137 126.72 2.151 ;
     RECT  132 2.137 132.12 2.151 ;
     RECT  137.4 2.137 137.52 2.151 ;
     RECT  142.8 2.137 142.92 2.151 ;
     RECT  148.2 2.137 148.32 2.151 ;
     RECT  153.6 2.137 153.72 2.151 ;
     RECT  159 2.137 159.12 2.151 ;
     RECT  164.4 2.137 164.52 2.151 ;
     RECT  169.8 2.137 169.92 2.151 ;
     RECT  175.2 2.137 175.32 2.151 ;
     RECT  180.6 2.137 180.72 2.151 ;
     RECT  186 2.137 186.12 2.151 ;
     RECT  191.4 2.137 191.52 2.151 ;
     RECT  196.8 2.137 196.92 2.151 ;
     RECT  202.2 2.137 202.32 2.151 ;
     RECT  207.6 2.137 207.72 2.151 ;
     RECT  213 2.137 213.12 2.151 ;
     RECT  67.2 2.151 67.512 16.789 ;
     RECT  200.64 16.501 200.664 16.837 ;
     RECT  196.8 2.151 197.112 17.413 ;
     RECT  198.144 17.077 198.168 17.413 ;
     RECT  199.2 16.789 199.224 17.605 ;
     RECT  196.8 17.413 198.168 17.989 ;
     RECT  199.2 17.605 199.416 17.989 ;
     RECT  196.8 17.989 199.416 18.037 ;
     RECT  200.64 16.837 200.712 18.037 ;
     RECT  67.2 16.789 68.04 18.709 ;
     RECT  196.8 18.037 200.712 18.709 ;
     RECT  61.8 2.151 62.112 18.757 ;
     RECT  196.8 18.709 200.76 18.757 ;
     RECT  202.2 2.151 202.512 18.757 ;
     RECT  69.408 18.133 69.432 18.949 ;
     RECT  7.8 2.151 8.112 19.237 ;
     RECT  72.6 2.151 72.912 19.237 ;
     RECT  13.2 2.151 13.512 19.333 ;
     RECT  65.76 19.765 65.784 19.813 ;
     RECT  67.104 18.709 68.04 19.813 ;
     RECT  83.4 2.151 83.712 22.453 ;
     RECT  18.6 2.151 18.912 22.741 ;
     RECT  65.76 19.813 68.04 23.411 ;
     RECT  5.952 22.453 5.976 23.557 ;
     RECT  69.12 18.949 69.432 23.987 ;
     RECT  5.952 23.557 6.456 24.421 ;
     RECT  7.488 19.237 8.112 24.421 ;
     RECT  66.624 23.411 68.04 24.563 ;
     RECT  20.736 24.613 20.76 24.661 ;
     RECT  12.624 19.333 13.512 24.947 ;
     RECT  67.2 24.563 67.8 25.139 ;
     RECT  69.408 23.987 69.432 25.139 ;
     RECT  67.2 25.139 67.752 25.283 ;
     RECT  60.96 18.757 62.112 25.715 ;
     RECT  72.48 19.237 72.912 25.715 ;
     RECT  83.232 22.453 83.712 25.715 ;
     RECT  18.336 22.741 18.912 25.763 ;
     RECT  20.736 24.661 21.096 25.765 ;
     RECT  20.4 25.765 21.096 26.485 ;
     RECT  20.208 26.485 21.096 26.819 ;
     RECT  5.952 24.421 8.112 27.061 ;
     RECT  4.752 24.709 4.776 27.877 ;
     RECT  5.76 27.061 8.112 27.877 ;
     RECT  2.4 2.151 2.712 28.357 ;
     RECT  3.696 23.269 3.72 28.357 ;
     RECT  4.752 27.877 8.112 28.357 ;
     RECT  0.144 28.453 0.168 29.029 ;
     RECT  2.4 28.357 8.112 29.605 ;
     RECT  0.144 29.029 0.216 30.037 ;
     RECT  207.6 2.151 207.912 30.037 ;
     RECT  0.144 30.037 0.504 30.565 ;
     RECT  0.144 30.565 0.552 30.755 ;
     RECT  22.656 30.757 22.68 30.899 ;
     RECT  206.88 30.037 207.912 31.331 ;
     RECT  2.304 29.605 8.112 31.427 ;
     RECT  207.6 31.331 207.912 31.669 ;
     RECT  211.344 31.765 211.368 32.293 ;
     RECT  0.144 30.755 0.504 32.389 ;
     RECT  207.6 31.669 208.632 32.531 ;
     RECT  2.4 31.427 8.112 33.589 ;
     RECT  211.344 32.293 211.56 33.683 ;
     RECT  211.344 33.683 211.512 33.875 ;
     RECT  0.144 32.389 0.552 34.307 ;
     RECT  206.496 34.165 206.52 34.835 ;
     RECT  2.304 33.589 8.112 35.269 ;
     RECT  2.304 35.269 8.232 35.411 ;
     RECT  2.304 35.411 8.112 35.507 ;
     RECT  0.192 34.307 0.552 35.555 ;
     RECT  0.192 35.555 0.408 35.557 ;
     RECT  2.4 35.507 8.112 36.997 ;
     RECT  204.48 29.029 204.504 37.043 ;
     RECT  0.144 35.557 0.408 37.237 ;
     RECT  211.344 33.875 211.368 37.859 ;
     RECT  207.6 32.531 207.912 38.725 ;
     RECT  0.144 37.237 0.456 38.773 ;
     RECT  0.144 38.773 0.504 38.819 ;
     RECT  0.192 38.819 0.504 39.011 ;
     RECT  205.728 36.997 205.752 39.203 ;
     RECT  196.8 18.757 202.512 39.253 ;
     RECT  207.408 38.725 207.912 39.301 ;
     RECT  209.424 34.645 209.448 39.301 ;
     RECT  207.408 39.301 209.448 39.347 ;
     RECT  2.304 36.997 8.808 39.395 ;
     RECT  0.24 39.011 0.504 39.685 ;
     RECT  196.8 39.253 202.968 39.923 ;
     RECT  204 39.301 204.024 39.923 ;
     RECT  207.504 39.347 209.448 40.067 ;
     RECT  207.6 40.067 209.448 40.499 ;
     RECT  0.24 39.685 0.552 40.645 ;
     RECT  0.144 40.645 1.272 40.883 ;
     RECT  0.144 40.883 0.552 41.171 ;
     RECT  0.144 41.171 0.456 41.363 ;
     RECT  0.144 41.363 0.36 41.411 ;
     RECT  207.6 40.499 207.912 41.557 ;
     RECT  2.304 39.395 8.112 41.651 ;
     RECT  0.144 41.411 0.264 42.227 ;
     RECT  213 2.151 213.312 42.325 ;
     RECT  0.144 42.227 0.168 42.803 ;
     RECT  207.072 41.557 207.912 43.043 ;
     RECT  2.4 41.651 8.112 43.283 ;
     RECT  3.696 43.283 8.112 43.427 ;
     RECT  204.576 43.573 204.6 43.715 ;
     RECT  209.376 40.499 209.448 44.965 ;
     RECT  209.376 44.965 210.168 45.491 ;
     RECT  203.664 44.389 203.688 45.541 ;
     RECT  203.52 45.541 203.688 45.635 ;
     RECT  212.88 42.325 213.312 45.683 ;
     RECT  3.696 43.427 3.72 46.069 ;
     RECT  4.752 43.427 8.112 46.069 ;
     RECT  203.52 45.635 203.544 46.931 ;
     RECT  196.8 39.923 202.512 47.125 ;
     RECT  205.44 43.765 205.464 47.317 ;
     RECT  204.624 47.317 205.464 47.363 ;
     RECT  209.376 45.491 209.448 47.797 ;
     RECT  204.624 47.363 204.648 47.843 ;
     RECT  196.8 47.125 202.872 48.757 ;
     RECT  196.8 48.757 203.4 49.139 ;
     RECT  196.8 49.139 203.208 50.003 ;
     RECT  206.592 49.909 206.616 50.677 ;
     RECT  206.352 50.677 206.616 50.723 ;
     RECT  206.352 50.723 206.376 51.299 ;
     RECT  209.376 47.797 209.736 51.347 ;
     RECT  216.816 51.301 216.84 51.491 ;
     RECT  206.496 52.693 206.52 53.365 ;
     RECT  2.4 43.283 2.712 53.509 ;
     RECT  3.696 46.069 8.112 53.509 ;
     RECT  205.008 52.981 205.032 53.603 ;
     RECT  0.384 53.893 0.408 54.085 ;
     RECT  196.8 50.003 202.92 54.131 ;
     RECT  0.192 54.085 0.408 54.469 ;
     RECT  206.352 53.365 206.52 54.755 ;
     RECT  206.496 54.755 206.52 55.331 ;
     RECT  0.144 54.469 0.408 55.717 ;
     RECT  0.144 55.717 0.456 56.053 ;
     RECT  0.144 56.053 0.504 56.435 ;
     RECT  2.4 53.509 8.112 56.531 ;
     RECT  220.128 57.157 220.152 57.347 ;
     RECT  0.192 56.435 0.504 57.397 ;
     RECT  211.584 56.725 211.608 57.539 ;
     RECT  0.144 57.397 0.504 57.685 ;
     RECT  2.4 56.531 4.776 57.973 ;
     RECT  2.4 57.973 5.112 58.549 ;
     RECT  2.304 58.549 5.112 58.645 ;
     RECT  6.144 56.531 8.112 58.645 ;
     RECT  0.144 57.685 0.552 58.787 ;
     RECT  196.8 54.131 202.632 59.363 ;
     RECT  20.208 26.819 20.76 59.747 ;
     RECT  20.4 59.747 20.76 59.891 ;
     RECT  0.192 58.787 0.552 59.941 ;
     RECT  0.144 59.941 0.552 61.189 ;
     RECT  0.144 61.189 1.176 61.379 ;
     RECT  196.8 59.363 200.856 61.667 ;
     RECT  2.304 58.645 8.112 62.195 ;
     RECT  20.736 59.891 20.76 62.195 ;
     RECT  198.912 61.667 200.856 62.195 ;
     RECT  2.304 62.195 6.264 62.243 ;
     RECT  0.144 61.379 0.552 62.291 ;
     RECT  199.296 62.195 200.856 62.531 ;
     RECT  2.304 62.243 6.216 62.675 ;
     RECT  199.344 62.531 200.856 62.771 ;
     RECT  0.144 62.291 0.504 62.963 ;
     RECT  196.8 61.667 197.88 62.965 ;
     RECT  0.144 62.963 0.312 63.347 ;
     RECT  0.144 63.347 0.168 63.491 ;
     RECT  196.8 62.965 198.12 63.685 ;
     RECT  18.6 25.763 18.912 63.781 ;
     RECT  196.8 63.685 198.168 63.781 ;
     RECT  2.4 62.675 6.216 63.875 ;
     RECT  0.144 64.741 0.168 64.933 ;
     RECT  2.4 63.875 6.024 65.509 ;
     RECT  7.68 62.195 8.112 65.509 ;
     RECT  2.4 65.509 8.112 65.603 ;
     RECT  2.4 65.603 2.808 65.699 ;
     RECT  3.792 65.603 8.112 65.699 ;
     RECT  0.144 64.933 0.312 65.747 ;
     RECT  0.144 65.747 0.216 65.891 ;
     RECT  18.6 63.781 19.368 66.179 ;
     RECT  2.4 65.699 2.712 66.661 ;
     RECT  3.792 65.699 4.536 66.661 ;
     RECT  5.808 65.699 8.112 66.661 ;
     RECT  196.8 63.781 198.312 66.757 ;
     RECT  20.4 66.661 20.424 67.189 ;
     RECT  199.728 62.771 200.328 67.283 ;
     RECT  2.4 66.661 8.112 67.379 ;
     RECT  2.4 67.379 2.856 67.765 ;
     RECT  0.144 65.891 0.168 67.859 ;
     RECT  19.92 67.189 20.424 68.435 ;
     RECT  2.304 67.765 2.856 68.483 ;
     RECT  2.4 68.483 2.856 68.821 ;
     RECT  3.84 67.379 8.112 68.821 ;
     RECT  20.4 68.435 20.424 68.917 ;
     RECT  196.8 66.757 198.36 75.109 ;
     RECT  199.872 67.283 200.328 77.027 ;
     RECT  196.8 75.109 198.648 80.245 ;
     RECT  2.4 68.821 8.112 80.435 ;
     RECT  3.84 80.435 8.112 88.403 ;
     RECT  200.016 77.027 200.328 89.509 ;
     RECT  209.424 51.347 209.736 100.595 ;
     RECT  199.872 89.509 200.328 100.597 ;
     RECT  20.4 68.917 20.76 100.643 ;
     RECT  202.2 59.363 202.632 100.643 ;
     RECT  199.872 100.597 200.424 100.787 ;
     RECT  199.872 100.787 200.136 100.931 ;
     RECT  5.088 88.403 8.112 101.123 ;
     RECT  20.4 100.643 20.424 101.123 ;
     RECT  5.088 101.123 6.504 101.171 ;
     RECT  6.48 101.171 6.504 101.363 ;
     RECT  3.84 88.403 3.864 101.411 ;
     RECT  74.64 100.933 74.664 101.411 ;
     RECT  67.2 25.283 67.512 101.413 ;
     RECT  5.088 101.171 5.112 102.419 ;
     RECT  66.624 101.413 67.512 104.051 ;
     RECT  65.424 101.413 65.448 104.147 ;
     RECT  196.8 80.245 198.696 104.579 ;
     RECT  70.08 103.141 70.104 105.395 ;
     RECT  196.8 104.579 198.072 105.395 ;
     RECT  202.2 100.643 202.512 105.781 ;
     RECT  200.112 100.931 200.136 113.459 ;
     RECT  201.504 105.781 202.512 113.509 ;
     RECT  108.384 101.413 108.408 113.555 ;
     RECT  167.184 100.789 167.208 115.043 ;
     RECT  209.424 100.595 209.448 115.427 ;
     RECT  196.8 105.395 197.736 115.667 ;
     RECT  203.568 109.957 203.592 122.003 ;
     RECT  2.4 80.435 2.712 123.129 ;
     RECT  7.8 101.123 8.112 123.129 ;
     RECT  13.2 24.947 13.512 123.129 ;
     RECT  18.6 66.179 18.912 123.129 ;
     RECT  24 2.151 24.312 123.129 ;
     RECT  29.4 2.151 29.712 123.129 ;
     RECT  34.8 2.151 35.112 123.129 ;
     RECT  40.2 2.151 40.512 123.129 ;
     RECT  45.6 2.151 45.912 123.129 ;
     RECT  51 2.151 51.312 123.129 ;
     RECT  56.4 2.151 56.712 123.129 ;
     RECT  61.8 25.715 62.112 123.129 ;
     RECT  67.2 104.051 67.512 123.129 ;
     RECT  72.6 25.715 72.912 123.129 ;
     RECT  78 2.151 78.312 123.129 ;
     RECT  83.4 25.715 83.712 123.129 ;
     RECT  88.8 2.151 89.112 123.129 ;
     RECT  94.2 2.151 94.512 123.129 ;
     RECT  99.6 2.151 99.912 123.129 ;
     RECT  105 2.151 105.312 123.129 ;
     RECT  110.4 2.151 110.712 123.129 ;
     RECT  115.8 2.151 116.112 123.129 ;
     RECT  121.2 2.151 121.512 123.129 ;
     RECT  126.6 2.151 126.912 123.129 ;
     RECT  132 2.151 132.312 123.129 ;
     RECT  137.4 2.151 137.712 123.129 ;
     RECT  142.8 2.151 143.112 123.129 ;
     RECT  148.2 2.151 148.512 123.129 ;
     RECT  153.6 2.151 153.912 123.129 ;
     RECT  159 2.151 159.312 123.129 ;
     RECT  164.4 2.151 164.712 123.129 ;
     RECT  169.8 2.151 170.112 123.129 ;
     RECT  175.2 2.151 175.512 123.129 ;
     RECT  180.6 2.151 180.912 123.129 ;
     RECT  186 2.151 186.312 123.129 ;
     RECT  191.4 2.151 191.712 123.129 ;
     RECT  196.8 115.667 197.112 123.129 ;
     RECT  200.88 113.509 202.512 123.129 ;
     RECT  207.6 43.043 207.912 123.129 ;
     RECT  213 45.683 213.312 123.129 ;
     RECT  2.4 123.129 2.52 123.143 ;
     RECT  7.8 123.129 7.92 123.143 ;
     RECT  13.2 123.129 13.32 123.143 ;
     RECT  18.6 123.129 18.72 123.143 ;
     RECT  24 123.129 24.12 123.143 ;
     RECT  29.4 123.129 29.52 123.143 ;
     RECT  34.8 123.129 34.92 123.143 ;
     RECT  40.2 123.129 40.32 123.143 ;
     RECT  45.6 123.129 45.72 123.143 ;
     RECT  51 123.129 51.12 123.143 ;
     RECT  56.4 123.129 56.52 123.143 ;
     RECT  61.8 123.129 61.92 123.143 ;
     RECT  67.2 123.129 67.32 123.143 ;
     RECT  72.6 123.129 72.72 123.143 ;
     RECT  78 123.129 78.12 123.143 ;
     RECT  83.4 123.129 83.52 123.143 ;
     RECT  88.8 123.129 88.92 123.143 ;
     RECT  94.2 123.129 94.32 123.143 ;
     RECT  99.6 123.129 99.72 123.143 ;
     RECT  105 123.129 105.12 123.143 ;
     RECT  110.4 123.129 110.52 123.143 ;
     RECT  115.8 123.129 115.92 123.143 ;
     RECT  121.2 123.129 121.32 123.143 ;
     RECT  126.6 123.129 126.72 123.143 ;
     RECT  132 123.129 132.12 123.143 ;
     RECT  137.4 123.129 137.52 123.143 ;
     RECT  142.8 123.129 142.92 123.143 ;
     RECT  148.2 123.129 148.32 123.143 ;
     RECT  153.6 123.129 153.72 123.143 ;
     RECT  159 123.129 159.12 123.143 ;
     RECT  164.4 123.129 164.52 123.143 ;
     RECT  169.8 123.129 169.92 123.143 ;
     RECT  175.2 123.129 175.32 123.143 ;
     RECT  180.6 123.129 180.72 123.143 ;
     RECT  186 123.129 186.12 123.143 ;
     RECT  191.4 123.129 191.52 123.143 ;
     RECT  196.8 123.129 196.92 123.143 ;
     RECT  200.88 123.129 202.32 123.143 ;
     RECT  207.6 123.129 207.72 123.143 ;
     RECT  213 123.129 213.12 123.143 ;
     RECT  200.88 123.143 202.056 125.196 ;
     RECT  200.904 125.196 200.976 125.264 ;
     RECT  201 125.196 201.072 125.264 ;
     RECT  201.096 125.196 201.168 125.264 ;
     RECT  201.192 125.196 201.264 125.264 ;
     RECT  201.288 125.196 201.36 125.264 ;
     RECT  201.384 125.196 201.456 125.264 ;
     RECT  201.48 125.196 201.552 125.264 ;
     RECT  201.576 125.196 201.648 125.264 ;
     RECT  201.672 125.196 201.744 125.264 ;
     RECT  201.768 125.196 201.84 125.264 ;
     RECT  201.864 125.196 201.936 125.264 ;
     RECT  201.96 125.196 202.032 125.264 ;
     RECT  199.224 16.789 200.64 17.605 ;
     RECT  200.712 16.837 202.2 18.709 ;
     RECT  197.112 17.077 198.144 17.413 ;
     RECT  198.168 17.077 199.2 17.989 ;
     RECT  199.416 17.605 200.64 18.037 ;
     RECT  68.04 18.133 69.408 18.949 ;
     RECT  200.76 18.709 202.2 18.757 ;
     RECT  68.04 18.949 69.12 23.987 ;
     RECT  65.784 19.765 67.104 19.813 ;
     RECT  5.976 22.453 7.488 23.557 ;
     RECT  2.712 23.269 3.696 28.357 ;
     RECT  6.456 23.557 7.488 24.421 ;
     RECT  68.04 23.987 69.408 24.563 ;
     RECT  3.72 24.709 4.752 28.357 ;
     RECT  4.776 24.709 5.952 27.061 ;
     RECT  18.912 25.765 20.4 26.485 ;
     RECT  18.912 26.485 20.208 59.747 ;
     RECT  4.776 27.061 5.76 27.877 ;
     RECT  22.68 30.757 24 30.899 ;
     RECT  211.56 32.293 213 33.683 ;
     RECT  211.512 33.683 213 33.875 ;
     RECT  206.52 34.165 207.6 34.835 ;
     RECT  0.144 34.307 0.192 35.557 ;
     RECT  207.912 34.645 209.424 39.301 ;
     RECT  2.304 35.507 2.4 36.997 ;
     RECT  204.504 36.997 205.728 37.043 ;
     RECT  202.968 39.301 204 39.923 ;
     RECT  207.504 40.067 207.6 41.557 ;
     RECT  207.912 40.499 209.376 51.347 ;
     RECT  1.272 40.645 2.304 40.883 ;
     RECT  2.712 43.283 3.696 53.509 ;
     RECT  3.72 43.427 4.752 46.069 ;
     RECT  202.512 44.389 203.664 45.541 ;
     RECT  202.512 45.541 203.52 46.931 ;
     RECT  202.512 46.931 202.872 47.125 ;
     RECT  206.616 49.909 207.6 50.723 ;
     RECT  206.376 50.723 207.6 51.299 ;
     RECT  206.496 51.299 207.6 52.693 ;
     RECT  207.912 51.347 209.424 115.427 ;
     RECT  206.52 52.693 207.6 55.331 ;
     RECT  205.032 52.981 206.496 53.365 ;
     RECT  205.032 53.365 206.352 53.603 ;
     RECT  0.144 56.435 0.192 57.397 ;
     RECT  4.776 56.531 6.144 57.973 ;
     RECT  211.608 56.725 213 57.539 ;
     RECT  5.112 57.973 6.144 58.645 ;
     RECT  0.144 58.787 0.192 59.941 ;
     RECT  200.856 59.363 202.2 62.771 ;
     RECT  18.912 59.747 20.4 59.891 ;
     RECT  1.176 61.189 2.304 61.379 ;
     RECT  197.88 61.667 198.912 62.195 ;
     RECT  6.264 62.195 7.68 62.243 ;
     RECT  197.88 62.195 199.296 62.531 ;
     RECT  6.216 62.243 7.68 63.875 ;
     RECT  197.88 62.531 199.344 62.771 ;
     RECT  197.88 62.771 199.728 62.965 ;
     RECT  198.12 62.965 199.728 63.685 ;
     RECT  0.144 63.491 0.168 64.741 ;
     RECT  198.168 63.685 199.728 63.781 ;
     RECT  198.312 63.781 199.728 66.757 ;
     RECT  2.808 65.603 3.792 65.699 ;
     RECT  2.712 65.699 3.792 66.661 ;
     RECT  4.536 65.699 5.808 66.661 ;
     RECT  18.912 66.179 19.368 66.661 ;
     RECT  18.912 66.661 20.4 67.189 ;
     RECT  198.36 66.757 199.728 67.283 ;
     RECT  18.912 67.189 19.92 68.435 ;
     RECT  198.36 67.283 199.872 75.109 ;
     RECT  2.856 67.379 3.84 68.821 ;
     RECT  18.912 68.435 20.4 101.123 ;
     RECT  198.648 75.109 199.872 77.027 ;
     RECT  198.648 77.027 200.016 80.245 ;
     RECT  198.696 80.245 200.016 89.509 ;
     RECT  2.712 80.435 3.84 101.411 ;
     RECT  3.864 88.403 5.088 101.411 ;
     RECT  198.696 89.509 199.872 100.931 ;
     RECT  198.696 100.931 200.112 104.579 ;
     RECT  6.504 101.123 7.8 101.363 ;
     RECT  5.112 101.171 6.48 101.363 ;
     RECT  65.448 101.413 66.624 104.051 ;
     RECT  200.136 105.781 201.504 113.459 ;
     RECT  202.512 109.957 203.568 122.003 ;
     RECT  200.88 113.459 201.504 113.509 ;
  END
END ot_hgi_hc_residual_half_static
END LIBRARY
